VERSION 5.8 ;
BUSBITCHARS "[]" ;
DIVIDERCHAR "/" ;
UNITS
    DATABASE MICRONS 1000 ;
END UNITS

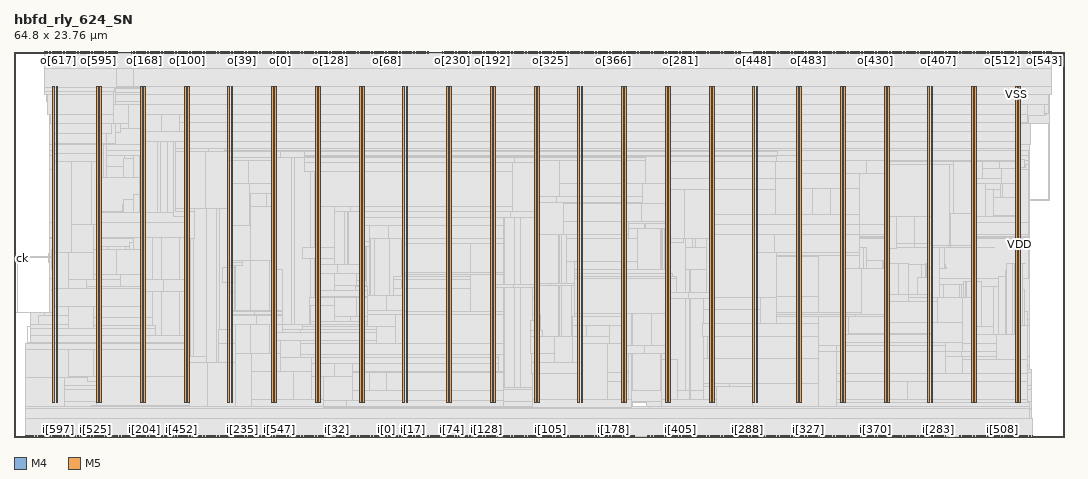
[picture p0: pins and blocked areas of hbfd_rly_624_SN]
MACRO hbfd_rly_624_SN
  FOREIGN hbfd_rly_624_SN 0 0 ;
  CLASS BLOCK ;
  SIZE 64.8 BY 23.76 ;
  PIN ck
    DIRECTION INPUT ;
    USE SIGNAL ;
    PORT
      LAYER M4 ;
        RECT  0 10.992 0.084 11.016 ;
    END
  END ck
  PIN i[0]
    DIRECTION INPUT ;
    USE SIGNAL ;
    PORT
      LAYER M5 ;
        RECT  22.992 0 23.016 0.084 ;
    END
  END i[0]
  PIN i[100]
    DIRECTION INPUT ;
    USE SIGNAL ;
    PORT
      LAYER M5 ;
        RECT  32.592 0 32.616 0.084 ;
    END
  END i[100]
  PIN i[101]
    DIRECTION INPUT ;
    USE SIGNAL ;
    PORT
      LAYER M5 ;
        RECT  32.688 0 32.712 0.084 ;
    END
  END i[101]
  PIN i[102]
    DIRECTION INPUT ;
    USE SIGNAL ;
    PORT
      LAYER M5 ;
        RECT  32.784 0 32.808 0.084 ;
    END
  END i[102]
  PIN i[103]
    DIRECTION INPUT ;
    USE SIGNAL ;
    PORT
      LAYER M5 ;
        RECT  32.88 0 32.904 0.084 ;
    END
  END i[103]
  PIN i[104]
    DIRECTION INPUT ;
    USE SIGNAL ;
    PORT
      LAYER M5 ;
        RECT  32.976 0 33 0.084 ;
    END
  END i[104]
  PIN i[105]
    DIRECTION INPUT ;
    USE SIGNAL ;
    PORT
      LAYER M5 ;
        RECT  33.072 0 33.096 0.084 ;
    END
  END i[105]
  PIN i[106]
    DIRECTION INPUT ;
    USE SIGNAL ;
    PORT
      LAYER M5 ;
        RECT  33.168 0 33.192 0.084 ;
    END
  END i[106]
  PIN i[107]
    DIRECTION INPUT ;
    USE SIGNAL ;
    PORT
      LAYER M5 ;
        RECT  33.264 0 33.288 0.084 ;
    END
  END i[107]
  PIN i[108]
    DIRECTION INPUT ;
    USE SIGNAL ;
    PORT
      LAYER M5 ;
        RECT  33.36 0 33.384 0.084 ;
    END
  END i[108]
  PIN i[109]
    DIRECTION INPUT ;
    USE SIGNAL ;
    PORT
      LAYER M5 ;
        RECT  33.456 0 33.48 0.084 ;
    END
  END i[109]
  PIN i[10]
    DIRECTION INPUT ;
    USE SIGNAL ;
    PORT
      LAYER M5 ;
        RECT  23.952 0 23.976 0.084 ;
    END
  END i[10]
  PIN i[110]
    DIRECTION INPUT ;
    USE SIGNAL ;
    PORT
      LAYER M5 ;
        RECT  33.552 0 33.576 0.084 ;
    END
  END i[110]
  PIN i[111]
    DIRECTION INPUT ;
    USE SIGNAL ;
    PORT
      LAYER M5 ;
        RECT  33.648 0 33.672 0.084 ;
    END
  END i[111]
  PIN i[112]
    DIRECTION INPUT ;
    USE SIGNAL ;
    PORT
      LAYER M5 ;
        RECT  33.744 0 33.768 0.084 ;
    END
  END i[112]
  PIN i[113]
    DIRECTION INPUT ;
    USE SIGNAL ;
    PORT
      LAYER M5 ;
        RECT  33.84 0 33.864 0.084 ;
    END
  END i[113]
  PIN i[114]
    DIRECTION INPUT ;
    USE SIGNAL ;
    PORT
      LAYER M5 ;
        RECT  33.936 0 33.96 0.084 ;
    END
  END i[114]
  PIN i[115]
    DIRECTION INPUT ;
    USE SIGNAL ;
    PORT
      LAYER M5 ;
        RECT  34.032 0 34.056 0.084 ;
    END
  END i[115]
  PIN i[116]
    DIRECTION INPUT ;
    USE SIGNAL ;
    PORT
      LAYER M5 ;
        RECT  34.128 0 34.152 0.084 ;
    END
  END i[116]
  PIN i[117]
    DIRECTION INPUT ;
    USE SIGNAL ;
    PORT
      LAYER M5 ;
        RECT  34.224 0 34.248 0.084 ;
    END
  END i[117]
  PIN i[118]
    DIRECTION INPUT ;
    USE SIGNAL ;
    PORT
      LAYER M5 ;
        RECT  34.32 0 34.344 0.084 ;
    END
  END i[118]
  PIN i[119]
    DIRECTION INPUT ;
    USE SIGNAL ;
    PORT
      LAYER M5 ;
        RECT  34.416 0 34.44 0.084 ;
    END
  END i[119]
  PIN i[11]
    DIRECTION INPUT ;
    USE SIGNAL ;
    PORT
      LAYER M5 ;
        RECT  24.048 0 24.072 0.084 ;
    END
  END i[11]
  PIN i[120]
    DIRECTION INPUT ;
    USE SIGNAL ;
    PORT
      LAYER M5 ;
        RECT  34.512 0 34.536 0.084 ;
    END
  END i[120]
  PIN i[121]
    DIRECTION INPUT ;
    USE SIGNAL ;
    PORT
      LAYER M5 ;
        RECT  34.608 0 34.632 0.084 ;
    END
  END i[121]
  PIN i[122]
    DIRECTION INPUT ;
    USE SIGNAL ;
    PORT
      LAYER M5 ;
        RECT  34.704 0 34.728 0.084 ;
    END
  END i[122]
  PIN i[123]
    DIRECTION INPUT ;
    USE SIGNAL ;
    PORT
      LAYER M5 ;
        RECT  34.8 0 34.824 0.084 ;
    END
  END i[123]
  PIN i[124]
    DIRECTION INPUT ;
    USE SIGNAL ;
    PORT
      LAYER M5 ;
        RECT  34.896 0 34.92 0.084 ;
    END
  END i[124]
  PIN i[125]
    DIRECTION INPUT ;
    USE SIGNAL ;
    PORT
      LAYER M5 ;
        RECT  34.992 0 35.016 0.084 ;
    END
  END i[125]
  PIN i[126]
    DIRECTION INPUT ;
    USE SIGNAL ;
    PORT
      LAYER M5 ;
        RECT  35.088 0 35.112 0.084 ;
    END
  END i[126]
  PIN i[127]
    DIRECTION INPUT ;
    USE SIGNAL ;
    PORT
      LAYER M5 ;
        RECT  35.184 0 35.208 0.084 ;
    END
  END i[127]
  PIN i[128]
    DIRECTION INPUT ;
    USE SIGNAL ;
    PORT
      LAYER M5 ;
        RECT  29.136 0 29.16 0.084 ;
    END
  END i[128]
  PIN i[129]
    DIRECTION INPUT ;
    USE SIGNAL ;
    PORT
      LAYER M5 ;
        RECT  29.232 0 29.256 0.084 ;
    END
  END i[129]
  PIN i[12]
    DIRECTION INPUT ;
    USE SIGNAL ;
    PORT
      LAYER M5 ;
        RECT  24.144 0 24.168 0.084 ;
    END
  END i[12]
  PIN i[130]
    DIRECTION INPUT ;
    USE SIGNAL ;
    PORT
      LAYER M5 ;
        RECT  29.328 0 29.352 0.084 ;
    END
  END i[130]
  PIN i[131]
    DIRECTION INPUT ;
    USE SIGNAL ;
    PORT
      LAYER M5 ;
        RECT  29.424 0 29.448 0.084 ;
    END
  END i[131]
  PIN i[132]
    DIRECTION INPUT ;
    USE SIGNAL ;
    PORT
      LAYER M5 ;
        RECT  29.52 0 29.544 0.084 ;
    END
  END i[132]
  PIN i[133]
    DIRECTION INPUT ;
    USE SIGNAL ;
    PORT
      LAYER M5 ;
        RECT  29.616 0 29.64 0.084 ;
    END
  END i[133]
  PIN i[134]
    DIRECTION INPUT ;
    USE SIGNAL ;
    PORT
      LAYER M5 ;
        RECT  29.712 0 29.736 0.084 ;
    END
  END i[134]
  PIN i[135]
    DIRECTION INPUT ;
    USE SIGNAL ;
    PORT
      LAYER M5 ;
        RECT  29.808 0 29.832 0.084 ;
    END
  END i[135]
  PIN i[136]
    DIRECTION INPUT ;
    USE SIGNAL ;
    PORT
      LAYER M5 ;
        RECT  29.904 0 29.928 0.084 ;
    END
  END i[136]
  PIN i[137]
    DIRECTION INPUT ;
    USE SIGNAL ;
    PORT
      LAYER M5 ;
        RECT  30 0 30.024 0.084 ;
    END
  END i[137]
  PIN i[138]
    DIRECTION INPUT ;
    USE SIGNAL ;
    PORT
      LAYER M5 ;
        RECT  30.096 0 30.12 0.084 ;
    END
  END i[138]
  PIN i[139]
    DIRECTION INPUT ;
    USE SIGNAL ;
    PORT
      LAYER M5 ;
        RECT  30.192 0 30.216 0.084 ;
    END
  END i[139]
  PIN i[13]
    DIRECTION INPUT ;
    USE SIGNAL ;
    PORT
      LAYER M5 ;
        RECT  24.24 0 24.264 0.084 ;
    END
  END i[13]
  PIN i[140]
    DIRECTION INPUT ;
    USE SIGNAL ;
    PORT
      LAYER M5 ;
        RECT  30.288 0 30.312 0.084 ;
    END
  END i[140]
  PIN i[141]
    DIRECTION INPUT ;
    USE SIGNAL ;
    PORT
      LAYER M5 ;
        RECT  30.384 0 30.408 0.084 ;
    END
  END i[141]
  PIN i[142]
    DIRECTION INPUT ;
    USE SIGNAL ;
    PORT
      LAYER M5 ;
        RECT  30.48 0 30.504 0.084 ;
    END
  END i[142]
  PIN i[143]
    DIRECTION INPUT ;
    USE SIGNAL ;
    PORT
      LAYER M5 ;
        RECT  30.576 0 30.6 0.084 ;
    END
  END i[143]
  PIN i[144]
    DIRECTION INPUT ;
    USE SIGNAL ;
    PORT
      LAYER M5 ;
        RECT  30.672 0 30.696 0.084 ;
    END
  END i[144]
  PIN i[145]
    DIRECTION INPUT ;
    USE SIGNAL ;
    PORT
      LAYER M5 ;
        RECT  30.768 0 30.792 0.084 ;
    END
  END i[145]
  PIN i[146]
    DIRECTION INPUT ;
    USE SIGNAL ;
    PORT
      LAYER M5 ;
        RECT  30.864 0 30.888 0.084 ;
    END
  END i[146]
  PIN i[147]
    DIRECTION INPUT ;
    USE SIGNAL ;
    PORT
      LAYER M5 ;
        RECT  30.96 0 30.984 0.084 ;
    END
  END i[147]
  PIN i[148]
    DIRECTION INPUT ;
    USE SIGNAL ;
    PORT
      LAYER M5 ;
        RECT  31.056 0 31.08 0.084 ;
    END
  END i[148]
  PIN i[149]
    DIRECTION INPUT ;
    USE SIGNAL ;
    PORT
      LAYER M5 ;
        RECT  31.152 0 31.176 0.084 ;
    END
  END i[149]
  PIN i[14]
    DIRECTION INPUT ;
    USE SIGNAL ;
    PORT
      LAYER M5 ;
        RECT  24.336 0 24.36 0.084 ;
    END
  END i[14]
  PIN i[150]
    DIRECTION INPUT ;
    USE SIGNAL ;
    PORT
      LAYER M5 ;
        RECT  31.248 0 31.272 0.084 ;
    END
  END i[150]
  PIN i[151]
    DIRECTION INPUT ;
    USE SIGNAL ;
    PORT
      LAYER M5 ;
        RECT  31.344 0 31.368 0.084 ;
    END
  END i[151]
  PIN i[152]
    DIRECTION INPUT ;
    USE SIGNAL ;
    PORT
      LAYER M5 ;
        RECT  31.44 0 31.464 0.084 ;
    END
  END i[152]
  PIN i[153]
    DIRECTION INPUT ;
    USE SIGNAL ;
    PORT
      LAYER M5 ;
        RECT  31.536 0 31.56 0.084 ;
    END
  END i[153]
  PIN i[154]
    DIRECTION INPUT ;
    USE SIGNAL ;
    PORT
      LAYER M5 ;
        RECT  31.632 0 31.656 0.084 ;
    END
  END i[154]
  PIN i[155]
    DIRECTION INPUT ;
    USE SIGNAL ;
    PORT
      LAYER M5 ;
        RECT  31.728 0 31.752 0.084 ;
    END
  END i[155]
  PIN i[156]
    DIRECTION INPUT ;
    USE SIGNAL ;
    PORT
      LAYER M5 ;
        RECT  31.824 0 31.848 0.084 ;
    END
  END i[156]
  PIN i[157]
    DIRECTION INPUT ;
    USE SIGNAL ;
    PORT
      LAYER M5 ;
        RECT  31.92 0 31.944 0.084 ;
    END
  END i[157]
  PIN i[158]
    DIRECTION INPUT ;
    USE SIGNAL ;
    PORT
      LAYER M5 ;
        RECT  32.016 0 32.04 0.084 ;
    END
  END i[158]
  PIN i[159]
    DIRECTION INPUT ;
    USE SIGNAL ;
    PORT
      LAYER M5 ;
        RECT  32.112 0 32.136 0.084 ;
    END
  END i[159]
  PIN i[15]
    DIRECTION INPUT ;
    USE SIGNAL ;
    PORT
      LAYER M5 ;
        RECT  24.432 0 24.456 0.084 ;
    END
  END i[15]
  PIN i[160]
    DIRECTION INPUT ;
    USE SIGNAL ;
    PORT
      LAYER M5 ;
        RECT  35.28 0 35.304 0.084 ;
    END
  END i[160]
  PIN i[161]
    DIRECTION INPUT ;
    USE SIGNAL ;
    PORT
      LAYER M5 ;
        RECT  35.376 0 35.4 0.084 ;
    END
  END i[161]
  PIN i[162]
    DIRECTION INPUT ;
    USE SIGNAL ;
    PORT
      LAYER M5 ;
        RECT  35.472 0 35.496 0.084 ;
    END
  END i[162]
  PIN i[163]
    DIRECTION INPUT ;
    USE SIGNAL ;
    PORT
      LAYER M5 ;
        RECT  35.568 0 35.592 0.084 ;
    END
  END i[163]
  PIN i[164]
    DIRECTION INPUT ;
    USE SIGNAL ;
    PORT
      LAYER M5 ;
        RECT  35.664 0 35.688 0.084 ;
    END
  END i[164]
  PIN i[165]
    DIRECTION INPUT ;
    USE SIGNAL ;
    PORT
      LAYER M5 ;
        RECT  35.76 0 35.784 0.084 ;
    END
  END i[165]
  PIN i[166]
    DIRECTION INPUT ;
    USE SIGNAL ;
    PORT
      LAYER M5 ;
        RECT  35.856 0 35.88 0.084 ;
    END
  END i[166]
  PIN i[167]
    DIRECTION INPUT ;
    USE SIGNAL ;
    PORT
      LAYER M5 ;
        RECT  35.952 0 35.976 0.084 ;
    END
  END i[167]
  PIN i[168]
    DIRECTION INPUT ;
    USE SIGNAL ;
    PORT
      LAYER M5 ;
        RECT  36.048 0 36.072 0.084 ;
    END
  END i[168]
  PIN i[169]
    DIRECTION INPUT ;
    USE SIGNAL ;
    PORT
      LAYER M5 ;
        RECT  36.144 0 36.168 0.084 ;
    END
  END i[169]
  PIN i[16]
    DIRECTION INPUT ;
    USE SIGNAL ;
    PORT
      LAYER M5 ;
        RECT  24.528 0 24.552 0.084 ;
    END
  END i[16]
  PIN i[170]
    DIRECTION INPUT ;
    USE SIGNAL ;
    PORT
      LAYER M5 ;
        RECT  36.24 0 36.264 0.084 ;
    END
  END i[170]
  PIN i[171]
    DIRECTION INPUT ;
    USE SIGNAL ;
    PORT
      LAYER M5 ;
        RECT  36.336 0 36.36 0.084 ;
    END
  END i[171]
  PIN i[172]
    DIRECTION INPUT ;
    USE SIGNAL ;
    PORT
      LAYER M5 ;
        RECT  36.432 0 36.456 0.084 ;
    END
  END i[172]
  PIN i[173]
    DIRECTION INPUT ;
    USE SIGNAL ;
    PORT
      LAYER M5 ;
        RECT  36.528 0 36.552 0.084 ;
    END
  END i[173]
  PIN i[174]
    DIRECTION INPUT ;
    USE SIGNAL ;
    PORT
      LAYER M5 ;
        RECT  36.624 0 36.648 0.084 ;
    END
  END i[174]
  PIN i[175]
    DIRECTION INPUT ;
    USE SIGNAL ;
    PORT
      LAYER M5 ;
        RECT  36.72 0 36.744 0.084 ;
    END
  END i[175]
  PIN i[176]
    DIRECTION INPUT ;
    USE SIGNAL ;
    PORT
      LAYER M5 ;
        RECT  36.816 0 36.84 0.084 ;
    END
  END i[176]
  PIN i[177]
    DIRECTION INPUT ;
    USE SIGNAL ;
    PORT
      LAYER M5 ;
        RECT  36.912 0 36.936 0.084 ;
    END
  END i[177]
  PIN i[178]
    DIRECTION INPUT ;
    USE SIGNAL ;
    PORT
      LAYER M5 ;
        RECT  37.008 0 37.032 0.084 ;
    END
  END i[178]
  PIN i[179]
    DIRECTION INPUT ;
    USE SIGNAL ;
    PORT
      LAYER M5 ;
        RECT  37.104 0 37.128 0.084 ;
    END
  END i[179]
  PIN i[17]
    DIRECTION INPUT ;
    USE SIGNAL ;
    PORT
      LAYER M5 ;
        RECT  24.624 0 24.648 0.084 ;
    END
  END i[17]
  PIN i[180]
    DIRECTION INPUT ;
    USE SIGNAL ;
    PORT
      LAYER M5 ;
        RECT  37.2 0 37.224 0.084 ;
    END
  END i[180]
  PIN i[181]
    DIRECTION INPUT ;
    USE SIGNAL ;
    PORT
      LAYER M5 ;
        RECT  37.296 0 37.32 0.084 ;
    END
  END i[181]
  PIN i[182]
    DIRECTION INPUT ;
    USE SIGNAL ;
    PORT
      LAYER M5 ;
        RECT  37.392 0 37.416 0.084 ;
    END
  END i[182]
  PIN i[183]
    DIRECTION INPUT ;
    USE SIGNAL ;
    PORT
      LAYER M5 ;
        RECT  37.488 0 37.512 0.084 ;
    END
  END i[183]
  PIN i[184]
    DIRECTION INPUT ;
    USE SIGNAL ;
    PORT
      LAYER M5 ;
        RECT  37.584 0 37.608 0.084 ;
    END
  END i[184]
  PIN i[185]
    DIRECTION INPUT ;
    USE SIGNAL ;
    PORT
      LAYER M5 ;
        RECT  37.68 0 37.704 0.084 ;
    END
  END i[185]
  PIN i[186]
    DIRECTION INPUT ;
    USE SIGNAL ;
    PORT
      LAYER M5 ;
        RECT  37.776 0 37.8 0.084 ;
    END
  END i[186]
  PIN i[187]
    DIRECTION INPUT ;
    USE SIGNAL ;
    PORT
      LAYER M5 ;
        RECT  37.872 0 37.896 0.084 ;
    END
  END i[187]
  PIN i[188]
    DIRECTION INPUT ;
    USE SIGNAL ;
    PORT
      LAYER M5 ;
        RECT  37.968 0 37.992 0.084 ;
    END
  END i[188]
  PIN i[189]
    DIRECTION INPUT ;
    USE SIGNAL ;
    PORT
      LAYER M5 ;
        RECT  38.064 0 38.088 0.084 ;
    END
  END i[189]
  PIN i[18]
    DIRECTION INPUT ;
    USE SIGNAL ;
    PORT
      LAYER M5 ;
        RECT  24.72 0 24.744 0.084 ;
    END
  END i[18]
  PIN i[190]
    DIRECTION INPUT ;
    USE SIGNAL ;
    PORT
      LAYER M5 ;
        RECT  38.16 0 38.184 0.084 ;
    END
  END i[190]
  PIN i[191]
    DIRECTION INPUT ;
    USE SIGNAL ;
    PORT
      LAYER M5 ;
        RECT  38.256 0 38.28 0.084 ;
    END
  END i[191]
  PIN i[192]
    DIRECTION INPUT ;
    USE SIGNAL ;
    PORT
      LAYER M5 ;
        RECT  6.864 0 6.888 0.084 ;
    END
  END i[192]
  PIN i[193]
    DIRECTION INPUT ;
    USE SIGNAL ;
    PORT
      LAYER M5 ;
        RECT  6.96 0 6.984 0.084 ;
    END
  END i[193]
  PIN i[194]
    DIRECTION INPUT ;
    USE SIGNAL ;
    PORT
      LAYER M5 ;
        RECT  7.056 0 7.08 0.084 ;
    END
  END i[194]
  PIN i[195]
    DIRECTION INPUT ;
    USE SIGNAL ;
    PORT
      LAYER M5 ;
        RECT  7.152 0 7.176 0.084 ;
    END
  END i[195]
  PIN i[196]
    DIRECTION INPUT ;
    USE SIGNAL ;
    PORT
      LAYER M5 ;
        RECT  7.248 0 7.272 0.084 ;
    END
  END i[196]
  PIN i[197]
    DIRECTION INPUT ;
    USE SIGNAL ;
    PORT
      LAYER M5 ;
        RECT  7.344 0 7.368 0.084 ;
    END
  END i[197]
  PIN i[198]
    DIRECTION INPUT ;
    USE SIGNAL ;
    PORT
      LAYER M5 ;
        RECT  7.44 0 7.464 0.084 ;
    END
  END i[198]
  PIN i[199]
    DIRECTION INPUT ;
    USE SIGNAL ;
    PORT
      LAYER M5 ;
        RECT  7.536 0 7.56 0.084 ;
    END
  END i[199]
  PIN i[19]
    DIRECTION INPUT ;
    USE SIGNAL ;
    PORT
      LAYER M5 ;
        RECT  24.816 0 24.84 0.084 ;
    END
  END i[19]
  PIN i[1]
    DIRECTION INPUT ;
    USE SIGNAL ;
    PORT
      LAYER M5 ;
        RECT  23.088 0 23.112 0.084 ;
    END
  END i[1]
  PIN i[200]
    DIRECTION INPUT ;
    USE SIGNAL ;
    PORT
      LAYER M5 ;
        RECT  7.632 0 7.656 0.084 ;
    END
  END i[200]
  PIN i[201]
    DIRECTION INPUT ;
    USE SIGNAL ;
    PORT
      LAYER M5 ;
        RECT  7.728 0 7.752 0.084 ;
    END
  END i[201]
  PIN i[202]
    DIRECTION INPUT ;
    USE SIGNAL ;
    PORT
      LAYER M5 ;
        RECT  7.824 0 7.848 0.084 ;
    END
  END i[202]
  PIN i[203]
    DIRECTION INPUT ;
    USE SIGNAL ;
    PORT
      LAYER M5 ;
        RECT  7.92 0 7.944 0.084 ;
    END
  END i[203]
  PIN i[204]
    DIRECTION INPUT ;
    USE SIGNAL ;
    PORT
      LAYER M5 ;
        RECT  8.016 0 8.04 0.084 ;
    END
  END i[204]
  PIN i[205]
    DIRECTION INPUT ;
    USE SIGNAL ;
    PORT
      LAYER M5 ;
        RECT  8.112 0 8.136 0.084 ;
    END
  END i[205]
  PIN i[206]
    DIRECTION INPUT ;
    USE SIGNAL ;
    PORT
      LAYER M5 ;
        RECT  8.208 0 8.232 0.084 ;
    END
  END i[206]
  PIN i[207]
    DIRECTION INPUT ;
    USE SIGNAL ;
    PORT
      LAYER M5 ;
        RECT  8.304 0 8.328 0.084 ;
    END
  END i[207]
  PIN i[208]
    DIRECTION INPUT ;
    USE SIGNAL ;
    PORT
      LAYER M5 ;
        RECT  8.4 0 8.424 0.084 ;
    END
  END i[208]
  PIN i[209]
    DIRECTION INPUT ;
    USE SIGNAL ;
    PORT
      LAYER M5 ;
        RECT  8.496 0 8.52 0.084 ;
    END
  END i[209]
  PIN i[20]
    DIRECTION INPUT ;
    USE SIGNAL ;
    PORT
      LAYER M5 ;
        RECT  24.912 0 24.936 0.084 ;
    END
  END i[20]
  PIN i[210]
    DIRECTION INPUT ;
    USE SIGNAL ;
    PORT
      LAYER M5 ;
        RECT  8.592 0 8.616 0.084 ;
    END
  END i[210]
  PIN i[211]
    DIRECTION INPUT ;
    USE SIGNAL ;
    PORT
      LAYER M5 ;
        RECT  8.688 0 8.712 0.084 ;
    END
  END i[211]
  PIN i[212]
    DIRECTION INPUT ;
    USE SIGNAL ;
    PORT
      LAYER M5 ;
        RECT  8.784 0 8.808 0.084 ;
    END
  END i[212]
  PIN i[213]
    DIRECTION INPUT ;
    USE SIGNAL ;
    PORT
      LAYER M5 ;
        RECT  8.88 0 8.904 0.084 ;
    END
  END i[213]
  PIN i[214]
    DIRECTION INPUT ;
    USE SIGNAL ;
    PORT
      LAYER M5 ;
        RECT  8.976 0 9 0.084 ;
    END
  END i[214]
  PIN i[215]
    DIRECTION INPUT ;
    USE SIGNAL ;
    PORT
      LAYER M5 ;
        RECT  9.072 0 9.096 0.084 ;
    END
  END i[215]
  PIN i[216]
    DIRECTION INPUT ;
    USE SIGNAL ;
    PORT
      LAYER M5 ;
        RECT  9.168 0 9.192 0.084 ;
    END
  END i[216]
  PIN i[217]
    DIRECTION INPUT ;
    USE SIGNAL ;
    PORT
      LAYER M5 ;
        RECT  9.264 0 9.288 0.084 ;
    END
  END i[217]
  PIN i[218]
    DIRECTION INPUT ;
    USE SIGNAL ;
    PORT
      LAYER M5 ;
        RECT  9.36 0 9.384 0.084 ;
    END
  END i[218]
  PIN i[219]
    DIRECTION INPUT ;
    USE SIGNAL ;
    PORT
      LAYER M5 ;
        RECT  9.456 0 9.48 0.084 ;
    END
  END i[219]
  PIN i[21]
    DIRECTION INPUT ;
    USE SIGNAL ;
    PORT
      LAYER M5 ;
        RECT  25.008 0 25.032 0.084 ;
    END
  END i[21]
  PIN i[220]
    DIRECTION INPUT ;
    USE SIGNAL ;
    PORT
      LAYER M5 ;
        RECT  9.552 0 9.576 0.084 ;
    END
  END i[220]
  PIN i[221]
    DIRECTION INPUT ;
    USE SIGNAL ;
    PORT
      LAYER M5 ;
        RECT  9.648 0 9.672 0.084 ;
    END
  END i[221]
  PIN i[222]
    DIRECTION INPUT ;
    USE SIGNAL ;
    PORT
      LAYER M5 ;
        RECT  9.744 0 9.768 0.084 ;
    END
  END i[222]
  PIN i[223]
    DIRECTION INPUT ;
    USE SIGNAL ;
    PORT
      LAYER M5 ;
        RECT  9.84 0 9.864 0.084 ;
    END
  END i[223]
  PIN i[224]
    DIRECTION INPUT ;
    USE SIGNAL ;
    PORT
      LAYER M5 ;
        RECT  13.008 0 13.032 0.084 ;
    END
  END i[224]
  PIN i[225]
    DIRECTION INPUT ;
    USE SIGNAL ;
    PORT
      LAYER M5 ;
        RECT  13.104 0 13.128 0.084 ;
    END
  END i[225]
  PIN i[226]
    DIRECTION INPUT ;
    USE SIGNAL ;
    PORT
      LAYER M5 ;
        RECT  13.2 0 13.224 0.084 ;
    END
  END i[226]
  PIN i[227]
    DIRECTION INPUT ;
    USE SIGNAL ;
    PORT
      LAYER M5 ;
        RECT  13.296 0 13.32 0.084 ;
    END
  END i[227]
  PIN i[228]
    DIRECTION INPUT ;
    USE SIGNAL ;
    PORT
      LAYER M5 ;
        RECT  13.392 0 13.416 0.084 ;
    END
  END i[228]
  PIN i[229]
    DIRECTION INPUT ;
    USE SIGNAL ;
    PORT
      LAYER M5 ;
        RECT  13.488 0 13.512 0.084 ;
    END
  END i[229]
  PIN i[22]
    DIRECTION INPUT ;
    USE SIGNAL ;
    PORT
      LAYER M5 ;
        RECT  25.104 0 25.128 0.084 ;
    END
  END i[22]
  PIN i[230]
    DIRECTION INPUT ;
    USE SIGNAL ;
    PORT
      LAYER M5 ;
        RECT  13.584 0 13.608 0.084 ;
    END
  END i[230]
  PIN i[231]
    DIRECTION INPUT ;
    USE SIGNAL ;
    PORT
      LAYER M5 ;
        RECT  13.68 0 13.704 0.084 ;
    END
  END i[231]
  PIN i[232]
    DIRECTION INPUT ;
    USE SIGNAL ;
    PORT
      LAYER M5 ;
        RECT  13.776 0 13.8 0.084 ;
    END
  END i[232]
  PIN i[233]
    DIRECTION INPUT ;
    USE SIGNAL ;
    PORT
      LAYER M5 ;
        RECT  13.872 0 13.896 0.084 ;
    END
  END i[233]
  PIN i[234]
    DIRECTION INPUT ;
    USE SIGNAL ;
    PORT
      LAYER M5 ;
        RECT  13.968 0 13.992 0.084 ;
    END
  END i[234]
  PIN i[235]
    DIRECTION INPUT ;
    USE SIGNAL ;
    PORT
      LAYER M5 ;
        RECT  14.064 0 14.088 0.084 ;
    END
  END i[235]
  PIN i[236]
    DIRECTION INPUT ;
    USE SIGNAL ;
    PORT
      LAYER M5 ;
        RECT  14.16 0 14.184 0.084 ;
    END
  END i[236]
  PIN i[237]
    DIRECTION INPUT ;
    USE SIGNAL ;
    PORT
      LAYER M5 ;
        RECT  14.256 0 14.28 0.084 ;
    END
  END i[237]
  PIN i[238]
    DIRECTION INPUT ;
    USE SIGNAL ;
    PORT
      LAYER M5 ;
        RECT  14.352 0 14.376 0.084 ;
    END
  END i[238]
  PIN i[239]
    DIRECTION INPUT ;
    USE SIGNAL ;
    PORT
      LAYER M5 ;
        RECT  14.448 0 14.472 0.084 ;
    END
  END i[239]
  PIN i[23]
    DIRECTION INPUT ;
    USE SIGNAL ;
    PORT
      LAYER M5 ;
        RECT  25.2 0 25.224 0.084 ;
    END
  END i[23]
  PIN i[240]
    DIRECTION INPUT ;
    USE SIGNAL ;
    PORT
      LAYER M5 ;
        RECT  14.544 0 14.568 0.084 ;
    END
  END i[240]
  PIN i[241]
    DIRECTION INPUT ;
    USE SIGNAL ;
    PORT
      LAYER M5 ;
        RECT  14.64 0 14.664 0.084 ;
    END
  END i[241]
  PIN i[242]
    DIRECTION INPUT ;
    USE SIGNAL ;
    PORT
      LAYER M5 ;
        RECT  14.736 0 14.76 0.084 ;
    END
  END i[242]
  PIN i[243]
    DIRECTION INPUT ;
    USE SIGNAL ;
    PORT
      LAYER M5 ;
        RECT  14.832 0 14.856 0.084 ;
    END
  END i[243]
  PIN i[244]
    DIRECTION INPUT ;
    USE SIGNAL ;
    PORT
      LAYER M5 ;
        RECT  14.928 0 14.952 0.084 ;
    END
  END i[244]
  PIN i[245]
    DIRECTION INPUT ;
    USE SIGNAL ;
    PORT
      LAYER M5 ;
        RECT  15.024 0 15.048 0.084 ;
    END
  END i[245]
  PIN i[246]
    DIRECTION INPUT ;
    USE SIGNAL ;
    PORT
      LAYER M5 ;
        RECT  15.12 0 15.144 0.084 ;
    END
  END i[246]
  PIN i[247]
    DIRECTION INPUT ;
    USE SIGNAL ;
    PORT
      LAYER M5 ;
        RECT  15.216 0 15.24 0.084 ;
    END
  END i[247]
  PIN i[248]
    DIRECTION INPUT ;
    USE SIGNAL ;
    PORT
      LAYER M5 ;
        RECT  15.312 0 15.336 0.084 ;
    END
  END i[248]
  PIN i[249]
    DIRECTION INPUT ;
    USE SIGNAL ;
    PORT
      LAYER M5 ;
        RECT  15.408 0 15.432 0.084 ;
    END
  END i[249]
  PIN i[24]
    DIRECTION INPUT ;
    USE SIGNAL ;
    PORT
      LAYER M5 ;
        RECT  25.296 0 25.32 0.084 ;
    END
  END i[24]
  PIN i[250]
    DIRECTION INPUT ;
    USE SIGNAL ;
    PORT
      LAYER M5 ;
        RECT  15.504 0 15.528 0.084 ;
    END
  END i[250]
  PIN i[251]
    DIRECTION INPUT ;
    USE SIGNAL ;
    PORT
      LAYER M5 ;
        RECT  15.6 0 15.624 0.084 ;
    END
  END i[251]
  PIN i[252]
    DIRECTION INPUT ;
    USE SIGNAL ;
    PORT
      LAYER M5 ;
        RECT  15.696 0 15.72 0.084 ;
    END
  END i[252]
  PIN i[253]
    DIRECTION INPUT ;
    USE SIGNAL ;
    PORT
      LAYER M5 ;
        RECT  15.792 0 15.816 0.084 ;
    END
  END i[253]
  PIN i[254]
    DIRECTION INPUT ;
    USE SIGNAL ;
    PORT
      LAYER M5 ;
        RECT  15.888 0 15.912 0.084 ;
    END
  END i[254]
  PIN i[255]
    DIRECTION INPUT ;
    USE SIGNAL ;
    PORT
      LAYER M5 ;
        RECT  15.984 0 16.008 0.084 ;
    END
  END i[255]
  PIN i[256]
    DIRECTION INPUT ;
    USE SIGNAL ;
    PORT
      LAYER M5 ;
        RECT  54.48 0 54.504 0.084 ;
    END
  END i[256]
  PIN i[257]
    DIRECTION INPUT ;
    USE SIGNAL ;
    PORT
      LAYER M5 ;
        RECT  54.576 0 54.6 0.084 ;
    END
  END i[257]
  PIN i[258]
    DIRECTION INPUT ;
    USE SIGNAL ;
    PORT
      LAYER M5 ;
        RECT  54.672 0 54.696 0.084 ;
    END
  END i[258]
  PIN i[259]
    DIRECTION INPUT ;
    USE SIGNAL ;
    PORT
      LAYER M5 ;
        RECT  54.768 0 54.792 0.084 ;
    END
  END i[259]
  PIN i[25]
    DIRECTION INPUT ;
    USE SIGNAL ;
    PORT
      LAYER M5 ;
        RECT  25.392 0 25.416 0.084 ;
    END
  END i[25]
  PIN i[260]
    DIRECTION INPUT ;
    USE SIGNAL ;
    PORT
      LAYER M5 ;
        RECT  54.864 0 54.888 0.084 ;
    END
  END i[260]
  PIN i[261]
    DIRECTION INPUT ;
    USE SIGNAL ;
    PORT
      LAYER M5 ;
        RECT  54.96 0 54.984 0.084 ;
    END
  END i[261]
  PIN i[262]
    DIRECTION INPUT ;
    USE SIGNAL ;
    PORT
      LAYER M5 ;
        RECT  55.056 0 55.08 0.084 ;
    END
  END i[262]
  PIN i[263]
    DIRECTION INPUT ;
    USE SIGNAL ;
    PORT
      LAYER M5 ;
        RECT  55.152 0 55.176 0.084 ;
    END
  END i[263]
  PIN i[264]
    DIRECTION INPUT ;
    USE SIGNAL ;
    PORT
      LAYER M5 ;
        RECT  55.248 0 55.272 0.084 ;
    END
  END i[264]
  PIN i[265]
    DIRECTION INPUT ;
    USE SIGNAL ;
    PORT
      LAYER M5 ;
        RECT  55.344 0 55.368 0.084 ;
    END
  END i[265]
  PIN i[266]
    DIRECTION INPUT ;
    USE SIGNAL ;
    PORT
      LAYER M5 ;
        RECT  55.44 0 55.464 0.084 ;
    END
  END i[266]
  PIN i[267]
    DIRECTION INPUT ;
    USE SIGNAL ;
    PORT
      LAYER M5 ;
        RECT  55.536 0 55.56 0.084 ;
    END
  END i[267]
  PIN i[268]
    DIRECTION INPUT ;
    USE SIGNAL ;
    PORT
      LAYER M5 ;
        RECT  55.632 0 55.656 0.084 ;
    END
  END i[268]
  PIN i[269]
    DIRECTION INPUT ;
    USE SIGNAL ;
    PORT
      LAYER M5 ;
        RECT  55.728 0 55.752 0.084 ;
    END
  END i[269]
  PIN i[26]
    DIRECTION INPUT ;
    USE SIGNAL ;
    PORT
      LAYER M5 ;
        RECT  25.488 0 25.512 0.084 ;
    END
  END i[26]
  PIN i[270]
    DIRECTION INPUT ;
    USE SIGNAL ;
    PORT
      LAYER M5 ;
        RECT  55.824 0 55.848 0.084 ;
    END
  END i[270]
  PIN i[271]
    DIRECTION INPUT ;
    USE SIGNAL ;
    PORT
      LAYER M5 ;
        RECT  55.92 0 55.944 0.084 ;
    END
  END i[271]
  PIN i[272]
    DIRECTION INPUT ;
    USE SIGNAL ;
    PORT
      LAYER M5 ;
        RECT  56.016 0 56.04 0.084 ;
    END
  END i[272]
  PIN i[273]
    DIRECTION INPUT ;
    USE SIGNAL ;
    PORT
      LAYER M5 ;
        RECT  56.112 0 56.136 0.084 ;
    END
  END i[273]
  PIN i[274]
    DIRECTION INPUT ;
    USE SIGNAL ;
    PORT
      LAYER M5 ;
        RECT  56.208 0 56.232 0.084 ;
    END
  END i[274]
  PIN i[275]
    DIRECTION INPUT ;
    USE SIGNAL ;
    PORT
      LAYER M5 ;
        RECT  56.304 0 56.328 0.084 ;
    END
  END i[275]
  PIN i[276]
    DIRECTION INPUT ;
    USE SIGNAL ;
    PORT
      LAYER M5 ;
        RECT  56.4 0 56.424 0.084 ;
    END
  END i[276]
  PIN i[277]
    DIRECTION INPUT ;
    USE SIGNAL ;
    PORT
      LAYER M5 ;
        RECT  56.496 0 56.52 0.084 ;
    END
  END i[277]
  PIN i[278]
    DIRECTION INPUT ;
    USE SIGNAL ;
    PORT
      LAYER M5 ;
        RECT  56.592 0 56.616 0.084 ;
    END
  END i[278]
  PIN i[279]
    DIRECTION INPUT ;
    USE SIGNAL ;
    PORT
      LAYER M5 ;
        RECT  56.688 0 56.712 0.084 ;
    END
  END i[279]
  PIN i[27]
    DIRECTION INPUT ;
    USE SIGNAL ;
    PORT
      LAYER M5 ;
        RECT  25.584 0 25.608 0.084 ;
    END
  END i[27]
  PIN i[280]
    DIRECTION INPUT ;
    USE SIGNAL ;
    PORT
      LAYER M5 ;
        RECT  56.784 0 56.808 0.084 ;
    END
  END i[280]
  PIN i[281]
    DIRECTION INPUT ;
    USE SIGNAL ;
    PORT
      LAYER M5 ;
        RECT  56.88 0 56.904 0.084 ;
    END
  END i[281]
  PIN i[282]
    DIRECTION INPUT ;
    USE SIGNAL ;
    PORT
      LAYER M5 ;
        RECT  56.976 0 57 0.084 ;
    END
  END i[282]
  PIN i[283]
    DIRECTION INPUT ;
    USE SIGNAL ;
    PORT
      LAYER M5 ;
        RECT  57.072 0 57.096 0.084 ;
    END
  END i[283]
  PIN i[284]
    DIRECTION INPUT ;
    USE SIGNAL ;
    PORT
      LAYER M5 ;
        RECT  57.168 0 57.192 0.084 ;
    END
  END i[284]
  PIN i[285]
    DIRECTION INPUT ;
    USE SIGNAL ;
    PORT
      LAYER M5 ;
        RECT  57.264 0 57.288 0.084 ;
    END
  END i[285]
  PIN i[286]
    DIRECTION INPUT ;
    USE SIGNAL ;
    PORT
      LAYER M5 ;
        RECT  57.36 0 57.384 0.084 ;
    END
  END i[286]
  PIN i[287]
    DIRECTION INPUT ;
    USE SIGNAL ;
    PORT
      LAYER M5 ;
        RECT  57.456 0 57.48 0.084 ;
    END
  END i[287]
  PIN i[288]
    DIRECTION INPUT ;
    USE SIGNAL ;
    PORT
      LAYER M5 ;
        RECT  45.264 0 45.288 0.084 ;
    END
  END i[288]
  PIN i[289]
    DIRECTION INPUT ;
    USE SIGNAL ;
    PORT
      LAYER M5 ;
        RECT  45.36 0 45.384 0.084 ;
    END
  END i[289]
  PIN i[28]
    DIRECTION INPUT ;
    USE SIGNAL ;
    PORT
      LAYER M5 ;
        RECT  25.68 0 25.704 0.084 ;
    END
  END i[28]
  PIN i[290]
    DIRECTION INPUT ;
    USE SIGNAL ;
    PORT
      LAYER M5 ;
        RECT  45.456 0 45.48 0.084 ;
    END
  END i[290]
  PIN i[291]
    DIRECTION INPUT ;
    USE SIGNAL ;
    PORT
      LAYER M5 ;
        RECT  45.552 0 45.576 0.084 ;
    END
  END i[291]
  PIN i[292]
    DIRECTION INPUT ;
    USE SIGNAL ;
    PORT
      LAYER M5 ;
        RECT  45.648 0 45.672 0.084 ;
    END
  END i[292]
  PIN i[293]
    DIRECTION INPUT ;
    USE SIGNAL ;
    PORT
      LAYER M5 ;
        RECT  45.744 0 45.768 0.084 ;
    END
  END i[293]
  PIN i[294]
    DIRECTION INPUT ;
    USE SIGNAL ;
    PORT
      LAYER M5 ;
        RECT  45.84 0 45.864 0.084 ;
    END
  END i[294]
  PIN i[295]
    DIRECTION INPUT ;
    USE SIGNAL ;
    PORT
      LAYER M5 ;
        RECT  45.936 0 45.96 0.084 ;
    END
  END i[295]
  PIN i[296]
    DIRECTION INPUT ;
    USE SIGNAL ;
    PORT
      LAYER M5 ;
        RECT  46.032 0 46.056 0.084 ;
    END
  END i[296]
  PIN i[297]
    DIRECTION INPUT ;
    USE SIGNAL ;
    PORT
      LAYER M5 ;
        RECT  46.128 0 46.152 0.084 ;
    END
  END i[297]
  PIN i[298]
    DIRECTION INPUT ;
    USE SIGNAL ;
    PORT
      LAYER M5 ;
        RECT  46.224 0 46.248 0.084 ;
    END
  END i[298]
  PIN i[299]
    DIRECTION INPUT ;
    USE SIGNAL ;
    PORT
      LAYER M5 ;
        RECT  46.32 0 46.344 0.084 ;
    END
  END i[299]
  PIN i[29]
    DIRECTION INPUT ;
    USE SIGNAL ;
    PORT
      LAYER M5 ;
        RECT  25.776 0 25.8 0.084 ;
    END
  END i[29]
  PIN i[2]
    DIRECTION INPUT ;
    USE SIGNAL ;
    PORT
      LAYER M5 ;
        RECT  23.184 0 23.208 0.084 ;
    END
  END i[2]
  PIN i[300]
    DIRECTION INPUT ;
    USE SIGNAL ;
    PORT
      LAYER M5 ;
        RECT  46.416 0 46.44 0.084 ;
    END
  END i[300]
  PIN i[301]
    DIRECTION INPUT ;
    USE SIGNAL ;
    PORT
      LAYER M5 ;
        RECT  46.512 0 46.536 0.084 ;
    END
  END i[301]
  PIN i[302]
    DIRECTION INPUT ;
    USE SIGNAL ;
    PORT
      LAYER M5 ;
        RECT  46.608 0 46.632 0.084 ;
    END
  END i[302]
  PIN i[303]
    DIRECTION INPUT ;
    USE SIGNAL ;
    PORT
      LAYER M5 ;
        RECT  46.704 0 46.728 0.084 ;
    END
  END i[303]
  PIN i[304]
    DIRECTION INPUT ;
    USE SIGNAL ;
    PORT
      LAYER M5 ;
        RECT  46.8 0 46.824 0.084 ;
    END
  END i[304]
  PIN i[305]
    DIRECTION INPUT ;
    USE SIGNAL ;
    PORT
      LAYER M5 ;
        RECT  46.896 0 46.92 0.084 ;
    END
  END i[305]
  PIN i[306]
    DIRECTION INPUT ;
    USE SIGNAL ;
    PORT
      LAYER M5 ;
        RECT  46.992 0 47.016 0.084 ;
    END
  END i[306]
  PIN i[307]
    DIRECTION INPUT ;
    USE SIGNAL ;
    PORT
      LAYER M5 ;
        RECT  47.088 0 47.112 0.084 ;
    END
  END i[307]
  PIN i[308]
    DIRECTION INPUT ;
    USE SIGNAL ;
    PORT
      LAYER M5 ;
        RECT  47.184 0 47.208 0.084 ;
    END
  END i[308]
  PIN i[309]
    DIRECTION INPUT ;
    USE SIGNAL ;
    PORT
      LAYER M5 ;
        RECT  47.28 0 47.304 0.084 ;
    END
  END i[309]
  PIN i[30]
    DIRECTION INPUT ;
    USE SIGNAL ;
    PORT
      LAYER M5 ;
        RECT  25.872 0 25.896 0.084 ;
    END
  END i[30]
  PIN i[310]
    DIRECTION INPUT ;
    USE SIGNAL ;
    PORT
      LAYER M5 ;
        RECT  47.376 0 47.4 0.084 ;
    END
  END i[310]
  PIN i[311]
    DIRECTION INPUT ;
    USE SIGNAL ;
    PORT
      LAYER M5 ;
        RECT  47.472 0 47.496 0.084 ;
    END
  END i[311]
  PIN i[312]
    DIRECTION INPUT ;
    USE SIGNAL ;
    PORT
      LAYER M5 ;
        RECT  47.568 0 47.592 0.084 ;
    END
  END i[312]
  PIN i[313]
    DIRECTION INPUT ;
    USE SIGNAL ;
    PORT
      LAYER M5 ;
        RECT  47.664 0 47.688 0.084 ;
    END
  END i[313]
  PIN i[314]
    DIRECTION INPUT ;
    USE SIGNAL ;
    PORT
      LAYER M5 ;
        RECT  47.76 0 47.784 0.084 ;
    END
  END i[314]
  PIN i[315]
    DIRECTION INPUT ;
    USE SIGNAL ;
    PORT
      LAYER M5 ;
        RECT  47.856 0 47.88 0.084 ;
    END
  END i[315]
  PIN i[316]
    DIRECTION INPUT ;
    USE SIGNAL ;
    PORT
      LAYER M5 ;
        RECT  47.952 0 47.976 0.084 ;
    END
  END i[316]
  PIN i[317]
    DIRECTION INPUT ;
    USE SIGNAL ;
    PORT
      LAYER M5 ;
        RECT  48.048 0 48.072 0.084 ;
    END
  END i[317]
  PIN i[318]
    DIRECTION INPUT ;
    USE SIGNAL ;
    PORT
      LAYER M5 ;
        RECT  48.144 0 48.168 0.084 ;
    END
  END i[318]
  PIN i[319]
    DIRECTION INPUT ;
    USE SIGNAL ;
    PORT
      LAYER M5 ;
        RECT  48.24 0 48.264 0.084 ;
    END
  END i[319]
  PIN i[31]
    DIRECTION INPUT ;
    USE SIGNAL ;
    PORT
      LAYER M5 ;
        RECT  25.968 0 25.992 0.084 ;
    END
  END i[31]
  PIN i[320]
    DIRECTION INPUT ;
    USE SIGNAL ;
    PORT
      LAYER M5 ;
        RECT  48.336 0 48.36 0.084 ;
    END
  END i[320]
  PIN i[321]
    DIRECTION INPUT ;
    USE SIGNAL ;
    PORT
      LAYER M5 ;
        RECT  48.432 0 48.456 0.084 ;
    END
  END i[321]
  PIN i[322]
    DIRECTION INPUT ;
    USE SIGNAL ;
    PORT
      LAYER M5 ;
        RECT  48.528 0 48.552 0.084 ;
    END
  END i[322]
  PIN i[323]
    DIRECTION INPUT ;
    USE SIGNAL ;
    PORT
      LAYER M5 ;
        RECT  48.624 0 48.648 0.084 ;
    END
  END i[323]
  PIN i[324]
    DIRECTION INPUT ;
    USE SIGNAL ;
    PORT
      LAYER M5 ;
        RECT  48.72 0 48.744 0.084 ;
    END
  END i[324]
  PIN i[325]
    DIRECTION INPUT ;
    USE SIGNAL ;
    PORT
      LAYER M5 ;
        RECT  48.816 0 48.84 0.084 ;
    END
  END i[325]
  PIN i[326]
    DIRECTION INPUT ;
    USE SIGNAL ;
    PORT
      LAYER M5 ;
        RECT  48.912 0 48.936 0.084 ;
    END
  END i[326]
  PIN i[327]
    DIRECTION INPUT ;
    USE SIGNAL ;
    PORT
      LAYER M5 ;
        RECT  49.008 0 49.032 0.084 ;
    END
  END i[327]
  PIN i[328]
    DIRECTION INPUT ;
    USE SIGNAL ;
    PORT
      LAYER M5 ;
        RECT  49.104 0 49.128 0.084 ;
    END
  END i[328]
  PIN i[329]
    DIRECTION INPUT ;
    USE SIGNAL ;
    PORT
      LAYER M5 ;
        RECT  49.2 0 49.224 0.084 ;
    END
  END i[329]
  PIN i[32]
    DIRECTION INPUT ;
    USE SIGNAL ;
    PORT
      LAYER M5 ;
        RECT  19.92 0 19.944 0.084 ;
    END
  END i[32]
  PIN i[330]
    DIRECTION INPUT ;
    USE SIGNAL ;
    PORT
      LAYER M5 ;
        RECT  49.296 0 49.32 0.084 ;
    END
  END i[330]
  PIN i[331]
    DIRECTION INPUT ;
    USE SIGNAL ;
    PORT
      LAYER M5 ;
        RECT  49.392 0 49.416 0.084 ;
    END
  END i[331]
  PIN i[332]
    DIRECTION INPUT ;
    USE SIGNAL ;
    PORT
      LAYER M5 ;
        RECT  49.488 0 49.512 0.084 ;
    END
  END i[332]
  PIN i[333]
    DIRECTION INPUT ;
    USE SIGNAL ;
    PORT
      LAYER M5 ;
        RECT  49.584 0 49.608 0.084 ;
    END
  END i[333]
  PIN i[334]
    DIRECTION INPUT ;
    USE SIGNAL ;
    PORT
      LAYER M5 ;
        RECT  49.68 0 49.704 0.084 ;
    END
  END i[334]
  PIN i[335]
    DIRECTION INPUT ;
    USE SIGNAL ;
    PORT
      LAYER M5 ;
        RECT  49.776 0 49.8 0.084 ;
    END
  END i[335]
  PIN i[336]
    DIRECTION INPUT ;
    USE SIGNAL ;
    PORT
      LAYER M5 ;
        RECT  49.872 0 49.896 0.084 ;
    END
  END i[336]
  PIN i[337]
    DIRECTION INPUT ;
    USE SIGNAL ;
    PORT
      LAYER M5 ;
        RECT  49.968 0 49.992 0.084 ;
    END
  END i[337]
  PIN i[338]
    DIRECTION INPUT ;
    USE SIGNAL ;
    PORT
      LAYER M5 ;
        RECT  50.064 0 50.088 0.084 ;
    END
  END i[338]
  PIN i[339]
    DIRECTION INPUT ;
    USE SIGNAL ;
    PORT
      LAYER M5 ;
        RECT  50.16 0 50.184 0.084 ;
    END
  END i[339]
  PIN i[33]
    DIRECTION INPUT ;
    USE SIGNAL ;
    PORT
      LAYER M5 ;
        RECT  20.016 0 20.04 0.084 ;
    END
  END i[33]
  PIN i[340]
    DIRECTION INPUT ;
    USE SIGNAL ;
    PORT
      LAYER M5 ;
        RECT  50.256 0 50.28 0.084 ;
    END
  END i[340]
  PIN i[341]
    DIRECTION INPUT ;
    USE SIGNAL ;
    PORT
      LAYER M5 ;
        RECT  50.352 0 50.376 0.084 ;
    END
  END i[341]
  PIN i[342]
    DIRECTION INPUT ;
    USE SIGNAL ;
    PORT
      LAYER M5 ;
        RECT  50.448 0 50.472 0.084 ;
    END
  END i[342]
  PIN i[343]
    DIRECTION INPUT ;
    USE SIGNAL ;
    PORT
      LAYER M5 ;
        RECT  50.544 0 50.568 0.084 ;
    END
  END i[343]
  PIN i[344]
    DIRECTION INPUT ;
    USE SIGNAL ;
    PORT
      LAYER M5 ;
        RECT  50.64 0 50.664 0.084 ;
    END
  END i[344]
  PIN i[345]
    DIRECTION INPUT ;
    USE SIGNAL ;
    PORT
      LAYER M5 ;
        RECT  50.736 0 50.76 0.084 ;
    END
  END i[345]
  PIN i[346]
    DIRECTION INPUT ;
    USE SIGNAL ;
    PORT
      LAYER M5 ;
        RECT  50.832 0 50.856 0.084 ;
    END
  END i[346]
  PIN i[347]
    DIRECTION INPUT ;
    USE SIGNAL ;
    PORT
      LAYER M5 ;
        RECT  50.928 0 50.952 0.084 ;
    END
  END i[347]
  PIN i[348]
    DIRECTION INPUT ;
    USE SIGNAL ;
    PORT
      LAYER M5 ;
        RECT  51.024 0 51.048 0.084 ;
    END
  END i[348]
  PIN i[349]
    DIRECTION INPUT ;
    USE SIGNAL ;
    PORT
      LAYER M5 ;
        RECT  51.12 0 51.144 0.084 ;
    END
  END i[349]
  PIN i[34]
    DIRECTION INPUT ;
    USE SIGNAL ;
    PORT
      LAYER M5 ;
        RECT  20.112 0 20.136 0.084 ;
    END
  END i[34]
  PIN i[350]
    DIRECTION INPUT ;
    USE SIGNAL ;
    PORT
      LAYER M5 ;
        RECT  51.216 0 51.24 0.084 ;
    END
  END i[350]
  PIN i[351]
    DIRECTION INPUT ;
    USE SIGNAL ;
    PORT
      LAYER M5 ;
        RECT  51.312 0 51.336 0.084 ;
    END
  END i[351]
  PIN i[352]
    DIRECTION INPUT ;
    USE SIGNAL ;
    PORT
      LAYER M5 ;
        RECT  51.408 0 51.432 0.084 ;
    END
  END i[352]
  PIN i[353]
    DIRECTION INPUT ;
    USE SIGNAL ;
    PORT
      LAYER M5 ;
        RECT  51.504 0 51.528 0.084 ;
    END
  END i[353]
  PIN i[354]
    DIRECTION INPUT ;
    USE SIGNAL ;
    PORT
      LAYER M5 ;
        RECT  51.6 0 51.624 0.084 ;
    END
  END i[354]
  PIN i[355]
    DIRECTION INPUT ;
    USE SIGNAL ;
    PORT
      LAYER M5 ;
        RECT  51.696 0 51.72 0.084 ;
    END
  END i[355]
  PIN i[356]
    DIRECTION INPUT ;
    USE SIGNAL ;
    PORT
      LAYER M5 ;
        RECT  51.792 0 51.816 0.084 ;
    END
  END i[356]
  PIN i[357]
    DIRECTION INPUT ;
    USE SIGNAL ;
    PORT
      LAYER M5 ;
        RECT  51.888 0 51.912 0.084 ;
    END
  END i[357]
  PIN i[358]
    DIRECTION INPUT ;
    USE SIGNAL ;
    PORT
      LAYER M5 ;
        RECT  51.984 0 52.008 0.084 ;
    END
  END i[358]
  PIN i[359]
    DIRECTION INPUT ;
    USE SIGNAL ;
    PORT
      LAYER M5 ;
        RECT  52.08 0 52.104 0.084 ;
    END
  END i[359]
  PIN i[35]
    DIRECTION INPUT ;
    USE SIGNAL ;
    PORT
      LAYER M5 ;
        RECT  20.208 0 20.232 0.084 ;
    END
  END i[35]
  PIN i[360]
    DIRECTION INPUT ;
    USE SIGNAL ;
    PORT
      LAYER M5 ;
        RECT  52.176 0 52.2 0.084 ;
    END
  END i[360]
  PIN i[361]
    DIRECTION INPUT ;
    USE SIGNAL ;
    PORT
      LAYER M5 ;
        RECT  52.272 0 52.296 0.084 ;
    END
  END i[361]
  PIN i[362]
    DIRECTION INPUT ;
    USE SIGNAL ;
    PORT
      LAYER M5 ;
        RECT  52.368 0 52.392 0.084 ;
    END
  END i[362]
  PIN i[363]
    DIRECTION INPUT ;
    USE SIGNAL ;
    PORT
      LAYER M5 ;
        RECT  52.464 0 52.488 0.084 ;
    END
  END i[363]
  PIN i[364]
    DIRECTION INPUT ;
    USE SIGNAL ;
    PORT
      LAYER M5 ;
        RECT  52.56 0 52.584 0.084 ;
    END
  END i[364]
  PIN i[365]
    DIRECTION INPUT ;
    USE SIGNAL ;
    PORT
      LAYER M5 ;
        RECT  52.656 0 52.68 0.084 ;
    END
  END i[365]
  PIN i[366]
    DIRECTION INPUT ;
    USE SIGNAL ;
    PORT
      LAYER M5 ;
        RECT  52.752 0 52.776 0.084 ;
    END
  END i[366]
  PIN i[367]
    DIRECTION INPUT ;
    USE SIGNAL ;
    PORT
      LAYER M5 ;
        RECT  52.848 0 52.872 0.084 ;
    END
  END i[367]
  PIN i[368]
    DIRECTION INPUT ;
    USE SIGNAL ;
    PORT
      LAYER M5 ;
        RECT  52.944 0 52.968 0.084 ;
    END
  END i[368]
  PIN i[369]
    DIRECTION INPUT ;
    USE SIGNAL ;
    PORT
      LAYER M5 ;
        RECT  53.04 0 53.064 0.084 ;
    END
  END i[369]
  PIN i[36]
    DIRECTION INPUT ;
    USE SIGNAL ;
    PORT
      LAYER M5 ;
        RECT  20.304 0 20.328 0.084 ;
    END
  END i[36]
  PIN i[370]
    DIRECTION INPUT ;
    USE SIGNAL ;
    PORT
      LAYER M5 ;
        RECT  53.136 0 53.16 0.084 ;
    END
  END i[370]
  PIN i[371]
    DIRECTION INPUT ;
    USE SIGNAL ;
    PORT
      LAYER M5 ;
        RECT  53.232 0 53.256 0.084 ;
    END
  END i[371]
  PIN i[372]
    DIRECTION INPUT ;
    USE SIGNAL ;
    PORT
      LAYER M5 ;
        RECT  53.328 0 53.352 0.084 ;
    END
  END i[372]
  PIN i[373]
    DIRECTION INPUT ;
    USE SIGNAL ;
    PORT
      LAYER M5 ;
        RECT  53.424 0 53.448 0.084 ;
    END
  END i[373]
  PIN i[374]
    DIRECTION INPUT ;
    USE SIGNAL ;
    PORT
      LAYER M5 ;
        RECT  53.52 0 53.544 0.084 ;
    END
  END i[374]
  PIN i[375]
    DIRECTION INPUT ;
    USE SIGNAL ;
    PORT
      LAYER M5 ;
        RECT  53.616 0 53.64 0.084 ;
    END
  END i[375]
  PIN i[376]
    DIRECTION INPUT ;
    USE SIGNAL ;
    PORT
      LAYER M5 ;
        RECT  53.712 0 53.736 0.084 ;
    END
  END i[376]
  PIN i[377]
    DIRECTION INPUT ;
    USE SIGNAL ;
    PORT
      LAYER M5 ;
        RECT  53.808 0 53.832 0.084 ;
    END
  END i[377]
  PIN i[378]
    DIRECTION INPUT ;
    USE SIGNAL ;
    PORT
      LAYER M5 ;
        RECT  53.904 0 53.928 0.084 ;
    END
  END i[378]
  PIN i[379]
    DIRECTION INPUT ;
    USE SIGNAL ;
    PORT
      LAYER M5 ;
        RECT  54 0 54.024 0.084 ;
    END
  END i[379]
  PIN i[37]
    DIRECTION INPUT ;
    USE SIGNAL ;
    PORT
      LAYER M5 ;
        RECT  20.4 0 20.424 0.084 ;
    END
  END i[37]
  PIN i[380]
    DIRECTION INPUT ;
    USE SIGNAL ;
    PORT
      LAYER M5 ;
        RECT  54.096 0 54.12 0.084 ;
    END
  END i[380]
  PIN i[381]
    DIRECTION INPUT ;
    USE SIGNAL ;
    PORT
      LAYER M5 ;
        RECT  54.192 0 54.216 0.084 ;
    END
  END i[381]
  PIN i[382]
    DIRECTION INPUT ;
    USE SIGNAL ;
    PORT
      LAYER M5 ;
        RECT  54.288 0 54.312 0.084 ;
    END
  END i[382]
  PIN i[383]
    DIRECTION INPUT ;
    USE SIGNAL ;
    PORT
      LAYER M5 ;
        RECT  54.384 0 54.408 0.084 ;
    END
  END i[383]
  PIN i[384]
    DIRECTION INPUT ;
    USE SIGNAL ;
    PORT
      LAYER M5 ;
        RECT  39.12 0 39.144 0.084 ;
    END
  END i[384]
  PIN i[385]
    DIRECTION INPUT ;
    USE SIGNAL ;
    PORT
      LAYER M5 ;
        RECT  39.216 0 39.24 0.084 ;
    END
  END i[385]
  PIN i[386]
    DIRECTION INPUT ;
    USE SIGNAL ;
    PORT
      LAYER M5 ;
        RECT  39.312 0 39.336 0.084 ;
    END
  END i[386]
  PIN i[387]
    DIRECTION INPUT ;
    USE SIGNAL ;
    PORT
      LAYER M5 ;
        RECT  39.408 0 39.432 0.084 ;
    END
  END i[387]
  PIN i[388]
    DIRECTION INPUT ;
    USE SIGNAL ;
    PORT
      LAYER M5 ;
        RECT  39.504 0 39.528 0.084 ;
    END
  END i[388]
  PIN i[389]
    DIRECTION INPUT ;
    USE SIGNAL ;
    PORT
      LAYER M5 ;
        RECT  39.6 0 39.624 0.084 ;
    END
  END i[389]
  PIN i[38]
    DIRECTION INPUT ;
    USE SIGNAL ;
    PORT
      LAYER M5 ;
        RECT  20.496 0 20.52 0.084 ;
    END
  END i[38]
  PIN i[390]
    DIRECTION INPUT ;
    USE SIGNAL ;
    PORT
      LAYER M5 ;
        RECT  39.696 0 39.72 0.084 ;
    END
  END i[390]
  PIN i[391]
    DIRECTION INPUT ;
    USE SIGNAL ;
    PORT
      LAYER M5 ;
        RECT  39.792 0 39.816 0.084 ;
    END
  END i[391]
  PIN i[392]
    DIRECTION INPUT ;
    USE SIGNAL ;
    PORT
      LAYER M5 ;
        RECT  39.888 0 39.912 0.084 ;
    END
  END i[392]
  PIN i[393]
    DIRECTION INPUT ;
    USE SIGNAL ;
    PORT
      LAYER M5 ;
        RECT  39.984 0 40.008 0.084 ;
    END
  END i[393]
  PIN i[394]
    DIRECTION INPUT ;
    USE SIGNAL ;
    PORT
      LAYER M5 ;
        RECT  40.08 0 40.104 0.084 ;
    END
  END i[394]
  PIN i[395]
    DIRECTION INPUT ;
    USE SIGNAL ;
    PORT
      LAYER M5 ;
        RECT  40.176 0 40.2 0.084 ;
    END
  END i[395]
  PIN i[396]
    DIRECTION INPUT ;
    USE SIGNAL ;
    PORT
      LAYER M5 ;
        RECT  40.272 0 40.296 0.084 ;
    END
  END i[396]
  PIN i[397]
    DIRECTION INPUT ;
    USE SIGNAL ;
    PORT
      LAYER M5 ;
        RECT  40.368 0 40.392 0.084 ;
    END
  END i[397]
  PIN i[398]
    DIRECTION INPUT ;
    USE SIGNAL ;
    PORT
      LAYER M5 ;
        RECT  40.464 0 40.488 0.084 ;
    END
  END i[398]
  PIN i[399]
    DIRECTION INPUT ;
    USE SIGNAL ;
    PORT
      LAYER M5 ;
        RECT  40.56 0 40.584 0.084 ;
    END
  END i[399]
  PIN i[39]
    DIRECTION INPUT ;
    USE SIGNAL ;
    PORT
      LAYER M5 ;
        RECT  20.592 0 20.616 0.084 ;
    END
  END i[39]
  PIN i[3]
    DIRECTION INPUT ;
    USE SIGNAL ;
    PORT
      LAYER M5 ;
        RECT  23.28 0 23.304 0.084 ;
    END
  END i[3]
  PIN i[400]
    DIRECTION INPUT ;
    USE SIGNAL ;
    PORT
      LAYER M5 ;
        RECT  40.656 0 40.68 0.084 ;
    END
  END i[400]
  PIN i[401]
    DIRECTION INPUT ;
    USE SIGNAL ;
    PORT
      LAYER M5 ;
        RECT  40.752 0 40.776 0.084 ;
    END
  END i[401]
  PIN i[402]
    DIRECTION INPUT ;
    USE SIGNAL ;
    PORT
      LAYER M5 ;
        RECT  40.848 0 40.872 0.084 ;
    END
  END i[402]
  PIN i[403]
    DIRECTION INPUT ;
    USE SIGNAL ;
    PORT
      LAYER M5 ;
        RECT  40.944 0 40.968 0.084 ;
    END
  END i[403]
  PIN i[404]
    DIRECTION INPUT ;
    USE SIGNAL ;
    PORT
      LAYER M5 ;
        RECT  41.04 0 41.064 0.084 ;
    END
  END i[404]
  PIN i[405]
    DIRECTION INPUT ;
    USE SIGNAL ;
    PORT
      LAYER M5 ;
        RECT  41.136 0 41.16 0.084 ;
    END
  END i[405]
  PIN i[406]
    DIRECTION INPUT ;
    USE SIGNAL ;
    PORT
      LAYER M5 ;
        RECT  41.232 0 41.256 0.084 ;
    END
  END i[406]
  PIN i[407]
    DIRECTION INPUT ;
    USE SIGNAL ;
    PORT
      LAYER M5 ;
        RECT  41.328 0 41.352 0.084 ;
    END
  END i[407]
  PIN i[408]
    DIRECTION INPUT ;
    USE SIGNAL ;
    PORT
      LAYER M5 ;
        RECT  41.424 0 41.448 0.084 ;
    END
  END i[408]
  PIN i[409]
    DIRECTION INPUT ;
    USE SIGNAL ;
    PORT
      LAYER M5 ;
        RECT  41.52 0 41.544 0.084 ;
    END
  END i[409]
  PIN i[40]
    DIRECTION INPUT ;
    USE SIGNAL ;
    PORT
      LAYER M5 ;
        RECT  20.688 0 20.712 0.084 ;
    END
  END i[40]
  PIN i[410]
    DIRECTION INPUT ;
    USE SIGNAL ;
    PORT
      LAYER M5 ;
        RECT  41.616 0 41.64 0.084 ;
    END
  END i[410]
  PIN i[411]
    DIRECTION INPUT ;
    USE SIGNAL ;
    PORT
      LAYER M5 ;
        RECT  41.712 0 41.736 0.084 ;
    END
  END i[411]
  PIN i[412]
    DIRECTION INPUT ;
    USE SIGNAL ;
    PORT
      LAYER M5 ;
        RECT  41.808 0 41.832 0.084 ;
    END
  END i[412]
  PIN i[413]
    DIRECTION INPUT ;
    USE SIGNAL ;
    PORT
      LAYER M5 ;
        RECT  41.904 0 41.928 0.084 ;
    END
  END i[413]
  PIN i[414]
    DIRECTION INPUT ;
    USE SIGNAL ;
    PORT
      LAYER M5 ;
        RECT  42 0 42.024 0.084 ;
    END
  END i[414]
  PIN i[415]
    DIRECTION INPUT ;
    USE SIGNAL ;
    PORT
      LAYER M5 ;
        RECT  42.096 0 42.12 0.084 ;
    END
  END i[415]
  PIN i[416]
    DIRECTION INPUT ;
    USE SIGNAL ;
    PORT
      LAYER M5 ;
        RECT  42.192 0 42.216 0.084 ;
    END
  END i[416]
  PIN i[417]
    DIRECTION INPUT ;
    USE SIGNAL ;
    PORT
      LAYER M5 ;
        RECT  42.288 0 42.312 0.084 ;
    END
  END i[417]
  PIN i[418]
    DIRECTION INPUT ;
    USE SIGNAL ;
    PORT
      LAYER M5 ;
        RECT  42.384 0 42.408 0.084 ;
    END
  END i[418]
  PIN i[419]
    DIRECTION INPUT ;
    USE SIGNAL ;
    PORT
      LAYER M5 ;
        RECT  42.48 0 42.504 0.084 ;
    END
  END i[419]
  PIN i[41]
    DIRECTION INPUT ;
    USE SIGNAL ;
    PORT
      LAYER M5 ;
        RECT  20.784 0 20.808 0.084 ;
    END
  END i[41]
  PIN i[420]
    DIRECTION INPUT ;
    USE SIGNAL ;
    PORT
      LAYER M5 ;
        RECT  42.576 0 42.6 0.084 ;
    END
  END i[420]
  PIN i[421]
    DIRECTION INPUT ;
    USE SIGNAL ;
    PORT
      LAYER M5 ;
        RECT  42.672 0 42.696 0.084 ;
    END
  END i[421]
  PIN i[422]
    DIRECTION INPUT ;
    USE SIGNAL ;
    PORT
      LAYER M5 ;
        RECT  42.768 0 42.792 0.084 ;
    END
  END i[422]
  PIN i[423]
    DIRECTION INPUT ;
    USE SIGNAL ;
    PORT
      LAYER M5 ;
        RECT  42.864 0 42.888 0.084 ;
    END
  END i[423]
  PIN i[424]
    DIRECTION INPUT ;
    USE SIGNAL ;
    PORT
      LAYER M5 ;
        RECT  42.96 0 42.984 0.084 ;
    END
  END i[424]
  PIN i[425]
    DIRECTION INPUT ;
    USE SIGNAL ;
    PORT
      LAYER M5 ;
        RECT  43.056 0 43.08 0.084 ;
    END
  END i[425]
  PIN i[426]
    DIRECTION INPUT ;
    USE SIGNAL ;
    PORT
      LAYER M5 ;
        RECT  43.152 0 43.176 0.084 ;
    END
  END i[426]
  PIN i[427]
    DIRECTION INPUT ;
    USE SIGNAL ;
    PORT
      LAYER M5 ;
        RECT  43.248 0 43.272 0.084 ;
    END
  END i[427]
  PIN i[428]
    DIRECTION INPUT ;
    USE SIGNAL ;
    PORT
      LAYER M5 ;
        RECT  43.344 0 43.368 0.084 ;
    END
  END i[428]
  PIN i[429]
    DIRECTION INPUT ;
    USE SIGNAL ;
    PORT
      LAYER M5 ;
        RECT  43.44 0 43.464 0.084 ;
    END
  END i[429]
  PIN i[42]
    DIRECTION INPUT ;
    USE SIGNAL ;
    PORT
      LAYER M5 ;
        RECT  20.88 0 20.904 0.084 ;
    END
  END i[42]
  PIN i[430]
    DIRECTION INPUT ;
    USE SIGNAL ;
    PORT
      LAYER M5 ;
        RECT  43.536 0 43.56 0.084 ;
    END
  END i[430]
  PIN i[431]
    DIRECTION INPUT ;
    USE SIGNAL ;
    PORT
      LAYER M5 ;
        RECT  43.632 0 43.656 0.084 ;
    END
  END i[431]
  PIN i[432]
    DIRECTION INPUT ;
    USE SIGNAL ;
    PORT
      LAYER M5 ;
        RECT  43.728 0 43.752 0.084 ;
    END
  END i[432]
  PIN i[433]
    DIRECTION INPUT ;
    USE SIGNAL ;
    PORT
      LAYER M5 ;
        RECT  43.824 0 43.848 0.084 ;
    END
  END i[433]
  PIN i[434]
    DIRECTION INPUT ;
    USE SIGNAL ;
    PORT
      LAYER M5 ;
        RECT  43.92 0 43.944 0.084 ;
    END
  END i[434]
  PIN i[435]
    DIRECTION INPUT ;
    USE SIGNAL ;
    PORT
      LAYER M5 ;
        RECT  44.016 0 44.04 0.084 ;
    END
  END i[435]
  PIN i[436]
    DIRECTION INPUT ;
    USE SIGNAL ;
    PORT
      LAYER M5 ;
        RECT  44.112 0 44.136 0.084 ;
    END
  END i[436]
  PIN i[437]
    DIRECTION INPUT ;
    USE SIGNAL ;
    PORT
      LAYER M5 ;
        RECT  44.208 0 44.232 0.084 ;
    END
  END i[437]
  PIN i[438]
    DIRECTION INPUT ;
    USE SIGNAL ;
    PORT
      LAYER M5 ;
        RECT  44.304 0 44.328 0.084 ;
    END
  END i[438]
  PIN i[439]
    DIRECTION INPUT ;
    USE SIGNAL ;
    PORT
      LAYER M5 ;
        RECT  44.4 0 44.424 0.084 ;
    END
  END i[439]
  PIN i[43]
    DIRECTION INPUT ;
    USE SIGNAL ;
    PORT
      LAYER M5 ;
        RECT  20.976 0 21 0.084 ;
    END
  END i[43]
  PIN i[440]
    DIRECTION INPUT ;
    USE SIGNAL ;
    PORT
      LAYER M5 ;
        RECT  44.496 0 44.52 0.084 ;
    END
  END i[440]
  PIN i[441]
    DIRECTION INPUT ;
    USE SIGNAL ;
    PORT
      LAYER M5 ;
        RECT  44.592 0 44.616 0.084 ;
    END
  END i[441]
  PIN i[442]
    DIRECTION INPUT ;
    USE SIGNAL ;
    PORT
      LAYER M5 ;
        RECT  44.688 0 44.712 0.084 ;
    END
  END i[442]
  PIN i[443]
    DIRECTION INPUT ;
    USE SIGNAL ;
    PORT
      LAYER M5 ;
        RECT  44.784 0 44.808 0.084 ;
    END
  END i[443]
  PIN i[444]
    DIRECTION INPUT ;
    USE SIGNAL ;
    PORT
      LAYER M5 ;
        RECT  44.88 0 44.904 0.084 ;
    END
  END i[444]
  PIN i[445]
    DIRECTION INPUT ;
    USE SIGNAL ;
    PORT
      LAYER M5 ;
        RECT  44.976 0 45 0.084 ;
    END
  END i[445]
  PIN i[446]
    DIRECTION INPUT ;
    USE SIGNAL ;
    PORT
      LAYER M5 ;
        RECT  45.072 0 45.096 0.084 ;
    END
  END i[446]
  PIN i[447]
    DIRECTION INPUT ;
    USE SIGNAL ;
    PORT
      LAYER M5 ;
        RECT  45.168 0 45.192 0.084 ;
    END
  END i[447]
  PIN i[448]
    DIRECTION INPUT ;
    USE SIGNAL ;
    PORT
      LAYER M5 ;
        RECT  9.936 0 9.96 0.084 ;
    END
  END i[448]
  PIN i[449]
    DIRECTION INPUT ;
    USE SIGNAL ;
    PORT
      LAYER M5 ;
        RECT  10.032 0 10.056 0.084 ;
    END
  END i[449]
  PIN i[44]
    DIRECTION INPUT ;
    USE SIGNAL ;
    PORT
      LAYER M5 ;
        RECT  21.072 0 21.096 0.084 ;
    END
  END i[44]
  PIN i[450]
    DIRECTION INPUT ;
    USE SIGNAL ;
    PORT
      LAYER M5 ;
        RECT  10.128 0 10.152 0.084 ;
    END
  END i[450]
  PIN i[451]
    DIRECTION INPUT ;
    USE SIGNAL ;
    PORT
      LAYER M5 ;
        RECT  10.224 0 10.248 0.084 ;
    END
  END i[451]
  PIN i[452]
    DIRECTION INPUT ;
    USE SIGNAL ;
    PORT
      LAYER M5 ;
        RECT  10.32 0 10.344 0.084 ;
    END
  END i[452]
  PIN i[453]
    DIRECTION INPUT ;
    USE SIGNAL ;
    PORT
      LAYER M5 ;
        RECT  10.416 0 10.44 0.084 ;
    END
  END i[453]
  PIN i[454]
    DIRECTION INPUT ;
    USE SIGNAL ;
    PORT
      LAYER M5 ;
        RECT  10.512 0 10.536 0.084 ;
    END
  END i[454]
  PIN i[455]
    DIRECTION INPUT ;
    USE SIGNAL ;
    PORT
      LAYER M5 ;
        RECT  10.608 0 10.632 0.084 ;
    END
  END i[455]
  PIN i[456]
    DIRECTION INPUT ;
    USE SIGNAL ;
    PORT
      LAYER M5 ;
        RECT  10.704 0 10.728 0.084 ;
    END
  END i[456]
  PIN i[457]
    DIRECTION INPUT ;
    USE SIGNAL ;
    PORT
      LAYER M5 ;
        RECT  10.8 0 10.824 0.084 ;
    END
  END i[457]
  PIN i[458]
    DIRECTION INPUT ;
    USE SIGNAL ;
    PORT
      LAYER M5 ;
        RECT  10.896 0 10.92 0.084 ;
    END
  END i[458]
  PIN i[459]
    DIRECTION INPUT ;
    USE SIGNAL ;
    PORT
      LAYER M5 ;
        RECT  10.992 0 11.016 0.084 ;
    END
  END i[459]
  PIN i[45]
    DIRECTION INPUT ;
    USE SIGNAL ;
    PORT
      LAYER M5 ;
        RECT  21.168 0 21.192 0.084 ;
    END
  END i[45]
  PIN i[460]
    DIRECTION INPUT ;
    USE SIGNAL ;
    PORT
      LAYER M5 ;
        RECT  11.088 0 11.112 0.084 ;
    END
  END i[460]
  PIN i[461]
    DIRECTION INPUT ;
    USE SIGNAL ;
    PORT
      LAYER M5 ;
        RECT  11.184 0 11.208 0.084 ;
    END
  END i[461]
  PIN i[462]
    DIRECTION INPUT ;
    USE SIGNAL ;
    PORT
      LAYER M5 ;
        RECT  11.28 0 11.304 0.084 ;
    END
  END i[462]
  PIN i[463]
    DIRECTION INPUT ;
    USE SIGNAL ;
    PORT
      LAYER M5 ;
        RECT  11.376 0 11.4 0.084 ;
    END
  END i[463]
  PIN i[464]
    DIRECTION INPUT ;
    USE SIGNAL ;
    PORT
      LAYER M5 ;
        RECT  11.472 0 11.496 0.084 ;
    END
  END i[464]
  PIN i[465]
    DIRECTION INPUT ;
    USE SIGNAL ;
    PORT
      LAYER M5 ;
        RECT  11.568 0 11.592 0.084 ;
    END
  END i[465]
  PIN i[466]
    DIRECTION INPUT ;
    USE SIGNAL ;
    PORT
      LAYER M5 ;
        RECT  11.664 0 11.688 0.084 ;
    END
  END i[466]
  PIN i[467]
    DIRECTION INPUT ;
    USE SIGNAL ;
    PORT
      LAYER M5 ;
        RECT  11.76 0 11.784 0.084 ;
    END
  END i[467]
  PIN i[468]
    DIRECTION INPUT ;
    USE SIGNAL ;
    PORT
      LAYER M5 ;
        RECT  11.856 0 11.88 0.084 ;
    END
  END i[468]
  PIN i[469]
    DIRECTION INPUT ;
    USE SIGNAL ;
    PORT
      LAYER M5 ;
        RECT  11.952 0 11.976 0.084 ;
    END
  END i[469]
  PIN i[46]
    DIRECTION INPUT ;
    USE SIGNAL ;
    PORT
      LAYER M5 ;
        RECT  21.264 0 21.288 0.084 ;
    END
  END i[46]
  PIN i[470]
    DIRECTION INPUT ;
    USE SIGNAL ;
    PORT
      LAYER M5 ;
        RECT  12.048 0 12.072 0.084 ;
    END
  END i[470]
  PIN i[471]
    DIRECTION INPUT ;
    USE SIGNAL ;
    PORT
      LAYER M5 ;
        RECT  12.144 0 12.168 0.084 ;
    END
  END i[471]
  PIN i[472]
    DIRECTION INPUT ;
    USE SIGNAL ;
    PORT
      LAYER M5 ;
        RECT  12.24 0 12.264 0.084 ;
    END
  END i[472]
  PIN i[473]
    DIRECTION INPUT ;
    USE SIGNAL ;
    PORT
      LAYER M5 ;
        RECT  12.336 0 12.36 0.084 ;
    END
  END i[473]
  PIN i[474]
    DIRECTION INPUT ;
    USE SIGNAL ;
    PORT
      LAYER M5 ;
        RECT  12.432 0 12.456 0.084 ;
    END
  END i[474]
  PIN i[475]
    DIRECTION INPUT ;
    USE SIGNAL ;
    PORT
      LAYER M5 ;
        RECT  12.528 0 12.552 0.084 ;
    END
  END i[475]
  PIN i[476]
    DIRECTION INPUT ;
    USE SIGNAL ;
    PORT
      LAYER M5 ;
        RECT  12.624 0 12.648 0.084 ;
    END
  END i[476]
  PIN i[477]
    DIRECTION INPUT ;
    USE SIGNAL ;
    PORT
      LAYER M5 ;
        RECT  12.72 0 12.744 0.084 ;
    END
  END i[477]
  PIN i[478]
    DIRECTION INPUT ;
    USE SIGNAL ;
    PORT
      LAYER M5 ;
        RECT  12.816 0 12.84 0.084 ;
    END
  END i[478]
  PIN i[479]
    DIRECTION INPUT ;
    USE SIGNAL ;
    PORT
      LAYER M5 ;
        RECT  12.912 0 12.936 0.084 ;
    END
  END i[479]
  PIN i[47]
    DIRECTION INPUT ;
    USE SIGNAL ;
    PORT
      LAYER M5 ;
        RECT  21.36 0 21.384 0.084 ;
    END
  END i[47]
  PIN i[480]
    DIRECTION INPUT ;
    USE SIGNAL ;
    PORT
      LAYER M5 ;
        RECT  58.32 0 58.344 0.084 ;
    END
  END i[480]
  PIN i[481]
    DIRECTION INPUT ;
    USE SIGNAL ;
    PORT
      LAYER M5 ;
        RECT  58.416 0 58.44 0.084 ;
    END
  END i[481]
  PIN i[482]
    DIRECTION INPUT ;
    USE SIGNAL ;
    PORT
      LAYER M5 ;
        RECT  58.512 0 58.536 0.084 ;
    END
  END i[482]
  PIN i[483]
    DIRECTION INPUT ;
    USE SIGNAL ;
    PORT
      LAYER M5 ;
        RECT  58.608 0 58.632 0.084 ;
    END
  END i[483]
  PIN i[484]
    DIRECTION INPUT ;
    USE SIGNAL ;
    PORT
      LAYER M5 ;
        RECT  58.704 0 58.728 0.084 ;
    END
  END i[484]
  PIN i[485]
    DIRECTION INPUT ;
    USE SIGNAL ;
    PORT
      LAYER M5 ;
        RECT  58.8 0 58.824 0.084 ;
    END
  END i[485]
  PIN i[486]
    DIRECTION INPUT ;
    USE SIGNAL ;
    PORT
      LAYER M5 ;
        RECT  58.896 0 58.92 0.084 ;
    END
  END i[486]
  PIN i[487]
    DIRECTION INPUT ;
    USE SIGNAL ;
    PORT
      LAYER M5 ;
        RECT  58.992 0 59.016 0.084 ;
    END
  END i[487]
  PIN i[488]
    DIRECTION INPUT ;
    USE SIGNAL ;
    PORT
      LAYER M5 ;
        RECT  59.088 0 59.112 0.084 ;
    END
  END i[488]
  PIN i[489]
    DIRECTION INPUT ;
    USE SIGNAL ;
    PORT
      LAYER M5 ;
        RECT  59.184 0 59.208 0.084 ;
    END
  END i[489]
  PIN i[48]
    DIRECTION INPUT ;
    USE SIGNAL ;
    PORT
      LAYER M5 ;
        RECT  21.456 0 21.48 0.084 ;
    END
  END i[48]
  PIN i[490]
    DIRECTION INPUT ;
    USE SIGNAL ;
    PORT
      LAYER M5 ;
        RECT  59.28 0 59.304 0.084 ;
    END
  END i[490]
  PIN i[491]
    DIRECTION INPUT ;
    USE SIGNAL ;
    PORT
      LAYER M5 ;
        RECT  59.376 0 59.4 0.084 ;
    END
  END i[491]
  PIN i[492]
    DIRECTION INPUT ;
    USE SIGNAL ;
    PORT
      LAYER M5 ;
        RECT  59.472 0 59.496 0.084 ;
    END
  END i[492]
  PIN i[493]
    DIRECTION INPUT ;
    USE SIGNAL ;
    PORT
      LAYER M5 ;
        RECT  59.568 0 59.592 0.084 ;
    END
  END i[493]
  PIN i[494]
    DIRECTION INPUT ;
    USE SIGNAL ;
    PORT
      LAYER M5 ;
        RECT  59.664 0 59.688 0.084 ;
    END
  END i[494]
  PIN i[495]
    DIRECTION INPUT ;
    USE SIGNAL ;
    PORT
      LAYER M5 ;
        RECT  59.76 0 59.784 0.084 ;
    END
  END i[495]
  PIN i[496]
    DIRECTION INPUT ;
    USE SIGNAL ;
    PORT
      LAYER M5 ;
        RECT  59.856 0 59.88 0.084 ;
    END
  END i[496]
  PIN i[497]
    DIRECTION INPUT ;
    USE SIGNAL ;
    PORT
      LAYER M5 ;
        RECT  59.952 0 59.976 0.084 ;
    END
  END i[497]
  PIN i[498]
    DIRECTION INPUT ;
    USE SIGNAL ;
    PORT
      LAYER M5 ;
        RECT  60.048 0 60.072 0.084 ;
    END
  END i[498]
  PIN i[499]
    DIRECTION INPUT ;
    USE SIGNAL ;
    PORT
      LAYER M5 ;
        RECT  60.144 0 60.168 0.084 ;
    END
  END i[499]
  PIN i[49]
    DIRECTION INPUT ;
    USE SIGNAL ;
    PORT
      LAYER M5 ;
        RECT  21.552 0 21.576 0.084 ;
    END
  END i[49]
  PIN i[4]
    DIRECTION INPUT ;
    USE SIGNAL ;
    PORT
      LAYER M5 ;
        RECT  23.376 0 23.4 0.084 ;
    END
  END i[4]
  PIN i[500]
    DIRECTION INPUT ;
    USE SIGNAL ;
    PORT
      LAYER M5 ;
        RECT  60.24 0 60.264 0.084 ;
    END
  END i[500]
  PIN i[501]
    DIRECTION INPUT ;
    USE SIGNAL ;
    PORT
      LAYER M5 ;
        RECT  60.336 0 60.36 0.084 ;
    END
  END i[501]
  PIN i[502]
    DIRECTION INPUT ;
    USE SIGNAL ;
    PORT
      LAYER M5 ;
        RECT  60.432 0 60.456 0.084 ;
    END
  END i[502]
  PIN i[503]
    DIRECTION INPUT ;
    USE SIGNAL ;
    PORT
      LAYER M5 ;
        RECT  60.528 0 60.552 0.084 ;
    END
  END i[503]
  PIN i[504]
    DIRECTION INPUT ;
    USE SIGNAL ;
    PORT
      LAYER M5 ;
        RECT  60.624 0 60.648 0.084 ;
    END
  END i[504]
  PIN i[505]
    DIRECTION INPUT ;
    USE SIGNAL ;
    PORT
      LAYER M5 ;
        RECT  60.72 0 60.744 0.084 ;
    END
  END i[505]
  PIN i[506]
    DIRECTION INPUT ;
    USE SIGNAL ;
    PORT
      LAYER M5 ;
        RECT  60.816 0 60.84 0.084 ;
    END
  END i[506]
  PIN i[507]
    DIRECTION INPUT ;
    USE SIGNAL ;
    PORT
      LAYER M5 ;
        RECT  60.912 0 60.936 0.084 ;
    END
  END i[507]
  PIN i[508]
    DIRECTION INPUT ;
    USE SIGNAL ;
    PORT
      LAYER M5 ;
        RECT  61.008 0 61.032 0.084 ;
    END
  END i[508]
  PIN i[509]
    DIRECTION INPUT ;
    USE SIGNAL ;
    PORT
      LAYER M5 ;
        RECT  61.104 0 61.128 0.084 ;
    END
  END i[509]
  PIN i[50]
    DIRECTION INPUT ;
    USE SIGNAL ;
    PORT
      LAYER M5 ;
        RECT  21.648 0 21.672 0.084 ;
    END
  END i[50]
  PIN i[510]
    DIRECTION INPUT ;
    USE SIGNAL ;
    PORT
      LAYER M5 ;
        RECT  61.2 0 61.224 0.084 ;
    END
  END i[510]
  PIN i[511]
    DIRECTION INPUT ;
    USE SIGNAL ;
    PORT
      LAYER M5 ;
        RECT  61.296 0 61.32 0.084 ;
    END
  END i[511]
  PIN i[512]
    DIRECTION INPUT ;
    USE SIGNAL ;
    PORT
      LAYER M5 ;
        RECT  3.792 0 3.816 0.084 ;
    END
  END i[512]
  PIN i[513]
    DIRECTION INPUT ;
    USE SIGNAL ;
    PORT
      LAYER M5 ;
        RECT  3.888 0 3.912 0.084 ;
    END
  END i[513]
  PIN i[514]
    DIRECTION INPUT ;
    USE SIGNAL ;
    PORT
      LAYER M5 ;
        RECT  3.984 0 4.008 0.084 ;
    END
  END i[514]
  PIN i[515]
    DIRECTION INPUT ;
    USE SIGNAL ;
    PORT
      LAYER M5 ;
        RECT  4.08 0 4.104 0.084 ;
    END
  END i[515]
  PIN i[516]
    DIRECTION INPUT ;
    USE SIGNAL ;
    PORT
      LAYER M5 ;
        RECT  4.176 0 4.2 0.084 ;
    END
  END i[516]
  PIN i[517]
    DIRECTION INPUT ;
    USE SIGNAL ;
    PORT
      LAYER M5 ;
        RECT  4.272 0 4.296 0.084 ;
    END
  END i[517]
  PIN i[518]
    DIRECTION INPUT ;
    USE SIGNAL ;
    PORT
      LAYER M5 ;
        RECT  4.368 0 4.392 0.084 ;
    END
  END i[518]
  PIN i[519]
    DIRECTION INPUT ;
    USE SIGNAL ;
    PORT
      LAYER M5 ;
        RECT  4.464 0 4.488 0.084 ;
    END
  END i[519]
  PIN i[51]
    DIRECTION INPUT ;
    USE SIGNAL ;
    PORT
      LAYER M5 ;
        RECT  21.744 0 21.768 0.084 ;
    END
  END i[51]
  PIN i[520]
    DIRECTION INPUT ;
    USE SIGNAL ;
    PORT
      LAYER M5 ;
        RECT  4.56 0 4.584 0.084 ;
    END
  END i[520]
  PIN i[521]
    DIRECTION INPUT ;
    USE SIGNAL ;
    PORT
      LAYER M5 ;
        RECT  4.656 0 4.68 0.084 ;
    END
  END i[521]
  PIN i[522]
    DIRECTION INPUT ;
    USE SIGNAL ;
    PORT
      LAYER M5 ;
        RECT  4.752 0 4.776 0.084 ;
    END
  END i[522]
  PIN i[523]
    DIRECTION INPUT ;
    USE SIGNAL ;
    PORT
      LAYER M5 ;
        RECT  4.848 0 4.872 0.084 ;
    END
  END i[523]
  PIN i[524]
    DIRECTION INPUT ;
    USE SIGNAL ;
    PORT
      LAYER M5 ;
        RECT  4.944 0 4.968 0.084 ;
    END
  END i[524]
  PIN i[525]
    DIRECTION INPUT ;
    USE SIGNAL ;
    PORT
      LAYER M5 ;
        RECT  5.04 0 5.064 0.084 ;
    END
  END i[525]
  PIN i[526]
    DIRECTION INPUT ;
    USE SIGNAL ;
    PORT
      LAYER M5 ;
        RECT  5.136 0 5.16 0.084 ;
    END
  END i[526]
  PIN i[527]
    DIRECTION INPUT ;
    USE SIGNAL ;
    PORT
      LAYER M5 ;
        RECT  5.232 0 5.256 0.084 ;
    END
  END i[527]
  PIN i[528]
    DIRECTION INPUT ;
    USE SIGNAL ;
    PORT
      LAYER M5 ;
        RECT  5.328 0 5.352 0.084 ;
    END
  END i[528]
  PIN i[529]
    DIRECTION INPUT ;
    USE SIGNAL ;
    PORT
      LAYER M5 ;
        RECT  5.424 0 5.448 0.084 ;
    END
  END i[529]
  PIN i[52]
    DIRECTION INPUT ;
    USE SIGNAL ;
    PORT
      LAYER M5 ;
        RECT  21.84 0 21.864 0.084 ;
    END
  END i[52]
  PIN i[530]
    DIRECTION INPUT ;
    USE SIGNAL ;
    PORT
      LAYER M5 ;
        RECT  5.52 0 5.544 0.084 ;
    END
  END i[530]
  PIN i[531]
    DIRECTION INPUT ;
    USE SIGNAL ;
    PORT
      LAYER M5 ;
        RECT  5.616 0 5.64 0.084 ;
    END
  END i[531]
  PIN i[532]
    DIRECTION INPUT ;
    USE SIGNAL ;
    PORT
      LAYER M5 ;
        RECT  5.712 0 5.736 0.084 ;
    END
  END i[532]
  PIN i[533]
    DIRECTION INPUT ;
    USE SIGNAL ;
    PORT
      LAYER M5 ;
        RECT  5.808 0 5.832 0.084 ;
    END
  END i[533]
  PIN i[534]
    DIRECTION INPUT ;
    USE SIGNAL ;
    PORT
      LAYER M5 ;
        RECT  5.904 0 5.928 0.084 ;
    END
  END i[534]
  PIN i[535]
    DIRECTION INPUT ;
    USE SIGNAL ;
    PORT
      LAYER M5 ;
        RECT  6 0 6.024 0.084 ;
    END
  END i[535]
  PIN i[536]
    DIRECTION INPUT ;
    USE SIGNAL ;
    PORT
      LAYER M5 ;
        RECT  6.096 0 6.12 0.084 ;
    END
  END i[536]
  PIN i[537]
    DIRECTION INPUT ;
    USE SIGNAL ;
    PORT
      LAYER M5 ;
        RECT  6.192 0 6.216 0.084 ;
    END
  END i[537]
  PIN i[538]
    DIRECTION INPUT ;
    USE SIGNAL ;
    PORT
      LAYER M5 ;
        RECT  6.288 0 6.312 0.084 ;
    END
  END i[538]
  PIN i[539]
    DIRECTION INPUT ;
    USE SIGNAL ;
    PORT
      LAYER M5 ;
        RECT  6.384 0 6.408 0.084 ;
    END
  END i[539]
  PIN i[53]
    DIRECTION INPUT ;
    USE SIGNAL ;
    PORT
      LAYER M5 ;
        RECT  21.936 0 21.96 0.084 ;
    END
  END i[53]
  PIN i[540]
    DIRECTION INPUT ;
    USE SIGNAL ;
    PORT
      LAYER M5 ;
        RECT  6.48 0 6.504 0.084 ;
    END
  END i[540]
  PIN i[541]
    DIRECTION INPUT ;
    USE SIGNAL ;
    PORT
      LAYER M5 ;
        RECT  6.576 0 6.6 0.084 ;
    END
  END i[541]
  PIN i[542]
    DIRECTION INPUT ;
    USE SIGNAL ;
    PORT
      LAYER M5 ;
        RECT  6.672 0 6.696 0.084 ;
    END
  END i[542]
  PIN i[543]
    DIRECTION INPUT ;
    USE SIGNAL ;
    PORT
      LAYER M5 ;
        RECT  6.768 0 6.792 0.084 ;
    END
  END i[543]
  PIN i[544]
    DIRECTION INPUT ;
    USE SIGNAL ;
    PORT
      LAYER M5 ;
        RECT  16.08 0 16.104 0.084 ;
    END
  END i[544]
  PIN i[545]
    DIRECTION INPUT ;
    USE SIGNAL ;
    PORT
      LAYER M5 ;
        RECT  16.176 0 16.2 0.084 ;
    END
  END i[545]
  PIN i[546]
    DIRECTION INPUT ;
    USE SIGNAL ;
    PORT
      LAYER M5 ;
        RECT  16.272 0 16.296 0.084 ;
    END
  END i[546]
  PIN i[547]
    DIRECTION INPUT ;
    USE SIGNAL ;
    PORT
      LAYER M5 ;
        RECT  16.368 0 16.392 0.084 ;
    END
  END i[547]
  PIN i[548]
    DIRECTION INPUT ;
    USE SIGNAL ;
    PORT
      LAYER M5 ;
        RECT  16.464 0 16.488 0.084 ;
    END
  END i[548]
  PIN i[549]
    DIRECTION INPUT ;
    USE SIGNAL ;
    PORT
      LAYER M5 ;
        RECT  16.56 0 16.584 0.084 ;
    END
  END i[549]
  PIN i[54]
    DIRECTION INPUT ;
    USE SIGNAL ;
    PORT
      LAYER M5 ;
        RECT  22.032 0 22.056 0.084 ;
    END
  END i[54]
  PIN i[550]
    DIRECTION INPUT ;
    USE SIGNAL ;
    PORT
      LAYER M5 ;
        RECT  16.656 0 16.68 0.084 ;
    END
  END i[550]
  PIN i[551]
    DIRECTION INPUT ;
    USE SIGNAL ;
    PORT
      LAYER M5 ;
        RECT  16.752 0 16.776 0.084 ;
    END
  END i[551]
  PIN i[552]
    DIRECTION INPUT ;
    USE SIGNAL ;
    PORT
      LAYER M5 ;
        RECT  16.848 0 16.872 0.084 ;
    END
  END i[552]
  PIN i[553]
    DIRECTION INPUT ;
    USE SIGNAL ;
    PORT
      LAYER M5 ;
        RECT  16.944 0 16.968 0.084 ;
    END
  END i[553]
  PIN i[554]
    DIRECTION INPUT ;
    USE SIGNAL ;
    PORT
      LAYER M5 ;
        RECT  17.04 0 17.064 0.084 ;
    END
  END i[554]
  PIN i[555]
    DIRECTION INPUT ;
    USE SIGNAL ;
    PORT
      LAYER M5 ;
        RECT  17.136 0 17.16 0.084 ;
    END
  END i[555]
  PIN i[556]
    DIRECTION INPUT ;
    USE SIGNAL ;
    PORT
      LAYER M5 ;
        RECT  17.232 0 17.256 0.084 ;
    END
  END i[556]
  PIN i[557]
    DIRECTION INPUT ;
    USE SIGNAL ;
    PORT
      LAYER M5 ;
        RECT  17.328 0 17.352 0.084 ;
    END
  END i[557]
  PIN i[558]
    DIRECTION INPUT ;
    USE SIGNAL ;
    PORT
      LAYER M5 ;
        RECT  17.424 0 17.448 0.084 ;
    END
  END i[558]
  PIN i[559]
    DIRECTION INPUT ;
    USE SIGNAL ;
    PORT
      LAYER M5 ;
        RECT  17.52 0 17.544 0.084 ;
    END
  END i[559]
  PIN i[55]
    DIRECTION INPUT ;
    USE SIGNAL ;
    PORT
      LAYER M5 ;
        RECT  22.128 0 22.152 0.084 ;
    END
  END i[55]
  PIN i[560]
    DIRECTION INPUT ;
    USE SIGNAL ;
    PORT
      LAYER M5 ;
        RECT  17.616 0 17.64 0.084 ;
    END
  END i[560]
  PIN i[561]
    DIRECTION INPUT ;
    USE SIGNAL ;
    PORT
      LAYER M5 ;
        RECT  17.712 0 17.736 0.084 ;
    END
  END i[561]
  PIN i[562]
    DIRECTION INPUT ;
    USE SIGNAL ;
    PORT
      LAYER M5 ;
        RECT  17.808 0 17.832 0.084 ;
    END
  END i[562]
  PIN i[563]
    DIRECTION INPUT ;
    USE SIGNAL ;
    PORT
      LAYER M5 ;
        RECT  17.904 0 17.928 0.084 ;
    END
  END i[563]
  PIN i[564]
    DIRECTION INPUT ;
    USE SIGNAL ;
    PORT
      LAYER M5 ;
        RECT  18 0 18.024 0.084 ;
    END
  END i[564]
  PIN i[565]
    DIRECTION INPUT ;
    USE SIGNAL ;
    PORT
      LAYER M5 ;
        RECT  18.096 0 18.12 0.084 ;
    END
  END i[565]
  PIN i[566]
    DIRECTION INPUT ;
    USE SIGNAL ;
    PORT
      LAYER M5 ;
        RECT  18.192 0 18.216 0.084 ;
    END
  END i[566]
  PIN i[567]
    DIRECTION INPUT ;
    USE SIGNAL ;
    PORT
      LAYER M5 ;
        RECT  18.288 0 18.312 0.084 ;
    END
  END i[567]
  PIN i[568]
    DIRECTION INPUT ;
    USE SIGNAL ;
    PORT
      LAYER M5 ;
        RECT  18.384 0 18.408 0.084 ;
    END
  END i[568]
  PIN i[569]
    DIRECTION INPUT ;
    USE SIGNAL ;
    PORT
      LAYER M5 ;
        RECT  18.48 0 18.504 0.084 ;
    END
  END i[569]
  PIN i[56]
    DIRECTION INPUT ;
    USE SIGNAL ;
    PORT
      LAYER M5 ;
        RECT  22.224 0 22.248 0.084 ;
    END
  END i[56]
  PIN i[570]
    DIRECTION INPUT ;
    USE SIGNAL ;
    PORT
      LAYER M5 ;
        RECT  18.576 0 18.6 0.084 ;
    END
  END i[570]
  PIN i[571]
    DIRECTION INPUT ;
    USE SIGNAL ;
    PORT
      LAYER M5 ;
        RECT  18.672 0 18.696 0.084 ;
    END
  END i[571]
  PIN i[572]
    DIRECTION INPUT ;
    USE SIGNAL ;
    PORT
      LAYER M5 ;
        RECT  18.768 0 18.792 0.084 ;
    END
  END i[572]
  PIN i[573]
    DIRECTION INPUT ;
    USE SIGNAL ;
    PORT
      LAYER M5 ;
        RECT  18.864 0 18.888 0.084 ;
    END
  END i[573]
  PIN i[574]
    DIRECTION INPUT ;
    USE SIGNAL ;
    PORT
      LAYER M5 ;
        RECT  18.96 0 18.984 0.084 ;
    END
  END i[574]
  PIN i[575]
    DIRECTION INPUT ;
    USE SIGNAL ;
    PORT
      LAYER M5 ;
        RECT  19.056 0 19.08 0.084 ;
    END
  END i[575]
  PIN i[576]
    DIRECTION INPUT ;
    USE SIGNAL ;
    PORT
      LAYER M5 ;
        RECT  0.72 0 0.744 0.084 ;
    END
  END i[576]
  PIN i[577]
    DIRECTION INPUT ;
    USE SIGNAL ;
    PORT
      LAYER M5 ;
        RECT  0.816 0 0.84 0.084 ;
    END
  END i[577]
  PIN i[578]
    DIRECTION INPUT ;
    USE SIGNAL ;
    PORT
      LAYER M5 ;
        RECT  0.912 0 0.936 0.084 ;
    END
  END i[578]
  PIN i[579]
    DIRECTION INPUT ;
    USE SIGNAL ;
    PORT
      LAYER M5 ;
        RECT  1.008 0 1.032 0.084 ;
    END
  END i[579]
  PIN i[57]
    DIRECTION INPUT ;
    USE SIGNAL ;
    PORT
      LAYER M5 ;
        RECT  22.32 0 22.344 0.084 ;
    END
  END i[57]
  PIN i[580]
    DIRECTION INPUT ;
    USE SIGNAL ;
    PORT
      LAYER M5 ;
        RECT  1.104 0 1.128 0.084 ;
    END
  END i[580]
  PIN i[581]
    DIRECTION INPUT ;
    USE SIGNAL ;
    PORT
      LAYER M5 ;
        RECT  1.2 0 1.224 0.084 ;
    END
  END i[581]
  PIN i[582]
    DIRECTION INPUT ;
    USE SIGNAL ;
    PORT
      LAYER M5 ;
        RECT  1.296 0 1.32 0.084 ;
    END
  END i[582]
  PIN i[583]
    DIRECTION INPUT ;
    USE SIGNAL ;
    PORT
      LAYER M5 ;
        RECT  1.392 0 1.416 0.084 ;
    END
  END i[583]
  PIN i[584]
    DIRECTION INPUT ;
    USE SIGNAL ;
    PORT
      LAYER M5 ;
        RECT  1.488 0 1.512 0.084 ;
    END
  END i[584]
  PIN i[585]
    DIRECTION INPUT ;
    USE SIGNAL ;
    PORT
      LAYER M5 ;
        RECT  1.584 0 1.608 0.084 ;
    END
  END i[585]
  PIN i[586]
    DIRECTION INPUT ;
    USE SIGNAL ;
    PORT
      LAYER M5 ;
        RECT  1.68 0 1.704 0.084 ;
    END
  END i[586]
  PIN i[587]
    DIRECTION INPUT ;
    USE SIGNAL ;
    PORT
      LAYER M5 ;
        RECT  1.776 0 1.8 0.084 ;
    END
  END i[587]
  PIN i[588]
    DIRECTION INPUT ;
    USE SIGNAL ;
    PORT
      LAYER M5 ;
        RECT  1.872 0 1.896 0.084 ;
    END
  END i[588]
  PIN i[589]
    DIRECTION INPUT ;
    USE SIGNAL ;
    PORT
      LAYER M5 ;
        RECT  1.968 0 1.992 0.084 ;
    END
  END i[589]
  PIN i[58]
    DIRECTION INPUT ;
    USE SIGNAL ;
    PORT
      LAYER M5 ;
        RECT  22.416 0 22.44 0.084 ;
    END
  END i[58]
  PIN i[590]
    DIRECTION INPUT ;
    USE SIGNAL ;
    PORT
      LAYER M5 ;
        RECT  2.064 0 2.088 0.084 ;
    END
  END i[590]
  PIN i[591]
    DIRECTION INPUT ;
    USE SIGNAL ;
    PORT
      LAYER M5 ;
        RECT  2.16 0 2.184 0.084 ;
    END
  END i[591]
  PIN i[592]
    DIRECTION INPUT ;
    USE SIGNAL ;
    PORT
      LAYER M5 ;
        RECT  2.256 0 2.28 0.084 ;
    END
  END i[592]
  PIN i[593]
    DIRECTION INPUT ;
    USE SIGNAL ;
    PORT
      LAYER M5 ;
        RECT  2.352 0 2.376 0.084 ;
    END
  END i[593]
  PIN i[594]
    DIRECTION INPUT ;
    USE SIGNAL ;
    PORT
      LAYER M5 ;
        RECT  2.448 0 2.472 0.084 ;
    END
  END i[594]
  PIN i[595]
    DIRECTION INPUT ;
    USE SIGNAL ;
    PORT
      LAYER M5 ;
        RECT  2.544 0 2.568 0.084 ;
    END
  END i[595]
  PIN i[596]
    DIRECTION INPUT ;
    USE SIGNAL ;
    PORT
      LAYER M5 ;
        RECT  2.64 0 2.664 0.084 ;
    END
  END i[596]
  PIN i[597]
    DIRECTION INPUT ;
    USE SIGNAL ;
    PORT
      LAYER M5 ;
        RECT  2.736 0 2.76 0.084 ;
    END
  END i[597]
  PIN i[598]
    DIRECTION INPUT ;
    USE SIGNAL ;
    PORT
      LAYER M5 ;
        RECT  2.832 0 2.856 0.084 ;
    END
  END i[598]
  PIN i[599]
    DIRECTION INPUT ;
    USE SIGNAL ;
    PORT
      LAYER M5 ;
        RECT  2.928 0 2.952 0.084 ;
    END
  END i[599]
  PIN i[59]
    DIRECTION INPUT ;
    USE SIGNAL ;
    PORT
      LAYER M5 ;
        RECT  22.512 0 22.536 0.084 ;
    END
  END i[59]
  PIN i[5]
    DIRECTION INPUT ;
    USE SIGNAL ;
    PORT
      LAYER M5 ;
        RECT  23.472 0 23.496 0.084 ;
    END
  END i[5]
  PIN i[600]
    DIRECTION INPUT ;
    USE SIGNAL ;
    PORT
      LAYER M5 ;
        RECT  3.024 0 3.048 0.084 ;
    END
  END i[600]
  PIN i[601]
    DIRECTION INPUT ;
    USE SIGNAL ;
    PORT
      LAYER M5 ;
        RECT  3.12 0 3.144 0.084 ;
    END
  END i[601]
  PIN i[602]
    DIRECTION INPUT ;
    USE SIGNAL ;
    PORT
      LAYER M5 ;
        RECT  3.216 0 3.24 0.084 ;
    END
  END i[602]
  PIN i[603]
    DIRECTION INPUT ;
    USE SIGNAL ;
    PORT
      LAYER M5 ;
        RECT  3.312 0 3.336 0.084 ;
    END
  END i[603]
  PIN i[604]
    DIRECTION INPUT ;
    USE SIGNAL ;
    PORT
      LAYER M5 ;
        RECT  3.408 0 3.432 0.084 ;
    END
  END i[604]
  PIN i[605]
    DIRECTION INPUT ;
    USE SIGNAL ;
    PORT
      LAYER M5 ;
        RECT  3.504 0 3.528 0.084 ;
    END
  END i[605]
  PIN i[606]
    DIRECTION INPUT ;
    USE SIGNAL ;
    PORT
      LAYER M5 ;
        RECT  3.6 0 3.624 0.084 ;
    END
  END i[606]
  PIN i[607]
    DIRECTION INPUT ;
    USE SIGNAL ;
    PORT
      LAYER M5 ;
        RECT  3.696 0 3.72 0.084 ;
    END
  END i[607]
  PIN i[608]
    DIRECTION INPUT ;
    USE SIGNAL ;
    PORT
      LAYER M5 ;
        RECT  61.392 0 61.416 0.084 ;
    END
  END i[608]
  PIN i[609]
    DIRECTION INPUT ;
    USE SIGNAL ;
    PORT
      LAYER M5 ;
        RECT  61.488 0 61.512 0.084 ;
    END
  END i[609]
  PIN i[60]
    DIRECTION INPUT ;
    USE SIGNAL ;
    PORT
      LAYER M5 ;
        RECT  22.608 0 22.632 0.084 ;
    END
  END i[60]
  PIN i[610]
    DIRECTION INPUT ;
    USE SIGNAL ;
    PORT
      LAYER M5 ;
        RECT  61.584 0 61.608 0.084 ;
    END
  END i[610]
  PIN i[611]
    DIRECTION INPUT ;
    USE SIGNAL ;
    PORT
      LAYER M5 ;
        RECT  61.68 0 61.704 0.084 ;
    END
  END i[611]
  PIN i[612]
    DIRECTION INPUT ;
    USE SIGNAL ;
    PORT
      LAYER M5 ;
        RECT  61.776 0 61.8 0.084 ;
    END
  END i[612]
  PIN i[613]
    DIRECTION INPUT ;
    USE SIGNAL ;
    PORT
      LAYER M5 ;
        RECT  61.872 0 61.896 0.084 ;
    END
  END i[613]
  PIN i[614]
    DIRECTION INPUT ;
    USE SIGNAL ;
    PORT
      LAYER M5 ;
        RECT  61.968 0 61.992 0.084 ;
    END
  END i[614]
  PIN i[615]
    DIRECTION INPUT ;
    USE SIGNAL ;
    PORT
      LAYER M5 ;
        RECT  62.064 0 62.088 0.084 ;
    END
  END i[615]
  PIN i[616]
    DIRECTION INPUT ;
    USE SIGNAL ;
    PORT
      LAYER M5 ;
        RECT  62.16 0 62.184 0.084 ;
    END
  END i[616]
  PIN i[617]
    DIRECTION INPUT ;
    USE SIGNAL ;
    PORT
      LAYER M5 ;
        RECT  62.256 0 62.28 0.084 ;
    END
  END i[617]
  PIN i[618]
    DIRECTION INPUT ;
    USE SIGNAL ;
    PORT
      LAYER M5 ;
        RECT  62.352 0 62.376 0.084 ;
    END
  END i[618]
  PIN i[619]
    DIRECTION INPUT ;
    USE SIGNAL ;
    PORT
      LAYER M5 ;
        RECT  62.448 0 62.472 0.084 ;
    END
  END i[619]
  PIN i[61]
    DIRECTION INPUT ;
    USE SIGNAL ;
    PORT
      LAYER M5 ;
        RECT  22.704 0 22.728 0.084 ;
    END
  END i[61]
  PIN i[620]
    DIRECTION INPUT ;
    USE SIGNAL ;
    PORT
      LAYER M5 ;
        RECT  62.544 0 62.568 0.084 ;
    END
  END i[620]
  PIN i[621]
    DIRECTION INPUT ;
    USE SIGNAL ;
    PORT
      LAYER M5 ;
        RECT  62.64 0 62.664 0.084 ;
    END
  END i[621]
  PIN i[622]
    DIRECTION INPUT ;
    USE SIGNAL ;
    PORT
      LAYER M5 ;
        RECT  62.736 0 62.76 0.084 ;
    END
  END i[622]
  PIN i[623]
    DIRECTION INPUT ;
    USE SIGNAL ;
    PORT
      LAYER M5 ;
        RECT  62.832 0 62.856 0.084 ;
    END
  END i[623]
  PIN i[62]
    DIRECTION INPUT ;
    USE SIGNAL ;
    PORT
      LAYER M5 ;
        RECT  22.8 0 22.824 0.084 ;
    END
  END i[62]
  PIN i[63]
    DIRECTION INPUT ;
    USE SIGNAL ;
    PORT
      LAYER M5 ;
        RECT  22.896 0 22.92 0.084 ;
    END
  END i[63]
  PIN i[64]
    DIRECTION INPUT ;
    USE SIGNAL ;
    PORT
      LAYER M5 ;
        RECT  26.064 0 26.088 0.084 ;
    END
  END i[64]
  PIN i[65]
    DIRECTION INPUT ;
    USE SIGNAL ;
    PORT
      LAYER M5 ;
        RECT  26.16 0 26.184 0.084 ;
    END
  END i[65]
  PIN i[66]
    DIRECTION INPUT ;
    USE SIGNAL ;
    PORT
      LAYER M5 ;
        RECT  26.256 0 26.28 0.084 ;
    END
  END i[66]
  PIN i[67]
    DIRECTION INPUT ;
    USE SIGNAL ;
    PORT
      LAYER M5 ;
        RECT  26.352 0 26.376 0.084 ;
    END
  END i[67]
  PIN i[68]
    DIRECTION INPUT ;
    USE SIGNAL ;
    PORT
      LAYER M5 ;
        RECT  26.448 0 26.472 0.084 ;
    END
  END i[68]
  PIN i[69]
    DIRECTION INPUT ;
    USE SIGNAL ;
    PORT
      LAYER M5 ;
        RECT  26.544 0 26.568 0.084 ;
    END
  END i[69]
  PIN i[6]
    DIRECTION INPUT ;
    USE SIGNAL ;
    PORT
      LAYER M5 ;
        RECT  23.568 0 23.592 0.084 ;
    END
  END i[6]
  PIN i[70]
    DIRECTION INPUT ;
    USE SIGNAL ;
    PORT
      LAYER M5 ;
        RECT  26.64 0 26.664 0.084 ;
    END
  END i[70]
  PIN i[71]
    DIRECTION INPUT ;
    USE SIGNAL ;
    PORT
      LAYER M5 ;
        RECT  26.736 0 26.76 0.084 ;
    END
  END i[71]
  PIN i[72]
    DIRECTION INPUT ;
    USE SIGNAL ;
    PORT
      LAYER M5 ;
        RECT  26.832 0 26.856 0.084 ;
    END
  END i[72]
  PIN i[73]
    DIRECTION INPUT ;
    USE SIGNAL ;
    PORT
      LAYER M5 ;
        RECT  26.928 0 26.952 0.084 ;
    END
  END i[73]
  PIN i[74]
    DIRECTION INPUT ;
    USE SIGNAL ;
    PORT
      LAYER M5 ;
        RECT  27.024 0 27.048 0.084 ;
    END
  END i[74]
  PIN i[75]
    DIRECTION INPUT ;
    USE SIGNAL ;
    PORT
      LAYER M5 ;
        RECT  27.12 0 27.144 0.084 ;
    END
  END i[75]
  PIN i[76]
    DIRECTION INPUT ;
    USE SIGNAL ;
    PORT
      LAYER M5 ;
        RECT  27.216 0 27.24 0.084 ;
    END
  END i[76]
  PIN i[77]
    DIRECTION INPUT ;
    USE SIGNAL ;
    PORT
      LAYER M5 ;
        RECT  27.312 0 27.336 0.084 ;
    END
  END i[77]
  PIN i[78]
    DIRECTION INPUT ;
    USE SIGNAL ;
    PORT
      LAYER M5 ;
        RECT  27.408 0 27.432 0.084 ;
    END
  END i[78]
  PIN i[79]
    DIRECTION INPUT ;
    USE SIGNAL ;
    PORT
      LAYER M5 ;
        RECT  27.504 0 27.528 0.084 ;
    END
  END i[79]
  PIN i[7]
    DIRECTION INPUT ;
    USE SIGNAL ;
    PORT
      LAYER M5 ;
        RECT  23.664 0 23.688 0.084 ;
    END
  END i[7]
  PIN i[80]
    DIRECTION INPUT ;
    USE SIGNAL ;
    PORT
      LAYER M5 ;
        RECT  27.6 0 27.624 0.084 ;
    END
  END i[80]
  PIN i[81]
    DIRECTION INPUT ;
    USE SIGNAL ;
    PORT
      LAYER M5 ;
        RECT  27.696 0 27.72 0.084 ;
    END
  END i[81]
  PIN i[82]
    DIRECTION INPUT ;
    USE SIGNAL ;
    PORT
      LAYER M5 ;
        RECT  27.792 0 27.816 0.084 ;
    END
  END i[82]
  PIN i[83]
    DIRECTION INPUT ;
    USE SIGNAL ;
    PORT
      LAYER M5 ;
        RECT  27.888 0 27.912 0.084 ;
    END
  END i[83]
  PIN i[84]
    DIRECTION INPUT ;
    USE SIGNAL ;
    PORT
      LAYER M5 ;
        RECT  27.984 0 28.008 0.084 ;
    END
  END i[84]
  PIN i[85]
    DIRECTION INPUT ;
    USE SIGNAL ;
    PORT
      LAYER M5 ;
        RECT  28.08 0 28.104 0.084 ;
    END
  END i[85]
  PIN i[86]
    DIRECTION INPUT ;
    USE SIGNAL ;
    PORT
      LAYER M5 ;
        RECT  28.176 0 28.2 0.084 ;
    END
  END i[86]
  PIN i[87]
    DIRECTION INPUT ;
    USE SIGNAL ;
    PORT
      LAYER M5 ;
        RECT  28.272 0 28.296 0.084 ;
    END
  END i[87]
  PIN i[88]
    DIRECTION INPUT ;
    USE SIGNAL ;
    PORT
      LAYER M5 ;
        RECT  28.368 0 28.392 0.084 ;
    END
  END i[88]
  PIN i[89]
    DIRECTION INPUT ;
    USE SIGNAL ;
    PORT
      LAYER M5 ;
        RECT  28.464 0 28.488 0.084 ;
    END
  END i[89]
  PIN i[8]
    DIRECTION INPUT ;
    USE SIGNAL ;
    PORT
      LAYER M5 ;
        RECT  23.76 0 23.784 0.084 ;
    END
  END i[8]
  PIN i[90]
    DIRECTION INPUT ;
    USE SIGNAL ;
    PORT
      LAYER M5 ;
        RECT  28.56 0 28.584 0.084 ;
    END
  END i[90]
  PIN i[91]
    DIRECTION INPUT ;
    USE SIGNAL ;
    PORT
      LAYER M5 ;
        RECT  28.656 0 28.68 0.084 ;
    END
  END i[91]
  PIN i[92]
    DIRECTION INPUT ;
    USE SIGNAL ;
    PORT
      LAYER M5 ;
        RECT  28.752 0 28.776 0.084 ;
    END
  END i[92]
  PIN i[93]
    DIRECTION INPUT ;
    USE SIGNAL ;
    PORT
      LAYER M5 ;
        RECT  28.848 0 28.872 0.084 ;
    END
  END i[93]
  PIN i[94]
    DIRECTION INPUT ;
    USE SIGNAL ;
    PORT
      LAYER M5 ;
        RECT  28.944 0 28.968 0.084 ;
    END
  END i[94]
  PIN i[95]
    DIRECTION INPUT ;
    USE SIGNAL ;
    PORT
      LAYER M5 ;
        RECT  29.04 0 29.064 0.084 ;
    END
  END i[95]
  PIN i[96]
    DIRECTION INPUT ;
    USE SIGNAL ;
    PORT
      LAYER M5 ;
        RECT  32.208 0 32.232 0.084 ;
    END
  END i[96]
  PIN i[97]
    DIRECTION INPUT ;
    USE SIGNAL ;
    PORT
      LAYER M5 ;
        RECT  32.304 0 32.328 0.084 ;
    END
  END i[97]
  PIN i[98]
    DIRECTION INPUT ;
    USE SIGNAL ;
    PORT
      LAYER M5 ;
        RECT  32.4 0 32.424 0.084 ;
    END
  END i[98]
  PIN i[99]
    DIRECTION INPUT ;
    USE SIGNAL ;
    PORT
      LAYER M5 ;
        RECT  32.496 0 32.52 0.084 ;
    END
  END i[99]
  PIN i[9]
    DIRECTION INPUT ;
    USE SIGNAL ;
    PORT
      LAYER M5 ;
        RECT  23.856 0 23.88 0.084 ;
    END
  END i[9]
  PIN o[0]
    DIRECTION OUTPUT ;
    USE SIGNAL ;
    PORT
      LAYER M5 ;
        RECT  16.464 23.676 16.488 23.76 ;
    END
  END o[0]
  PIN o[100]
    DIRECTION OUTPUT ;
    USE SIGNAL ;
    PORT
      LAYER M5 ;
        RECT  10.704 23.676 10.728 23.76 ;
    END
  END o[100]
  PIN o[101]
    DIRECTION OUTPUT ;
    USE SIGNAL ;
    PORT
      LAYER M5 ;
        RECT  10.8 23.676 10.824 23.76 ;
    END
  END o[101]
  PIN o[102]
    DIRECTION OUTPUT ;
    USE SIGNAL ;
    PORT
      LAYER M5 ;
        RECT  10.896 23.676 10.92 23.76 ;
    END
  END o[102]
  PIN o[103]
    DIRECTION OUTPUT ;
    USE SIGNAL ;
    PORT
      LAYER M5 ;
        RECT  10.992 23.676 11.016 23.76 ;
    END
  END o[103]
  PIN o[104]
    DIRECTION OUTPUT ;
    USE SIGNAL ;
    PORT
      LAYER M5 ;
        RECT  11.088 23.676 11.112 23.76 ;
    END
  END o[104]
  PIN o[105]
    DIRECTION OUTPUT ;
    USE SIGNAL ;
    PORT
      LAYER M5 ;
        RECT  11.184 23.676 11.208 23.76 ;
    END
  END o[105]
  PIN o[106]
    DIRECTION OUTPUT ;
    USE SIGNAL ;
    PORT
      LAYER M5 ;
        RECT  11.28 23.676 11.304 23.76 ;
    END
  END o[106]
  PIN o[107]
    DIRECTION OUTPUT ;
    USE SIGNAL ;
    PORT
      LAYER M5 ;
        RECT  11.376 23.676 11.4 23.76 ;
    END
  END o[107]
  PIN o[108]
    DIRECTION OUTPUT ;
    USE SIGNAL ;
    PORT
      LAYER M5 ;
        RECT  11.472 23.676 11.496 23.76 ;
    END
  END o[108]
  PIN o[109]
    DIRECTION OUTPUT ;
    USE SIGNAL ;
    PORT
      LAYER M5 ;
        RECT  11.568 23.676 11.592 23.76 ;
    END
  END o[109]
  PIN o[10]
    DIRECTION OUTPUT ;
    USE SIGNAL ;
    PORT
      LAYER M5 ;
        RECT  17.424 23.676 17.448 23.76 ;
    END
  END o[10]
  PIN o[110]
    DIRECTION OUTPUT ;
    USE SIGNAL ;
    PORT
      LAYER M5 ;
        RECT  11.664 23.676 11.688 23.76 ;
    END
  END o[110]
  PIN o[111]
    DIRECTION OUTPUT ;
    USE SIGNAL ;
    PORT
      LAYER M5 ;
        RECT  11.76 23.676 11.784 23.76 ;
    END
  END o[111]
  PIN o[112]
    DIRECTION OUTPUT ;
    USE SIGNAL ;
    PORT
      LAYER M5 ;
        RECT  11.856 23.676 11.88 23.76 ;
    END
  END o[112]
  PIN o[113]
    DIRECTION OUTPUT ;
    USE SIGNAL ;
    PORT
      LAYER M5 ;
        RECT  11.952 23.676 11.976 23.76 ;
    END
  END o[113]
  PIN o[114]
    DIRECTION OUTPUT ;
    USE SIGNAL ;
    PORT
      LAYER M5 ;
        RECT  12.048 23.676 12.072 23.76 ;
    END
  END o[114]
  PIN o[115]
    DIRECTION OUTPUT ;
    USE SIGNAL ;
    PORT
      LAYER M5 ;
        RECT  12.144 23.676 12.168 23.76 ;
    END
  END o[115]
  PIN o[116]
    DIRECTION OUTPUT ;
    USE SIGNAL ;
    PORT
      LAYER M5 ;
        RECT  12.24 23.676 12.264 23.76 ;
    END
  END o[116]
  PIN o[117]
    DIRECTION OUTPUT ;
    USE SIGNAL ;
    PORT
      LAYER M5 ;
        RECT  12.336 23.676 12.36 23.76 ;
    END
  END o[117]
  PIN o[118]
    DIRECTION OUTPUT ;
    USE SIGNAL ;
    PORT
      LAYER M5 ;
        RECT  12.432 23.676 12.456 23.76 ;
    END
  END o[118]
  PIN o[119]
    DIRECTION OUTPUT ;
    USE SIGNAL ;
    PORT
      LAYER M5 ;
        RECT  12.528 23.676 12.552 23.76 ;
    END
  END o[119]
  PIN o[11]
    DIRECTION OUTPUT ;
    USE SIGNAL ;
    PORT
      LAYER M5 ;
        RECT  17.52 23.676 17.544 23.76 ;
    END
  END o[11]
  PIN o[120]
    DIRECTION OUTPUT ;
    USE SIGNAL ;
    PORT
      LAYER M5 ;
        RECT  12.624 23.676 12.648 23.76 ;
    END
  END o[120]
  PIN o[121]
    DIRECTION OUTPUT ;
    USE SIGNAL ;
    PORT
      LAYER M5 ;
        RECT  12.72 23.676 12.744 23.76 ;
    END
  END o[121]
  PIN o[122]
    DIRECTION OUTPUT ;
    USE SIGNAL ;
    PORT
      LAYER M5 ;
        RECT  12.816 23.676 12.84 23.76 ;
    END
  END o[122]
  PIN o[123]
    DIRECTION OUTPUT ;
    USE SIGNAL ;
    PORT
      LAYER M5 ;
        RECT  12.912 23.676 12.936 23.76 ;
    END
  END o[123]
  PIN o[124]
    DIRECTION OUTPUT ;
    USE SIGNAL ;
    PORT
      LAYER M5 ;
        RECT  13.008 23.676 13.032 23.76 ;
    END
  END o[124]
  PIN o[125]
    DIRECTION OUTPUT ;
    USE SIGNAL ;
    PORT
      LAYER M5 ;
        RECT  13.104 23.676 13.128 23.76 ;
    END
  END o[125]
  PIN o[126]
    DIRECTION OUTPUT ;
    USE SIGNAL ;
    PORT
      LAYER M5 ;
        RECT  13.2 23.676 13.224 23.76 ;
    END
  END o[126]
  PIN o[127]
    DIRECTION OUTPUT ;
    USE SIGNAL ;
    PORT
      LAYER M5 ;
        RECT  13.296 23.676 13.32 23.76 ;
    END
  END o[127]
  PIN o[128]
    DIRECTION OUTPUT ;
    USE SIGNAL ;
    PORT
      LAYER M5 ;
        RECT  19.536 23.676 19.56 23.76 ;
    END
  END o[128]
  PIN o[129]
    DIRECTION OUTPUT ;
    USE SIGNAL ;
    PORT
      LAYER M5 ;
        RECT  19.632 23.676 19.656 23.76 ;
    END
  END o[129]
  PIN o[12]
    DIRECTION OUTPUT ;
    USE SIGNAL ;
    PORT
      LAYER M5 ;
        RECT  17.616 23.676 17.64 23.76 ;
    END
  END o[12]
  PIN o[130]
    DIRECTION OUTPUT ;
    USE SIGNAL ;
    PORT
      LAYER M5 ;
        RECT  19.728 23.676 19.752 23.76 ;
    END
  END o[130]
  PIN o[131]
    DIRECTION OUTPUT ;
    USE SIGNAL ;
    PORT
      LAYER M5 ;
        RECT  19.824 23.676 19.848 23.76 ;
    END
  END o[131]
  PIN o[132]
    DIRECTION OUTPUT ;
    USE SIGNAL ;
    PORT
      LAYER M5 ;
        RECT  19.92 23.676 19.944 23.76 ;
    END
  END o[132]
  PIN o[133]
    DIRECTION OUTPUT ;
    USE SIGNAL ;
    PORT
      LAYER M5 ;
        RECT  20.016 23.676 20.04 23.76 ;
    END
  END o[133]
  PIN o[134]
    DIRECTION OUTPUT ;
    USE SIGNAL ;
    PORT
      LAYER M5 ;
        RECT  20.112 23.676 20.136 23.76 ;
    END
  END o[134]
  PIN o[135]
    DIRECTION OUTPUT ;
    USE SIGNAL ;
    PORT
      LAYER M5 ;
        RECT  20.208 23.676 20.232 23.76 ;
    END
  END o[135]
  PIN o[136]
    DIRECTION OUTPUT ;
    USE SIGNAL ;
    PORT
      LAYER M5 ;
        RECT  20.304 23.676 20.328 23.76 ;
    END
  END o[136]
  PIN o[137]
    DIRECTION OUTPUT ;
    USE SIGNAL ;
    PORT
      LAYER M5 ;
        RECT  20.4 23.676 20.424 23.76 ;
    END
  END o[137]
  PIN o[138]
    DIRECTION OUTPUT ;
    USE SIGNAL ;
    PORT
      LAYER M5 ;
        RECT  20.496 23.676 20.52 23.76 ;
    END
  END o[138]
  PIN o[139]
    DIRECTION OUTPUT ;
    USE SIGNAL ;
    PORT
      LAYER M5 ;
        RECT  20.592 23.676 20.616 23.76 ;
    END
  END o[139]
  PIN o[13]
    DIRECTION OUTPUT ;
    USE SIGNAL ;
    PORT
      LAYER M5 ;
        RECT  17.712 23.676 17.736 23.76 ;
    END
  END o[13]
  PIN o[140]
    DIRECTION OUTPUT ;
    USE SIGNAL ;
    PORT
      LAYER M5 ;
        RECT  20.688 23.676 20.712 23.76 ;
    END
  END o[140]
  PIN o[141]
    DIRECTION OUTPUT ;
    USE SIGNAL ;
    PORT
      LAYER M5 ;
        RECT  20.784 23.676 20.808 23.76 ;
    END
  END o[141]
  PIN o[142]
    DIRECTION OUTPUT ;
    USE SIGNAL ;
    PORT
      LAYER M5 ;
        RECT  20.88 23.676 20.904 23.76 ;
    END
  END o[142]
  PIN o[143]
    DIRECTION OUTPUT ;
    USE SIGNAL ;
    PORT
      LAYER M5 ;
        RECT  20.976 23.676 21 23.76 ;
    END
  END o[143]
  PIN o[144]
    DIRECTION OUTPUT ;
    USE SIGNAL ;
    PORT
      LAYER M5 ;
        RECT  21.072 23.676 21.096 23.76 ;
    END
  END o[144]
  PIN o[145]
    DIRECTION OUTPUT ;
    USE SIGNAL ;
    PORT
      LAYER M5 ;
        RECT  21.168 23.676 21.192 23.76 ;
    END
  END o[145]
  PIN o[146]
    DIRECTION OUTPUT ;
    USE SIGNAL ;
    PORT
      LAYER M5 ;
        RECT  21.264 23.676 21.288 23.76 ;
    END
  END o[146]
  PIN o[147]
    DIRECTION OUTPUT ;
    USE SIGNAL ;
    PORT
      LAYER M5 ;
        RECT  21.36 23.676 21.384 23.76 ;
    END
  END o[147]
  PIN o[148]
    DIRECTION OUTPUT ;
    USE SIGNAL ;
    PORT
      LAYER M5 ;
        RECT  21.456 23.676 21.48 23.76 ;
    END
  END o[148]
  PIN o[149]
    DIRECTION OUTPUT ;
    USE SIGNAL ;
    PORT
      LAYER M5 ;
        RECT  21.552 23.676 21.576 23.76 ;
    END
  END o[149]
  PIN o[14]
    DIRECTION OUTPUT ;
    USE SIGNAL ;
    PORT
      LAYER M5 ;
        RECT  17.808 23.676 17.832 23.76 ;
    END
  END o[14]
  PIN o[150]
    DIRECTION OUTPUT ;
    USE SIGNAL ;
    PORT
      LAYER M5 ;
        RECT  21.648 23.676 21.672 23.76 ;
    END
  END o[150]
  PIN o[151]
    DIRECTION OUTPUT ;
    USE SIGNAL ;
    PORT
      LAYER M5 ;
        RECT  21.744 23.676 21.768 23.76 ;
    END
  END o[151]
  PIN o[152]
    DIRECTION OUTPUT ;
    USE SIGNAL ;
    PORT
      LAYER M5 ;
        RECT  21.84 23.676 21.864 23.76 ;
    END
  END o[152]
  PIN o[153]
    DIRECTION OUTPUT ;
    USE SIGNAL ;
    PORT
      LAYER M5 ;
        RECT  21.936 23.676 21.96 23.76 ;
    END
  END o[153]
  PIN o[154]
    DIRECTION OUTPUT ;
    USE SIGNAL ;
    PORT
      LAYER M5 ;
        RECT  22.032 23.676 22.056 23.76 ;
    END
  END o[154]
  PIN o[155]
    DIRECTION OUTPUT ;
    USE SIGNAL ;
    PORT
      LAYER M5 ;
        RECT  22.128 23.676 22.152 23.76 ;
    END
  END o[155]
  PIN o[156]
    DIRECTION OUTPUT ;
    USE SIGNAL ;
    PORT
      LAYER M5 ;
        RECT  22.224 23.676 22.248 23.76 ;
    END
  END o[156]
  PIN o[157]
    DIRECTION OUTPUT ;
    USE SIGNAL ;
    PORT
      LAYER M5 ;
        RECT  22.32 23.676 22.344 23.76 ;
    END
  END o[157]
  PIN o[158]
    DIRECTION OUTPUT ;
    USE SIGNAL ;
    PORT
      LAYER M5 ;
        RECT  22.416 23.676 22.44 23.76 ;
    END
  END o[158]
  PIN o[159]
    DIRECTION OUTPUT ;
    USE SIGNAL ;
    PORT
      LAYER M5 ;
        RECT  22.512 23.676 22.536 23.76 ;
    END
  END o[159]
  PIN o[15]
    DIRECTION OUTPUT ;
    USE SIGNAL ;
    PORT
      LAYER M5 ;
        RECT  17.904 23.676 17.928 23.76 ;
    END
  END o[15]
  PIN o[160]
    DIRECTION OUTPUT ;
    USE SIGNAL ;
    PORT
      LAYER M5 ;
        RECT  7.248 23.676 7.272 23.76 ;
    END
  END o[160]
  PIN o[161]
    DIRECTION OUTPUT ;
    USE SIGNAL ;
    PORT
      LAYER M5 ;
        RECT  7.344 23.676 7.368 23.76 ;
    END
  END o[161]
  PIN o[162]
    DIRECTION OUTPUT ;
    USE SIGNAL ;
    PORT
      LAYER M5 ;
        RECT  7.44 23.676 7.464 23.76 ;
    END
  END o[162]
  PIN o[163]
    DIRECTION OUTPUT ;
    USE SIGNAL ;
    PORT
      LAYER M5 ;
        RECT  7.536 23.676 7.56 23.76 ;
    END
  END o[163]
  PIN o[164]
    DIRECTION OUTPUT ;
    USE SIGNAL ;
    PORT
      LAYER M5 ;
        RECT  7.632 23.676 7.656 23.76 ;
    END
  END o[164]
  PIN o[165]
    DIRECTION OUTPUT ;
    USE SIGNAL ;
    PORT
      LAYER M5 ;
        RECT  7.728 23.676 7.752 23.76 ;
    END
  END o[165]
  PIN o[166]
    DIRECTION OUTPUT ;
    USE SIGNAL ;
    PORT
      LAYER M5 ;
        RECT  7.824 23.676 7.848 23.76 ;
    END
  END o[166]
  PIN o[167]
    DIRECTION OUTPUT ;
    USE SIGNAL ;
    PORT
      LAYER M5 ;
        RECT  7.92 23.676 7.944 23.76 ;
    END
  END o[167]
  PIN o[168]
    DIRECTION OUTPUT ;
    USE SIGNAL ;
    PORT
      LAYER M5 ;
        RECT  8.016 23.676 8.04 23.76 ;
    END
  END o[168]
  PIN o[169]
    DIRECTION OUTPUT ;
    USE SIGNAL ;
    PORT
      LAYER M5 ;
        RECT  8.112 23.676 8.136 23.76 ;
    END
  END o[169]
  PIN o[16]
    DIRECTION OUTPUT ;
    USE SIGNAL ;
    PORT
      LAYER M5 ;
        RECT  18 23.676 18.024 23.76 ;
    END
  END o[16]
  PIN o[170]
    DIRECTION OUTPUT ;
    USE SIGNAL ;
    PORT
      LAYER M5 ;
        RECT  8.208 23.676 8.232 23.76 ;
    END
  END o[170]
  PIN o[171]
    DIRECTION OUTPUT ;
    USE SIGNAL ;
    PORT
      LAYER M5 ;
        RECT  8.304 23.676 8.328 23.76 ;
    END
  END o[171]
  PIN o[172]
    DIRECTION OUTPUT ;
    USE SIGNAL ;
    PORT
      LAYER M5 ;
        RECT  8.4 23.676 8.424 23.76 ;
    END
  END o[172]
  PIN o[173]
    DIRECTION OUTPUT ;
    USE SIGNAL ;
    PORT
      LAYER M5 ;
        RECT  8.496 23.676 8.52 23.76 ;
    END
  END o[173]
  PIN o[174]
    DIRECTION OUTPUT ;
    USE SIGNAL ;
    PORT
      LAYER M5 ;
        RECT  8.592 23.676 8.616 23.76 ;
    END
  END o[174]
  PIN o[175]
    DIRECTION OUTPUT ;
    USE SIGNAL ;
    PORT
      LAYER M5 ;
        RECT  8.688 23.676 8.712 23.76 ;
    END
  END o[175]
  PIN o[176]
    DIRECTION OUTPUT ;
    USE SIGNAL ;
    PORT
      LAYER M5 ;
        RECT  8.784 23.676 8.808 23.76 ;
    END
  END o[176]
  PIN o[177]
    DIRECTION OUTPUT ;
    USE SIGNAL ;
    PORT
      LAYER M5 ;
        RECT  8.88 23.676 8.904 23.76 ;
    END
  END o[177]
  PIN o[178]
    DIRECTION OUTPUT ;
    USE SIGNAL ;
    PORT
      LAYER M5 ;
        RECT  8.976 23.676 9 23.76 ;
    END
  END o[178]
  PIN o[179]
    DIRECTION OUTPUT ;
    USE SIGNAL ;
    PORT
      LAYER M5 ;
        RECT  9.072 23.676 9.096 23.76 ;
    END
  END o[179]
  PIN o[17]
    DIRECTION OUTPUT ;
    USE SIGNAL ;
    PORT
      LAYER M5 ;
        RECT  18.096 23.676 18.12 23.76 ;
    END
  END o[17]
  PIN o[180]
    DIRECTION OUTPUT ;
    USE SIGNAL ;
    PORT
      LAYER M5 ;
        RECT  9.168 23.676 9.192 23.76 ;
    END
  END o[180]
  PIN o[181]
    DIRECTION OUTPUT ;
    USE SIGNAL ;
    PORT
      LAYER M5 ;
        RECT  9.264 23.676 9.288 23.76 ;
    END
  END o[181]
  PIN o[182]
    DIRECTION OUTPUT ;
    USE SIGNAL ;
    PORT
      LAYER M5 ;
        RECT  9.36 23.676 9.384 23.76 ;
    END
  END o[182]
  PIN o[183]
    DIRECTION OUTPUT ;
    USE SIGNAL ;
    PORT
      LAYER M5 ;
        RECT  9.456 23.676 9.48 23.76 ;
    END
  END o[183]
  PIN o[184]
    DIRECTION OUTPUT ;
    USE SIGNAL ;
    PORT
      LAYER M5 ;
        RECT  9.552 23.676 9.576 23.76 ;
    END
  END o[184]
  PIN o[185]
    DIRECTION OUTPUT ;
    USE SIGNAL ;
    PORT
      LAYER M5 ;
        RECT  9.648 23.676 9.672 23.76 ;
    END
  END o[185]
  PIN o[186]
    DIRECTION OUTPUT ;
    USE SIGNAL ;
    PORT
      LAYER M5 ;
        RECT  9.744 23.676 9.768 23.76 ;
    END
  END o[186]
  PIN o[187]
    DIRECTION OUTPUT ;
    USE SIGNAL ;
    PORT
      LAYER M5 ;
        RECT  9.84 23.676 9.864 23.76 ;
    END
  END o[187]
  PIN o[188]
    DIRECTION OUTPUT ;
    USE SIGNAL ;
    PORT
      LAYER M5 ;
        RECT  9.936 23.676 9.96 23.76 ;
    END
  END o[188]
  PIN o[189]
    DIRECTION OUTPUT ;
    USE SIGNAL ;
    PORT
      LAYER M5 ;
        RECT  10.032 23.676 10.056 23.76 ;
    END
  END o[189]
  PIN o[18]
    DIRECTION OUTPUT ;
    USE SIGNAL ;
    PORT
      LAYER M5 ;
        RECT  18.192 23.676 18.216 23.76 ;
    END
  END o[18]
  PIN o[190]
    DIRECTION OUTPUT ;
    USE SIGNAL ;
    PORT
      LAYER M5 ;
        RECT  10.128 23.676 10.152 23.76 ;
    END
  END o[190]
  PIN o[191]
    DIRECTION OUTPUT ;
    USE SIGNAL ;
    PORT
      LAYER M5 ;
        RECT  10.224 23.676 10.248 23.76 ;
    END
  END o[191]
  PIN o[192]
    DIRECTION OUTPUT ;
    USE SIGNAL ;
    PORT
      LAYER M5 ;
        RECT  29.52 23.676 29.544 23.76 ;
    END
  END o[192]
  PIN o[193]
    DIRECTION OUTPUT ;
    USE SIGNAL ;
    PORT
      LAYER M5 ;
        RECT  29.616 23.676 29.64 23.76 ;
    END
  END o[193]
  PIN o[194]
    DIRECTION OUTPUT ;
    USE SIGNAL ;
    PORT
      LAYER M5 ;
        RECT  29.712 23.676 29.736 23.76 ;
    END
  END o[194]
  PIN o[195]
    DIRECTION OUTPUT ;
    USE SIGNAL ;
    PORT
      LAYER M5 ;
        RECT  29.808 23.676 29.832 23.76 ;
    END
  END o[195]
  PIN o[196]
    DIRECTION OUTPUT ;
    USE SIGNAL ;
    PORT
      LAYER M5 ;
        RECT  29.904 23.676 29.928 23.76 ;
    END
  END o[196]
  PIN o[197]
    DIRECTION OUTPUT ;
    USE SIGNAL ;
    PORT
      LAYER M5 ;
        RECT  30 23.676 30.024 23.76 ;
    END
  END o[197]
  PIN o[198]
    DIRECTION OUTPUT ;
    USE SIGNAL ;
    PORT
      LAYER M5 ;
        RECT  30.096 23.676 30.12 23.76 ;
    END
  END o[198]
  PIN o[199]
    DIRECTION OUTPUT ;
    USE SIGNAL ;
    PORT
      LAYER M5 ;
        RECT  30.192 23.676 30.216 23.76 ;
    END
  END o[199]
  PIN o[19]
    DIRECTION OUTPUT ;
    USE SIGNAL ;
    PORT
      LAYER M5 ;
        RECT  18.288 23.676 18.312 23.76 ;
    END
  END o[19]
  PIN o[1]
    DIRECTION OUTPUT ;
    USE SIGNAL ;
    PORT
      LAYER M5 ;
        RECT  16.56 23.676 16.584 23.76 ;
    END
  END o[1]
  PIN o[200]
    DIRECTION OUTPUT ;
    USE SIGNAL ;
    PORT
      LAYER M5 ;
        RECT  30.288 23.676 30.312 23.76 ;
    END
  END o[200]
  PIN o[201]
    DIRECTION OUTPUT ;
    USE SIGNAL ;
    PORT
      LAYER M5 ;
        RECT  30.384 23.676 30.408 23.76 ;
    END
  END o[201]
  PIN o[202]
    DIRECTION OUTPUT ;
    USE SIGNAL ;
    PORT
      LAYER M5 ;
        RECT  30.48 23.676 30.504 23.76 ;
    END
  END o[202]
  PIN o[203]
    DIRECTION OUTPUT ;
    USE SIGNAL ;
    PORT
      LAYER M5 ;
        RECT  30.576 23.676 30.6 23.76 ;
    END
  END o[203]
  PIN o[204]
    DIRECTION OUTPUT ;
    USE SIGNAL ;
    PORT
      LAYER M5 ;
        RECT  30.672 23.676 30.696 23.76 ;
    END
  END o[204]
  PIN o[205]
    DIRECTION OUTPUT ;
    USE SIGNAL ;
    PORT
      LAYER M5 ;
        RECT  30.768 23.676 30.792 23.76 ;
    END
  END o[205]
  PIN o[206]
    DIRECTION OUTPUT ;
    USE SIGNAL ;
    PORT
      LAYER M5 ;
        RECT  30.864 23.676 30.888 23.76 ;
    END
  END o[206]
  PIN o[207]
    DIRECTION OUTPUT ;
    USE SIGNAL ;
    PORT
      LAYER M5 ;
        RECT  30.96 23.676 30.984 23.76 ;
    END
  END o[207]
  PIN o[208]
    DIRECTION OUTPUT ;
    USE SIGNAL ;
    PORT
      LAYER M5 ;
        RECT  31.056 23.676 31.08 23.76 ;
    END
  END o[208]
  PIN o[209]
    DIRECTION OUTPUT ;
    USE SIGNAL ;
    PORT
      LAYER M5 ;
        RECT  31.152 23.676 31.176 23.76 ;
    END
  END o[209]
  PIN o[20]
    DIRECTION OUTPUT ;
    USE SIGNAL ;
    PORT
      LAYER M5 ;
        RECT  18.384 23.676 18.408 23.76 ;
    END
  END o[20]
  PIN o[210]
    DIRECTION OUTPUT ;
    USE SIGNAL ;
    PORT
      LAYER M5 ;
        RECT  31.248 23.676 31.272 23.76 ;
    END
  END o[210]
  PIN o[211]
    DIRECTION OUTPUT ;
    USE SIGNAL ;
    PORT
      LAYER M5 ;
        RECT  31.344 23.676 31.368 23.76 ;
    END
  END o[211]
  PIN o[212]
    DIRECTION OUTPUT ;
    USE SIGNAL ;
    PORT
      LAYER M5 ;
        RECT  31.44 23.676 31.464 23.76 ;
    END
  END o[212]
  PIN o[213]
    DIRECTION OUTPUT ;
    USE SIGNAL ;
    PORT
      LAYER M5 ;
        RECT  31.536 23.676 31.56 23.76 ;
    END
  END o[213]
  PIN o[214]
    DIRECTION OUTPUT ;
    USE SIGNAL ;
    PORT
      LAYER M5 ;
        RECT  31.632 23.676 31.656 23.76 ;
    END
  END o[214]
  PIN o[215]
    DIRECTION OUTPUT ;
    USE SIGNAL ;
    PORT
      LAYER M5 ;
        RECT  31.728 23.676 31.752 23.76 ;
    END
  END o[215]
  PIN o[216]
    DIRECTION OUTPUT ;
    USE SIGNAL ;
    PORT
      LAYER M5 ;
        RECT  31.824 23.676 31.848 23.76 ;
    END
  END o[216]
  PIN o[217]
    DIRECTION OUTPUT ;
    USE SIGNAL ;
    PORT
      LAYER M5 ;
        RECT  31.92 23.676 31.944 23.76 ;
    END
  END o[217]
  PIN o[218]
    DIRECTION OUTPUT ;
    USE SIGNAL ;
    PORT
      LAYER M5 ;
        RECT  32.016 23.676 32.04 23.76 ;
    END
  END o[218]
  PIN o[219]
    DIRECTION OUTPUT ;
    USE SIGNAL ;
    PORT
      LAYER M5 ;
        RECT  32.112 23.676 32.136 23.76 ;
    END
  END o[219]
  PIN o[21]
    DIRECTION OUTPUT ;
    USE SIGNAL ;
    PORT
      LAYER M5 ;
        RECT  18.48 23.676 18.504 23.76 ;
    END
  END o[21]
  PIN o[220]
    DIRECTION OUTPUT ;
    USE SIGNAL ;
    PORT
      LAYER M5 ;
        RECT  32.208 23.676 32.232 23.76 ;
    END
  END o[220]
  PIN o[221]
    DIRECTION OUTPUT ;
    USE SIGNAL ;
    PORT
      LAYER M5 ;
        RECT  32.304 23.676 32.328 23.76 ;
    END
  END o[221]
  PIN o[222]
    DIRECTION OUTPUT ;
    USE SIGNAL ;
    PORT
      LAYER M5 ;
        RECT  32.4 23.676 32.424 23.76 ;
    END
  END o[222]
  PIN o[223]
    DIRECTION OUTPUT ;
    USE SIGNAL ;
    PORT
      LAYER M5 ;
        RECT  32.496 23.676 32.52 23.76 ;
    END
  END o[223]
  PIN o[224]
    DIRECTION OUTPUT ;
    USE SIGNAL ;
    PORT
      LAYER M5 ;
        RECT  26.448 23.676 26.472 23.76 ;
    END
  END o[224]
  PIN o[225]
    DIRECTION OUTPUT ;
    USE SIGNAL ;
    PORT
      LAYER M5 ;
        RECT  26.544 23.676 26.568 23.76 ;
    END
  END o[225]
  PIN o[226]
    DIRECTION OUTPUT ;
    USE SIGNAL ;
    PORT
      LAYER M5 ;
        RECT  26.64 23.676 26.664 23.76 ;
    END
  END o[226]
  PIN o[227]
    DIRECTION OUTPUT ;
    USE SIGNAL ;
    PORT
      LAYER M5 ;
        RECT  26.736 23.676 26.76 23.76 ;
    END
  END o[227]
  PIN o[228]
    DIRECTION OUTPUT ;
    USE SIGNAL ;
    PORT
      LAYER M5 ;
        RECT  26.832 23.676 26.856 23.76 ;
    END
  END o[228]
  PIN o[229]
    DIRECTION OUTPUT ;
    USE SIGNAL ;
    PORT
      LAYER M5 ;
        RECT  26.928 23.676 26.952 23.76 ;
    END
  END o[229]
  PIN o[22]
    DIRECTION OUTPUT ;
    USE SIGNAL ;
    PORT
      LAYER M5 ;
        RECT  18.576 23.676 18.6 23.76 ;
    END
  END o[22]
  PIN o[230]
    DIRECTION OUTPUT ;
    USE SIGNAL ;
    PORT
      LAYER M5 ;
        RECT  27.024 23.676 27.048 23.76 ;
    END
  END o[230]
  PIN o[231]
    DIRECTION OUTPUT ;
    USE SIGNAL ;
    PORT
      LAYER M5 ;
        RECT  27.12 23.676 27.144 23.76 ;
    END
  END o[231]
  PIN o[232]
    DIRECTION OUTPUT ;
    USE SIGNAL ;
    PORT
      LAYER M5 ;
        RECT  27.216 23.676 27.24 23.76 ;
    END
  END o[232]
  PIN o[233]
    DIRECTION OUTPUT ;
    USE SIGNAL ;
    PORT
      LAYER M5 ;
        RECT  27.312 23.676 27.336 23.76 ;
    END
  END o[233]
  PIN o[234]
    DIRECTION OUTPUT ;
    USE SIGNAL ;
    PORT
      LAYER M5 ;
        RECT  27.408 23.676 27.432 23.76 ;
    END
  END o[234]
  PIN o[235]
    DIRECTION OUTPUT ;
    USE SIGNAL ;
    PORT
      LAYER M5 ;
        RECT  27.504 23.676 27.528 23.76 ;
    END
  END o[235]
  PIN o[236]
    DIRECTION OUTPUT ;
    USE SIGNAL ;
    PORT
      LAYER M5 ;
        RECT  27.6 23.676 27.624 23.76 ;
    END
  END o[236]
  PIN o[237]
    DIRECTION OUTPUT ;
    USE SIGNAL ;
    PORT
      LAYER M5 ;
        RECT  27.696 23.676 27.72 23.76 ;
    END
  END o[237]
  PIN o[238]
    DIRECTION OUTPUT ;
    USE SIGNAL ;
    PORT
      LAYER M5 ;
        RECT  27.792 23.676 27.816 23.76 ;
    END
  END o[238]
  PIN o[239]
    DIRECTION OUTPUT ;
    USE SIGNAL ;
    PORT
      LAYER M5 ;
        RECT  27.888 23.676 27.912 23.76 ;
    END
  END o[239]
  PIN o[23]
    DIRECTION OUTPUT ;
    USE SIGNAL ;
    PORT
      LAYER M5 ;
        RECT  18.672 23.676 18.696 23.76 ;
    END
  END o[23]
  PIN o[240]
    DIRECTION OUTPUT ;
    USE SIGNAL ;
    PORT
      LAYER M5 ;
        RECT  27.984 23.676 28.008 23.76 ;
    END
  END o[240]
  PIN o[241]
    DIRECTION OUTPUT ;
    USE SIGNAL ;
    PORT
      LAYER M5 ;
        RECT  28.08 23.676 28.104 23.76 ;
    END
  END o[241]
  PIN o[242]
    DIRECTION OUTPUT ;
    USE SIGNAL ;
    PORT
      LAYER M5 ;
        RECT  28.176 23.676 28.2 23.76 ;
    END
  END o[242]
  PIN o[243]
    DIRECTION OUTPUT ;
    USE SIGNAL ;
    PORT
      LAYER M5 ;
        RECT  28.272 23.676 28.296 23.76 ;
    END
  END o[243]
  PIN o[244]
    DIRECTION OUTPUT ;
    USE SIGNAL ;
    PORT
      LAYER M5 ;
        RECT  28.368 23.676 28.392 23.76 ;
    END
  END o[244]
  PIN o[245]
    DIRECTION OUTPUT ;
    USE SIGNAL ;
    PORT
      LAYER M5 ;
        RECT  28.464 23.676 28.488 23.76 ;
    END
  END o[245]
  PIN o[246]
    DIRECTION OUTPUT ;
    USE SIGNAL ;
    PORT
      LAYER M5 ;
        RECT  28.56 23.676 28.584 23.76 ;
    END
  END o[246]
  PIN o[247]
    DIRECTION OUTPUT ;
    USE SIGNAL ;
    PORT
      LAYER M5 ;
        RECT  28.656 23.676 28.68 23.76 ;
    END
  END o[247]
  PIN o[248]
    DIRECTION OUTPUT ;
    USE SIGNAL ;
    PORT
      LAYER M5 ;
        RECT  28.752 23.676 28.776 23.76 ;
    END
  END o[248]
  PIN o[249]
    DIRECTION OUTPUT ;
    USE SIGNAL ;
    PORT
      LAYER M5 ;
        RECT  28.848 23.676 28.872 23.76 ;
    END
  END o[249]
  PIN o[24]
    DIRECTION OUTPUT ;
    USE SIGNAL ;
    PORT
      LAYER M5 ;
        RECT  18.768 23.676 18.792 23.76 ;
    END
  END o[24]
  PIN o[250]
    DIRECTION OUTPUT ;
    USE SIGNAL ;
    PORT
      LAYER M5 ;
        RECT  28.944 23.676 28.968 23.76 ;
    END
  END o[250]
  PIN o[251]
    DIRECTION OUTPUT ;
    USE SIGNAL ;
    PORT
      LAYER M5 ;
        RECT  29.04 23.676 29.064 23.76 ;
    END
  END o[251]
  PIN o[252]
    DIRECTION OUTPUT ;
    USE SIGNAL ;
    PORT
      LAYER M5 ;
        RECT  29.136 23.676 29.16 23.76 ;
    END
  END o[252]
  PIN o[253]
    DIRECTION OUTPUT ;
    USE SIGNAL ;
    PORT
      LAYER M5 ;
        RECT  29.232 23.676 29.256 23.76 ;
    END
  END o[253]
  PIN o[254]
    DIRECTION OUTPUT ;
    USE SIGNAL ;
    PORT
      LAYER M5 ;
        RECT  29.328 23.676 29.352 23.76 ;
    END
  END o[254]
  PIN o[255]
    DIRECTION OUTPUT ;
    USE SIGNAL ;
    PORT
      LAYER M5 ;
        RECT  29.424 23.676 29.448 23.76 ;
    END
  END o[255]
  PIN o[256]
    DIRECTION OUTPUT ;
    USE SIGNAL ;
    PORT
      LAYER M5 ;
        RECT  38.736 23.676 38.76 23.76 ;
    END
  END o[256]
  PIN o[257]
    DIRECTION OUTPUT ;
    USE SIGNAL ;
    PORT
      LAYER M5 ;
        RECT  38.832 23.676 38.856 23.76 ;
    END
  END o[257]
  PIN o[258]
    DIRECTION OUTPUT ;
    USE SIGNAL ;
    PORT
      LAYER M5 ;
        RECT  38.928 23.676 38.952 23.76 ;
    END
  END o[258]
  PIN o[259]
    DIRECTION OUTPUT ;
    USE SIGNAL ;
    PORT
      LAYER M5 ;
        RECT  39.024 23.676 39.048 23.76 ;
    END
  END o[259]
  PIN o[25]
    DIRECTION OUTPUT ;
    USE SIGNAL ;
    PORT
      LAYER M5 ;
        RECT  18.864 23.676 18.888 23.76 ;
    END
  END o[25]
  PIN o[260]
    DIRECTION OUTPUT ;
    USE SIGNAL ;
    PORT
      LAYER M5 ;
        RECT  39.12 23.676 39.144 23.76 ;
    END
  END o[260]
  PIN o[261]
    DIRECTION OUTPUT ;
    USE SIGNAL ;
    PORT
      LAYER M5 ;
        RECT  39.216 23.676 39.24 23.76 ;
    END
  END o[261]
  PIN o[262]
    DIRECTION OUTPUT ;
    USE SIGNAL ;
    PORT
      LAYER M5 ;
        RECT  39.312 23.676 39.336 23.76 ;
    END
  END o[262]
  PIN o[263]
    DIRECTION OUTPUT ;
    USE SIGNAL ;
    PORT
      LAYER M5 ;
        RECT  39.408 23.676 39.432 23.76 ;
    END
  END o[263]
  PIN o[264]
    DIRECTION OUTPUT ;
    USE SIGNAL ;
    PORT
      LAYER M5 ;
        RECT  39.504 23.676 39.528 23.76 ;
    END
  END o[264]
  PIN o[265]
    DIRECTION OUTPUT ;
    USE SIGNAL ;
    PORT
      LAYER M5 ;
        RECT  39.6 23.676 39.624 23.76 ;
    END
  END o[265]
  PIN o[266]
    DIRECTION OUTPUT ;
    USE SIGNAL ;
    PORT
      LAYER M5 ;
        RECT  39.696 23.676 39.72 23.76 ;
    END
  END o[266]
  PIN o[267]
    DIRECTION OUTPUT ;
    USE SIGNAL ;
    PORT
      LAYER M5 ;
        RECT  39.792 23.676 39.816 23.76 ;
    END
  END o[267]
  PIN o[268]
    DIRECTION OUTPUT ;
    USE SIGNAL ;
    PORT
      LAYER M5 ;
        RECT  39.888 23.676 39.912 23.76 ;
    END
  END o[268]
  PIN o[269]
    DIRECTION OUTPUT ;
    USE SIGNAL ;
    PORT
      LAYER M5 ;
        RECT  39.984 23.676 40.008 23.76 ;
    END
  END o[269]
  PIN o[26]
    DIRECTION OUTPUT ;
    USE SIGNAL ;
    PORT
      LAYER M5 ;
        RECT  18.96 23.676 18.984 23.76 ;
    END
  END o[26]
  PIN o[270]
    DIRECTION OUTPUT ;
    USE SIGNAL ;
    PORT
      LAYER M5 ;
        RECT  40.08 23.676 40.104 23.76 ;
    END
  END o[270]
  PIN o[271]
    DIRECTION OUTPUT ;
    USE SIGNAL ;
    PORT
      LAYER M5 ;
        RECT  40.176 23.676 40.2 23.76 ;
    END
  END o[271]
  PIN o[272]
    DIRECTION OUTPUT ;
    USE SIGNAL ;
    PORT
      LAYER M5 ;
        RECT  40.272 23.676 40.296 23.76 ;
    END
  END o[272]
  PIN o[273]
    DIRECTION OUTPUT ;
    USE SIGNAL ;
    PORT
      LAYER M5 ;
        RECT  40.368 23.676 40.392 23.76 ;
    END
  END o[273]
  PIN o[274]
    DIRECTION OUTPUT ;
    USE SIGNAL ;
    PORT
      LAYER M5 ;
        RECT  40.464 23.676 40.488 23.76 ;
    END
  END o[274]
  PIN o[275]
    DIRECTION OUTPUT ;
    USE SIGNAL ;
    PORT
      LAYER M5 ;
        RECT  40.56 23.676 40.584 23.76 ;
    END
  END o[275]
  PIN o[276]
    DIRECTION OUTPUT ;
    USE SIGNAL ;
    PORT
      LAYER M5 ;
        RECT  40.656 23.676 40.68 23.76 ;
    END
  END o[276]
  PIN o[277]
    DIRECTION OUTPUT ;
    USE SIGNAL ;
    PORT
      LAYER M5 ;
        RECT  40.752 23.676 40.776 23.76 ;
    END
  END o[277]
  PIN o[278]
    DIRECTION OUTPUT ;
    USE SIGNAL ;
    PORT
      LAYER M5 ;
        RECT  40.848 23.676 40.872 23.76 ;
    END
  END o[278]
  PIN o[279]
    DIRECTION OUTPUT ;
    USE SIGNAL ;
    PORT
      LAYER M5 ;
        RECT  40.944 23.676 40.968 23.76 ;
    END
  END o[279]
  PIN o[27]
    DIRECTION OUTPUT ;
    USE SIGNAL ;
    PORT
      LAYER M5 ;
        RECT  19.056 23.676 19.08 23.76 ;
    END
  END o[27]
  PIN o[280]
    DIRECTION OUTPUT ;
    USE SIGNAL ;
    PORT
      LAYER M5 ;
        RECT  41.04 23.676 41.064 23.76 ;
    END
  END o[280]
  PIN o[281]
    DIRECTION OUTPUT ;
    USE SIGNAL ;
    PORT
      LAYER M5 ;
        RECT  41.136 23.676 41.16 23.76 ;
    END
  END o[281]
  PIN o[282]
    DIRECTION OUTPUT ;
    USE SIGNAL ;
    PORT
      LAYER M5 ;
        RECT  41.232 23.676 41.256 23.76 ;
    END
  END o[282]
  PIN o[283]
    DIRECTION OUTPUT ;
    USE SIGNAL ;
    PORT
      LAYER M5 ;
        RECT  41.328 23.676 41.352 23.76 ;
    END
  END o[283]
  PIN o[284]
    DIRECTION OUTPUT ;
    USE SIGNAL ;
    PORT
      LAYER M5 ;
        RECT  41.424 23.676 41.448 23.76 ;
    END
  END o[284]
  PIN o[285]
    DIRECTION OUTPUT ;
    USE SIGNAL ;
    PORT
      LAYER M5 ;
        RECT  41.52 23.676 41.544 23.76 ;
    END
  END o[285]
  PIN o[286]
    DIRECTION OUTPUT ;
    USE SIGNAL ;
    PORT
      LAYER M5 ;
        RECT  41.616 23.676 41.64 23.76 ;
    END
  END o[286]
  PIN o[287]
    DIRECTION OUTPUT ;
    USE SIGNAL ;
    PORT
      LAYER M5 ;
        RECT  41.712 23.676 41.736 23.76 ;
    END
  END o[287]
  PIN o[288]
    DIRECTION OUTPUT ;
    USE SIGNAL ;
    PORT
      LAYER M5 ;
        RECT  41.808 23.676 41.832 23.76 ;
    END
  END o[288]
  PIN o[289]
    DIRECTION OUTPUT ;
    USE SIGNAL ;
    PORT
      LAYER M5 ;
        RECT  41.904 23.676 41.928 23.76 ;
    END
  END o[289]
  PIN o[28]
    DIRECTION OUTPUT ;
    USE SIGNAL ;
    PORT
      LAYER M5 ;
        RECT  19.152 23.676 19.176 23.76 ;
    END
  END o[28]
  PIN o[290]
    DIRECTION OUTPUT ;
    USE SIGNAL ;
    PORT
      LAYER M5 ;
        RECT  42 23.676 42.024 23.76 ;
    END
  END o[290]
  PIN o[291]
    DIRECTION OUTPUT ;
    USE SIGNAL ;
    PORT
      LAYER M5 ;
        RECT  42.096 23.676 42.12 23.76 ;
    END
  END o[291]
  PIN o[292]
    DIRECTION OUTPUT ;
    USE SIGNAL ;
    PORT
      LAYER M5 ;
        RECT  42.192 23.676 42.216 23.76 ;
    END
  END o[292]
  PIN o[293]
    DIRECTION OUTPUT ;
    USE SIGNAL ;
    PORT
      LAYER M5 ;
        RECT  42.288 23.676 42.312 23.76 ;
    END
  END o[293]
  PIN o[294]
    DIRECTION OUTPUT ;
    USE SIGNAL ;
    PORT
      LAYER M5 ;
        RECT  42.384 23.676 42.408 23.76 ;
    END
  END o[294]
  PIN o[295]
    DIRECTION OUTPUT ;
    USE SIGNAL ;
    PORT
      LAYER M5 ;
        RECT  42.48 23.676 42.504 23.76 ;
    END
  END o[295]
  PIN o[296]
    DIRECTION OUTPUT ;
    USE SIGNAL ;
    PORT
      LAYER M5 ;
        RECT  42.576 23.676 42.6 23.76 ;
    END
  END o[296]
  PIN o[297]
    DIRECTION OUTPUT ;
    USE SIGNAL ;
    PORT
      LAYER M5 ;
        RECT  42.672 23.676 42.696 23.76 ;
    END
  END o[297]
  PIN o[298]
    DIRECTION OUTPUT ;
    USE SIGNAL ;
    PORT
      LAYER M5 ;
        RECT  42.768 23.676 42.792 23.76 ;
    END
  END o[298]
  PIN o[299]
    DIRECTION OUTPUT ;
    USE SIGNAL ;
    PORT
      LAYER M5 ;
        RECT  42.864 23.676 42.888 23.76 ;
    END
  END o[299]
  PIN o[29]
    DIRECTION OUTPUT ;
    USE SIGNAL ;
    PORT
      LAYER M5 ;
        RECT  19.248 23.676 19.272 23.76 ;
    END
  END o[29]
  PIN o[2]
    DIRECTION OUTPUT ;
    USE SIGNAL ;
    PORT
      LAYER M5 ;
        RECT  16.656 23.676 16.68 23.76 ;
    END
  END o[2]
  PIN o[300]
    DIRECTION OUTPUT ;
    USE SIGNAL ;
    PORT
      LAYER M5 ;
        RECT  42.96 23.676 42.984 23.76 ;
    END
  END o[300]
  PIN o[301]
    DIRECTION OUTPUT ;
    USE SIGNAL ;
    PORT
      LAYER M5 ;
        RECT  43.056 23.676 43.08 23.76 ;
    END
  END o[301]
  PIN o[302]
    DIRECTION OUTPUT ;
    USE SIGNAL ;
    PORT
      LAYER M5 ;
        RECT  43.152 23.676 43.176 23.76 ;
    END
  END o[302]
  PIN o[303]
    DIRECTION OUTPUT ;
    USE SIGNAL ;
    PORT
      LAYER M5 ;
        RECT  43.248 23.676 43.272 23.76 ;
    END
  END o[303]
  PIN o[304]
    DIRECTION OUTPUT ;
    USE SIGNAL ;
    PORT
      LAYER M5 ;
        RECT  43.344 23.676 43.368 23.76 ;
    END
  END o[304]
  PIN o[305]
    DIRECTION OUTPUT ;
    USE SIGNAL ;
    PORT
      LAYER M5 ;
        RECT  43.44 23.676 43.464 23.76 ;
    END
  END o[305]
  PIN o[306]
    DIRECTION OUTPUT ;
    USE SIGNAL ;
    PORT
      LAYER M5 ;
        RECT  43.536 23.676 43.56 23.76 ;
    END
  END o[306]
  PIN o[307]
    DIRECTION OUTPUT ;
    USE SIGNAL ;
    PORT
      LAYER M5 ;
        RECT  43.632 23.676 43.656 23.76 ;
    END
  END o[307]
  PIN o[308]
    DIRECTION OUTPUT ;
    USE SIGNAL ;
    PORT
      LAYER M5 ;
        RECT  43.728 23.676 43.752 23.76 ;
    END
  END o[308]
  PIN o[309]
    DIRECTION OUTPUT ;
    USE SIGNAL ;
    PORT
      LAYER M5 ;
        RECT  43.824 23.676 43.848 23.76 ;
    END
  END o[309]
  PIN o[30]
    DIRECTION OUTPUT ;
    USE SIGNAL ;
    PORT
      LAYER M5 ;
        RECT  19.344 23.676 19.368 23.76 ;
    END
  END o[30]
  PIN o[310]
    DIRECTION OUTPUT ;
    USE SIGNAL ;
    PORT
      LAYER M5 ;
        RECT  43.92 23.676 43.944 23.76 ;
    END
  END o[310]
  PIN o[311]
    DIRECTION OUTPUT ;
    USE SIGNAL ;
    PORT
      LAYER M5 ;
        RECT  44.016 23.676 44.04 23.76 ;
    END
  END o[311]
  PIN o[312]
    DIRECTION OUTPUT ;
    USE SIGNAL ;
    PORT
      LAYER M5 ;
        RECT  44.112 23.676 44.136 23.76 ;
    END
  END o[312]
  PIN o[313]
    DIRECTION OUTPUT ;
    USE SIGNAL ;
    PORT
      LAYER M5 ;
        RECT  44.208 23.676 44.232 23.76 ;
    END
  END o[313]
  PIN o[314]
    DIRECTION OUTPUT ;
    USE SIGNAL ;
    PORT
      LAYER M5 ;
        RECT  44.304 23.676 44.328 23.76 ;
    END
  END o[314]
  PIN o[315]
    DIRECTION OUTPUT ;
    USE SIGNAL ;
    PORT
      LAYER M5 ;
        RECT  44.4 23.676 44.424 23.76 ;
    END
  END o[315]
  PIN o[316]
    DIRECTION OUTPUT ;
    USE SIGNAL ;
    PORT
      LAYER M5 ;
        RECT  44.496 23.676 44.52 23.76 ;
    END
  END o[316]
  PIN o[317]
    DIRECTION OUTPUT ;
    USE SIGNAL ;
    PORT
      LAYER M5 ;
        RECT  44.592 23.676 44.616 23.76 ;
    END
  END o[317]
  PIN o[318]
    DIRECTION OUTPUT ;
    USE SIGNAL ;
    PORT
      LAYER M5 ;
        RECT  44.688 23.676 44.712 23.76 ;
    END
  END o[318]
  PIN o[319]
    DIRECTION OUTPUT ;
    USE SIGNAL ;
    PORT
      LAYER M5 ;
        RECT  44.784 23.676 44.808 23.76 ;
    END
  END o[319]
  PIN o[31]
    DIRECTION OUTPUT ;
    USE SIGNAL ;
    PORT
      LAYER M5 ;
        RECT  19.44 23.676 19.464 23.76 ;
    END
  END o[31]
  PIN o[320]
    DIRECTION OUTPUT ;
    USE SIGNAL ;
    PORT
      LAYER M5 ;
        RECT  32.592 23.676 32.616 23.76 ;
    END
  END o[320]
  PIN o[321]
    DIRECTION OUTPUT ;
    USE SIGNAL ;
    PORT
      LAYER M5 ;
        RECT  32.688 23.676 32.712 23.76 ;
    END
  END o[321]
  PIN o[322]
    DIRECTION OUTPUT ;
    USE SIGNAL ;
    PORT
      LAYER M5 ;
        RECT  32.784 23.676 32.808 23.76 ;
    END
  END o[322]
  PIN o[323]
    DIRECTION OUTPUT ;
    USE SIGNAL ;
    PORT
      LAYER M5 ;
        RECT  32.88 23.676 32.904 23.76 ;
    END
  END o[323]
  PIN o[324]
    DIRECTION OUTPUT ;
    USE SIGNAL ;
    PORT
      LAYER M5 ;
        RECT  32.976 23.676 33 23.76 ;
    END
  END o[324]
  PIN o[325]
    DIRECTION OUTPUT ;
    USE SIGNAL ;
    PORT
      LAYER M5 ;
        RECT  33.072 23.676 33.096 23.76 ;
    END
  END o[325]
  PIN o[326]
    DIRECTION OUTPUT ;
    USE SIGNAL ;
    PORT
      LAYER M5 ;
        RECT  33.168 23.676 33.192 23.76 ;
    END
  END o[326]
  PIN o[327]
    DIRECTION OUTPUT ;
    USE SIGNAL ;
    PORT
      LAYER M5 ;
        RECT  33.264 23.676 33.288 23.76 ;
    END
  END o[327]
  PIN o[328]
    DIRECTION OUTPUT ;
    USE SIGNAL ;
    PORT
      LAYER M5 ;
        RECT  33.36 23.676 33.384 23.76 ;
    END
  END o[328]
  PIN o[329]
    DIRECTION OUTPUT ;
    USE SIGNAL ;
    PORT
      LAYER M5 ;
        RECT  33.456 23.676 33.48 23.76 ;
    END
  END o[329]
  PIN o[32]
    DIRECTION OUTPUT ;
    USE SIGNAL ;
    PORT
      LAYER M5 ;
        RECT  13.392 23.676 13.416 23.76 ;
    END
  END o[32]
  PIN o[330]
    DIRECTION OUTPUT ;
    USE SIGNAL ;
    PORT
      LAYER M5 ;
        RECT  33.552 23.676 33.576 23.76 ;
    END
  END o[330]
  PIN o[331]
    DIRECTION OUTPUT ;
    USE SIGNAL ;
    PORT
      LAYER M5 ;
        RECT  33.648 23.676 33.672 23.76 ;
    END
  END o[331]
  PIN o[332]
    DIRECTION OUTPUT ;
    USE SIGNAL ;
    PORT
      LAYER M5 ;
        RECT  33.744 23.676 33.768 23.76 ;
    END
  END o[332]
  PIN o[333]
    DIRECTION OUTPUT ;
    USE SIGNAL ;
    PORT
      LAYER M5 ;
        RECT  33.84 23.676 33.864 23.76 ;
    END
  END o[333]
  PIN o[334]
    DIRECTION OUTPUT ;
    USE SIGNAL ;
    PORT
      LAYER M5 ;
        RECT  33.936 23.676 33.96 23.76 ;
    END
  END o[334]
  PIN o[335]
    DIRECTION OUTPUT ;
    USE SIGNAL ;
    PORT
      LAYER M5 ;
        RECT  34.032 23.676 34.056 23.76 ;
    END
  END o[335]
  PIN o[336]
    DIRECTION OUTPUT ;
    USE SIGNAL ;
    PORT
      LAYER M5 ;
        RECT  34.128 23.676 34.152 23.76 ;
    END
  END o[336]
  PIN o[337]
    DIRECTION OUTPUT ;
    USE SIGNAL ;
    PORT
      LAYER M5 ;
        RECT  34.224 23.676 34.248 23.76 ;
    END
  END o[337]
  PIN o[338]
    DIRECTION OUTPUT ;
    USE SIGNAL ;
    PORT
      LAYER M5 ;
        RECT  34.32 23.676 34.344 23.76 ;
    END
  END o[338]
  PIN o[339]
    DIRECTION OUTPUT ;
    USE SIGNAL ;
    PORT
      LAYER M5 ;
        RECT  34.416 23.676 34.44 23.76 ;
    END
  END o[339]
  PIN o[33]
    DIRECTION OUTPUT ;
    USE SIGNAL ;
    PORT
      LAYER M5 ;
        RECT  13.488 23.676 13.512 23.76 ;
    END
  END o[33]
  PIN o[340]
    DIRECTION OUTPUT ;
    USE SIGNAL ;
    PORT
      LAYER M5 ;
        RECT  34.512 23.676 34.536 23.76 ;
    END
  END o[340]
  PIN o[341]
    DIRECTION OUTPUT ;
    USE SIGNAL ;
    PORT
      LAYER M5 ;
        RECT  34.608 23.676 34.632 23.76 ;
    END
  END o[341]
  PIN o[342]
    DIRECTION OUTPUT ;
    USE SIGNAL ;
    PORT
      LAYER M5 ;
        RECT  34.704 23.676 34.728 23.76 ;
    END
  END o[342]
  PIN o[343]
    DIRECTION OUTPUT ;
    USE SIGNAL ;
    PORT
      LAYER M5 ;
        RECT  34.8 23.676 34.824 23.76 ;
    END
  END o[343]
  PIN o[344]
    DIRECTION OUTPUT ;
    USE SIGNAL ;
    PORT
      LAYER M5 ;
        RECT  34.896 23.676 34.92 23.76 ;
    END
  END o[344]
  PIN o[345]
    DIRECTION OUTPUT ;
    USE SIGNAL ;
    PORT
      LAYER M5 ;
        RECT  34.992 23.676 35.016 23.76 ;
    END
  END o[345]
  PIN o[346]
    DIRECTION OUTPUT ;
    USE SIGNAL ;
    PORT
      LAYER M5 ;
        RECT  35.088 23.676 35.112 23.76 ;
    END
  END o[346]
  PIN o[347]
    DIRECTION OUTPUT ;
    USE SIGNAL ;
    PORT
      LAYER M5 ;
        RECT  35.184 23.676 35.208 23.76 ;
    END
  END o[347]
  PIN o[348]
    DIRECTION OUTPUT ;
    USE SIGNAL ;
    PORT
      LAYER M5 ;
        RECT  35.28 23.676 35.304 23.76 ;
    END
  END o[348]
  PIN o[349]
    DIRECTION OUTPUT ;
    USE SIGNAL ;
    PORT
      LAYER M5 ;
        RECT  35.376 23.676 35.4 23.76 ;
    END
  END o[349]
  PIN o[34]
    DIRECTION OUTPUT ;
    USE SIGNAL ;
    PORT
      LAYER M5 ;
        RECT  13.584 23.676 13.608 23.76 ;
    END
  END o[34]
  PIN o[350]
    DIRECTION OUTPUT ;
    USE SIGNAL ;
    PORT
      LAYER M5 ;
        RECT  35.472 23.676 35.496 23.76 ;
    END
  END o[350]
  PIN o[351]
    DIRECTION OUTPUT ;
    USE SIGNAL ;
    PORT
      LAYER M5 ;
        RECT  35.568 23.676 35.592 23.76 ;
    END
  END o[351]
  PIN o[352]
    DIRECTION OUTPUT ;
    USE SIGNAL ;
    PORT
      LAYER M5 ;
        RECT  35.664 23.676 35.688 23.76 ;
    END
  END o[352]
  PIN o[353]
    DIRECTION OUTPUT ;
    USE SIGNAL ;
    PORT
      LAYER M5 ;
        RECT  35.76 23.676 35.784 23.76 ;
    END
  END o[353]
  PIN o[354]
    DIRECTION OUTPUT ;
    USE SIGNAL ;
    PORT
      LAYER M5 ;
        RECT  35.856 23.676 35.88 23.76 ;
    END
  END o[354]
  PIN o[355]
    DIRECTION OUTPUT ;
    USE SIGNAL ;
    PORT
      LAYER M5 ;
        RECT  35.952 23.676 35.976 23.76 ;
    END
  END o[355]
  PIN o[356]
    DIRECTION OUTPUT ;
    USE SIGNAL ;
    PORT
      LAYER M5 ;
        RECT  36.048 23.676 36.072 23.76 ;
    END
  END o[356]
  PIN o[357]
    DIRECTION OUTPUT ;
    USE SIGNAL ;
    PORT
      LAYER M5 ;
        RECT  36.144 23.676 36.168 23.76 ;
    END
  END o[357]
  PIN o[358]
    DIRECTION OUTPUT ;
    USE SIGNAL ;
    PORT
      LAYER M5 ;
        RECT  36.24 23.676 36.264 23.76 ;
    END
  END o[358]
  PIN o[359]
    DIRECTION OUTPUT ;
    USE SIGNAL ;
    PORT
      LAYER M5 ;
        RECT  36.336 23.676 36.36 23.76 ;
    END
  END o[359]
  PIN o[35]
    DIRECTION OUTPUT ;
    USE SIGNAL ;
    PORT
      LAYER M5 ;
        RECT  13.68 23.676 13.704 23.76 ;
    END
  END o[35]
  PIN o[360]
    DIRECTION OUTPUT ;
    USE SIGNAL ;
    PORT
      LAYER M5 ;
        RECT  36.432 23.676 36.456 23.76 ;
    END
  END o[360]
  PIN o[361]
    DIRECTION OUTPUT ;
    USE SIGNAL ;
    PORT
      LAYER M5 ;
        RECT  36.528 23.676 36.552 23.76 ;
    END
  END o[361]
  PIN o[362]
    DIRECTION OUTPUT ;
    USE SIGNAL ;
    PORT
      LAYER M5 ;
        RECT  36.624 23.676 36.648 23.76 ;
    END
  END o[362]
  PIN o[363]
    DIRECTION OUTPUT ;
    USE SIGNAL ;
    PORT
      LAYER M5 ;
        RECT  36.72 23.676 36.744 23.76 ;
    END
  END o[363]
  PIN o[364]
    DIRECTION OUTPUT ;
    USE SIGNAL ;
    PORT
      LAYER M5 ;
        RECT  36.816 23.676 36.84 23.76 ;
    END
  END o[364]
  PIN o[365]
    DIRECTION OUTPUT ;
    USE SIGNAL ;
    PORT
      LAYER M5 ;
        RECT  36.912 23.676 36.936 23.76 ;
    END
  END o[365]
  PIN o[366]
    DIRECTION OUTPUT ;
    USE SIGNAL ;
    PORT
      LAYER M5 ;
        RECT  37.008 23.676 37.032 23.76 ;
    END
  END o[366]
  PIN o[367]
    DIRECTION OUTPUT ;
    USE SIGNAL ;
    PORT
      LAYER M5 ;
        RECT  37.104 23.676 37.128 23.76 ;
    END
  END o[367]
  PIN o[368]
    DIRECTION OUTPUT ;
    USE SIGNAL ;
    PORT
      LAYER M5 ;
        RECT  37.2 23.676 37.224 23.76 ;
    END
  END o[368]
  PIN o[369]
    DIRECTION OUTPUT ;
    USE SIGNAL ;
    PORT
      LAYER M5 ;
        RECT  37.296 23.676 37.32 23.76 ;
    END
  END o[369]
  PIN o[36]
    DIRECTION OUTPUT ;
    USE SIGNAL ;
    PORT
      LAYER M5 ;
        RECT  13.776 23.676 13.8 23.76 ;
    END
  END o[36]
  PIN o[370]
    DIRECTION OUTPUT ;
    USE SIGNAL ;
    PORT
      LAYER M5 ;
        RECT  37.392 23.676 37.416 23.76 ;
    END
  END o[370]
  PIN o[371]
    DIRECTION OUTPUT ;
    USE SIGNAL ;
    PORT
      LAYER M5 ;
        RECT  37.488 23.676 37.512 23.76 ;
    END
  END o[371]
  PIN o[372]
    DIRECTION OUTPUT ;
    USE SIGNAL ;
    PORT
      LAYER M5 ;
        RECT  37.584 23.676 37.608 23.76 ;
    END
  END o[372]
  PIN o[373]
    DIRECTION OUTPUT ;
    USE SIGNAL ;
    PORT
      LAYER M5 ;
        RECT  37.68 23.676 37.704 23.76 ;
    END
  END o[373]
  PIN o[374]
    DIRECTION OUTPUT ;
    USE SIGNAL ;
    PORT
      LAYER M5 ;
        RECT  37.776 23.676 37.8 23.76 ;
    END
  END o[374]
  PIN o[375]
    DIRECTION OUTPUT ;
    USE SIGNAL ;
    PORT
      LAYER M5 ;
        RECT  37.872 23.676 37.896 23.76 ;
    END
  END o[375]
  PIN o[376]
    DIRECTION OUTPUT ;
    USE SIGNAL ;
    PORT
      LAYER M5 ;
        RECT  37.968 23.676 37.992 23.76 ;
    END
  END o[376]
  PIN o[377]
    DIRECTION OUTPUT ;
    USE SIGNAL ;
    PORT
      LAYER M5 ;
        RECT  38.064 23.676 38.088 23.76 ;
    END
  END o[377]
  PIN o[378]
    DIRECTION OUTPUT ;
    USE SIGNAL ;
    PORT
      LAYER M5 ;
        RECT  38.16 23.676 38.184 23.76 ;
    END
  END o[378]
  PIN o[379]
    DIRECTION OUTPUT ;
    USE SIGNAL ;
    PORT
      LAYER M5 ;
        RECT  38.256 23.676 38.28 23.76 ;
    END
  END o[379]
  PIN o[37]
    DIRECTION OUTPUT ;
    USE SIGNAL ;
    PORT
      LAYER M5 ;
        RECT  13.872 23.676 13.896 23.76 ;
    END
  END o[37]
  PIN o[380]
    DIRECTION OUTPUT ;
    USE SIGNAL ;
    PORT
      LAYER M5 ;
        RECT  38.352 23.676 38.376 23.76 ;
    END
  END o[380]
  PIN o[381]
    DIRECTION OUTPUT ;
    USE SIGNAL ;
    PORT
      LAYER M5 ;
        RECT  38.448 23.676 38.472 23.76 ;
    END
  END o[381]
  PIN o[382]
    DIRECTION OUTPUT ;
    USE SIGNAL ;
    PORT
      LAYER M5 ;
        RECT  38.544 23.676 38.568 23.76 ;
    END
  END o[382]
  PIN o[383]
    DIRECTION OUTPUT ;
    USE SIGNAL ;
    PORT
      LAYER M5 ;
        RECT  38.64 23.676 38.664 23.76 ;
    END
  END o[383]
  PIN o[384]
    DIRECTION OUTPUT ;
    USE SIGNAL ;
    PORT
      LAYER M5 ;
        RECT  54.864 23.676 54.888 23.76 ;
    END
  END o[384]
  PIN o[385]
    DIRECTION OUTPUT ;
    USE SIGNAL ;
    PORT
      LAYER M5 ;
        RECT  54.96 23.676 54.984 23.76 ;
    END
  END o[385]
  PIN o[386]
    DIRECTION OUTPUT ;
    USE SIGNAL ;
    PORT
      LAYER M5 ;
        RECT  55.056 23.676 55.08 23.76 ;
    END
  END o[386]
  PIN o[387]
    DIRECTION OUTPUT ;
    USE SIGNAL ;
    PORT
      LAYER M5 ;
        RECT  55.152 23.676 55.176 23.76 ;
    END
  END o[387]
  PIN o[388]
    DIRECTION OUTPUT ;
    USE SIGNAL ;
    PORT
      LAYER M5 ;
        RECT  55.248 23.676 55.272 23.76 ;
    END
  END o[388]
  PIN o[389]
    DIRECTION OUTPUT ;
    USE SIGNAL ;
    PORT
      LAYER M5 ;
        RECT  55.344 23.676 55.368 23.76 ;
    END
  END o[389]
  PIN o[38]
    DIRECTION OUTPUT ;
    USE SIGNAL ;
    PORT
      LAYER M5 ;
        RECT  13.968 23.676 13.992 23.76 ;
    END
  END o[38]
  PIN o[390]
    DIRECTION OUTPUT ;
    USE SIGNAL ;
    PORT
      LAYER M5 ;
        RECT  55.44 23.676 55.464 23.76 ;
    END
  END o[390]
  PIN o[391]
    DIRECTION OUTPUT ;
    USE SIGNAL ;
    PORT
      LAYER M5 ;
        RECT  55.536 23.676 55.56 23.76 ;
    END
  END o[391]
  PIN o[392]
    DIRECTION OUTPUT ;
    USE SIGNAL ;
    PORT
      LAYER M5 ;
        RECT  55.632 23.676 55.656 23.76 ;
    END
  END o[392]
  PIN o[393]
    DIRECTION OUTPUT ;
    USE SIGNAL ;
    PORT
      LAYER M5 ;
        RECT  55.728 23.676 55.752 23.76 ;
    END
  END o[393]
  PIN o[394]
    DIRECTION OUTPUT ;
    USE SIGNAL ;
    PORT
      LAYER M5 ;
        RECT  55.824 23.676 55.848 23.76 ;
    END
  END o[394]
  PIN o[395]
    DIRECTION OUTPUT ;
    USE SIGNAL ;
    PORT
      LAYER M5 ;
        RECT  55.92 23.676 55.944 23.76 ;
    END
  END o[395]
  PIN o[396]
    DIRECTION OUTPUT ;
    USE SIGNAL ;
    PORT
      LAYER M5 ;
        RECT  56.016 23.676 56.04 23.76 ;
    END
  END o[396]
  PIN o[397]
    DIRECTION OUTPUT ;
    USE SIGNAL ;
    PORT
      LAYER M5 ;
        RECT  56.112 23.676 56.136 23.76 ;
    END
  END o[397]
  PIN o[398]
    DIRECTION OUTPUT ;
    USE SIGNAL ;
    PORT
      LAYER M5 ;
        RECT  56.208 23.676 56.232 23.76 ;
    END
  END o[398]
  PIN o[399]
    DIRECTION OUTPUT ;
    USE SIGNAL ;
    PORT
      LAYER M5 ;
        RECT  56.304 23.676 56.328 23.76 ;
    END
  END o[399]
  PIN o[39]
    DIRECTION OUTPUT ;
    USE SIGNAL ;
    PORT
      LAYER M5 ;
        RECT  14.064 23.676 14.088 23.76 ;
    END
  END o[39]
  PIN o[3]
    DIRECTION OUTPUT ;
    USE SIGNAL ;
    PORT
      LAYER M5 ;
        RECT  16.752 23.676 16.776 23.76 ;
    END
  END o[3]
  PIN o[400]
    DIRECTION OUTPUT ;
    USE SIGNAL ;
    PORT
      LAYER M5 ;
        RECT  56.4 23.676 56.424 23.76 ;
    END
  END o[400]
  PIN o[401]
    DIRECTION OUTPUT ;
    USE SIGNAL ;
    PORT
      LAYER M5 ;
        RECT  56.496 23.676 56.52 23.76 ;
    END
  END o[401]
  PIN o[402]
    DIRECTION OUTPUT ;
    USE SIGNAL ;
    PORT
      LAYER M5 ;
        RECT  56.592 23.676 56.616 23.76 ;
    END
  END o[402]
  PIN o[403]
    DIRECTION OUTPUT ;
    USE SIGNAL ;
    PORT
      LAYER M5 ;
        RECT  56.688 23.676 56.712 23.76 ;
    END
  END o[403]
  PIN o[404]
    DIRECTION OUTPUT ;
    USE SIGNAL ;
    PORT
      LAYER M5 ;
        RECT  56.784 23.676 56.808 23.76 ;
    END
  END o[404]
  PIN o[405]
    DIRECTION OUTPUT ;
    USE SIGNAL ;
    PORT
      LAYER M5 ;
        RECT  56.88 23.676 56.904 23.76 ;
    END
  END o[405]
  PIN o[406]
    DIRECTION OUTPUT ;
    USE SIGNAL ;
    PORT
      LAYER M5 ;
        RECT  56.976 23.676 57 23.76 ;
    END
  END o[406]
  PIN o[407]
    DIRECTION OUTPUT ;
    USE SIGNAL ;
    PORT
      LAYER M5 ;
        RECT  57.072 23.676 57.096 23.76 ;
    END
  END o[407]
  PIN o[408]
    DIRECTION OUTPUT ;
    USE SIGNAL ;
    PORT
      LAYER M5 ;
        RECT  57.168 23.676 57.192 23.76 ;
    END
  END o[408]
  PIN o[409]
    DIRECTION OUTPUT ;
    USE SIGNAL ;
    PORT
      LAYER M5 ;
        RECT  57.264 23.676 57.288 23.76 ;
    END
  END o[409]
  PIN o[40]
    DIRECTION OUTPUT ;
    USE SIGNAL ;
    PORT
      LAYER M5 ;
        RECT  14.16 23.676 14.184 23.76 ;
    END
  END o[40]
  PIN o[410]
    DIRECTION OUTPUT ;
    USE SIGNAL ;
    PORT
      LAYER M5 ;
        RECT  57.36 23.676 57.384 23.76 ;
    END
  END o[410]
  PIN o[411]
    DIRECTION OUTPUT ;
    USE SIGNAL ;
    PORT
      LAYER M5 ;
        RECT  57.456 23.676 57.48 23.76 ;
    END
  END o[411]
  PIN o[412]
    DIRECTION OUTPUT ;
    USE SIGNAL ;
    PORT
      LAYER M5 ;
        RECT  57.552 23.676 57.576 23.76 ;
    END
  END o[412]
  PIN o[413]
    DIRECTION OUTPUT ;
    USE SIGNAL ;
    PORT
      LAYER M5 ;
        RECT  57.648 23.676 57.672 23.76 ;
    END
  END o[413]
  PIN o[414]
    DIRECTION OUTPUT ;
    USE SIGNAL ;
    PORT
      LAYER M5 ;
        RECT  57.744 23.676 57.768 23.76 ;
    END
  END o[414]
  PIN o[415]
    DIRECTION OUTPUT ;
    USE SIGNAL ;
    PORT
      LAYER M5 ;
        RECT  57.84 23.676 57.864 23.76 ;
    END
  END o[415]
  PIN o[416]
    DIRECTION OUTPUT ;
    USE SIGNAL ;
    PORT
      LAYER M5 ;
        RECT  51.792 23.676 51.816 23.76 ;
    END
  END o[416]
  PIN o[417]
    DIRECTION OUTPUT ;
    USE SIGNAL ;
    PORT
      LAYER M5 ;
        RECT  51.888 23.676 51.912 23.76 ;
    END
  END o[417]
  PIN o[418]
    DIRECTION OUTPUT ;
    USE SIGNAL ;
    PORT
      LAYER M5 ;
        RECT  51.984 23.676 52.008 23.76 ;
    END
  END o[418]
  PIN o[419]
    DIRECTION OUTPUT ;
    USE SIGNAL ;
    PORT
      LAYER M5 ;
        RECT  52.08 23.676 52.104 23.76 ;
    END
  END o[419]
  PIN o[41]
    DIRECTION OUTPUT ;
    USE SIGNAL ;
    PORT
      LAYER M5 ;
        RECT  14.256 23.676 14.28 23.76 ;
    END
  END o[41]
  PIN o[420]
    DIRECTION OUTPUT ;
    USE SIGNAL ;
    PORT
      LAYER M5 ;
        RECT  52.176 23.676 52.2 23.76 ;
    END
  END o[420]
  PIN o[421]
    DIRECTION OUTPUT ;
    USE SIGNAL ;
    PORT
      LAYER M5 ;
        RECT  52.272 23.676 52.296 23.76 ;
    END
  END o[421]
  PIN o[422]
    DIRECTION OUTPUT ;
    USE SIGNAL ;
    PORT
      LAYER M5 ;
        RECT  52.368 23.676 52.392 23.76 ;
    END
  END o[422]
  PIN o[423]
    DIRECTION OUTPUT ;
    USE SIGNAL ;
    PORT
      LAYER M5 ;
        RECT  52.464 23.676 52.488 23.76 ;
    END
  END o[423]
  PIN o[424]
    DIRECTION OUTPUT ;
    USE SIGNAL ;
    PORT
      LAYER M5 ;
        RECT  52.56 23.676 52.584 23.76 ;
    END
  END o[424]
  PIN o[425]
    DIRECTION OUTPUT ;
    USE SIGNAL ;
    PORT
      LAYER M5 ;
        RECT  52.656 23.676 52.68 23.76 ;
    END
  END o[425]
  PIN o[426]
    DIRECTION OUTPUT ;
    USE SIGNAL ;
    PORT
      LAYER M5 ;
        RECT  52.752 23.676 52.776 23.76 ;
    END
  END o[426]
  PIN o[427]
    DIRECTION OUTPUT ;
    USE SIGNAL ;
    PORT
      LAYER M5 ;
        RECT  52.848 23.676 52.872 23.76 ;
    END
  END o[427]
  PIN o[428]
    DIRECTION OUTPUT ;
    USE SIGNAL ;
    PORT
      LAYER M5 ;
        RECT  52.944 23.676 52.968 23.76 ;
    END
  END o[428]
  PIN o[429]
    DIRECTION OUTPUT ;
    USE SIGNAL ;
    PORT
      LAYER M5 ;
        RECT  53.04 23.676 53.064 23.76 ;
    END
  END o[429]
  PIN o[42]
    DIRECTION OUTPUT ;
    USE SIGNAL ;
    PORT
      LAYER M5 ;
        RECT  14.352 23.676 14.376 23.76 ;
    END
  END o[42]
  PIN o[430]
    DIRECTION OUTPUT ;
    USE SIGNAL ;
    PORT
      LAYER M5 ;
        RECT  53.136 23.676 53.16 23.76 ;
    END
  END o[430]
  PIN o[431]
    DIRECTION OUTPUT ;
    USE SIGNAL ;
    PORT
      LAYER M5 ;
        RECT  53.232 23.676 53.256 23.76 ;
    END
  END o[431]
  PIN o[432]
    DIRECTION OUTPUT ;
    USE SIGNAL ;
    PORT
      LAYER M5 ;
        RECT  53.328 23.676 53.352 23.76 ;
    END
  END o[432]
  PIN o[433]
    DIRECTION OUTPUT ;
    USE SIGNAL ;
    PORT
      LAYER M5 ;
        RECT  53.424 23.676 53.448 23.76 ;
    END
  END o[433]
  PIN o[434]
    DIRECTION OUTPUT ;
    USE SIGNAL ;
    PORT
      LAYER M5 ;
        RECT  53.52 23.676 53.544 23.76 ;
    END
  END o[434]
  PIN o[435]
    DIRECTION OUTPUT ;
    USE SIGNAL ;
    PORT
      LAYER M5 ;
        RECT  53.616 23.676 53.64 23.76 ;
    END
  END o[435]
  PIN o[436]
    DIRECTION OUTPUT ;
    USE SIGNAL ;
    PORT
      LAYER M5 ;
        RECT  53.712 23.676 53.736 23.76 ;
    END
  END o[436]
  PIN o[437]
    DIRECTION OUTPUT ;
    USE SIGNAL ;
    PORT
      LAYER M5 ;
        RECT  53.808 23.676 53.832 23.76 ;
    END
  END o[437]
  PIN o[438]
    DIRECTION OUTPUT ;
    USE SIGNAL ;
    PORT
      LAYER M5 ;
        RECT  53.904 23.676 53.928 23.76 ;
    END
  END o[438]
  PIN o[439]
    DIRECTION OUTPUT ;
    USE SIGNAL ;
    PORT
      LAYER M5 ;
        RECT  54 23.676 54.024 23.76 ;
    END
  END o[439]
  PIN o[43]
    DIRECTION OUTPUT ;
    USE SIGNAL ;
    PORT
      LAYER M5 ;
        RECT  14.448 23.676 14.472 23.76 ;
    END
  END o[43]
  PIN o[440]
    DIRECTION OUTPUT ;
    USE SIGNAL ;
    PORT
      LAYER M5 ;
        RECT  54.096 23.676 54.12 23.76 ;
    END
  END o[440]
  PIN o[441]
    DIRECTION OUTPUT ;
    USE SIGNAL ;
    PORT
      LAYER M5 ;
        RECT  54.192 23.676 54.216 23.76 ;
    END
  END o[441]
  PIN o[442]
    DIRECTION OUTPUT ;
    USE SIGNAL ;
    PORT
      LAYER M5 ;
        RECT  54.288 23.676 54.312 23.76 ;
    END
  END o[442]
  PIN o[443]
    DIRECTION OUTPUT ;
    USE SIGNAL ;
    PORT
      LAYER M5 ;
        RECT  54.384 23.676 54.408 23.76 ;
    END
  END o[443]
  PIN o[444]
    DIRECTION OUTPUT ;
    USE SIGNAL ;
    PORT
      LAYER M5 ;
        RECT  54.48 23.676 54.504 23.76 ;
    END
  END o[444]
  PIN o[445]
    DIRECTION OUTPUT ;
    USE SIGNAL ;
    PORT
      LAYER M5 ;
        RECT  54.576 23.676 54.6 23.76 ;
    END
  END o[445]
  PIN o[446]
    DIRECTION OUTPUT ;
    USE SIGNAL ;
    PORT
      LAYER M5 ;
        RECT  54.672 23.676 54.696 23.76 ;
    END
  END o[446]
  PIN o[447]
    DIRECTION OUTPUT ;
    USE SIGNAL ;
    PORT
      LAYER M5 ;
        RECT  54.768 23.676 54.792 23.76 ;
    END
  END o[447]
  PIN o[448]
    DIRECTION OUTPUT ;
    USE SIGNAL ;
    PORT
      LAYER M5 ;
        RECT  45.648 23.676 45.672 23.76 ;
    END
  END o[448]
  PIN o[449]
    DIRECTION OUTPUT ;
    USE SIGNAL ;
    PORT
      LAYER M5 ;
        RECT  45.744 23.676 45.768 23.76 ;
    END
  END o[449]
  PIN o[44]
    DIRECTION OUTPUT ;
    USE SIGNAL ;
    PORT
      LAYER M5 ;
        RECT  14.544 23.676 14.568 23.76 ;
    END
  END o[44]
  PIN o[450]
    DIRECTION OUTPUT ;
    USE SIGNAL ;
    PORT
      LAYER M5 ;
        RECT  45.84 23.676 45.864 23.76 ;
    END
  END o[450]
  PIN o[451]
    DIRECTION OUTPUT ;
    USE SIGNAL ;
    PORT
      LAYER M5 ;
        RECT  45.936 23.676 45.96 23.76 ;
    END
  END o[451]
  PIN o[452]
    DIRECTION OUTPUT ;
    USE SIGNAL ;
    PORT
      LAYER M5 ;
        RECT  46.032 23.676 46.056 23.76 ;
    END
  END o[452]
  PIN o[453]
    DIRECTION OUTPUT ;
    USE SIGNAL ;
    PORT
      LAYER M5 ;
        RECT  46.128 23.676 46.152 23.76 ;
    END
  END o[453]
  PIN o[454]
    DIRECTION OUTPUT ;
    USE SIGNAL ;
    PORT
      LAYER M5 ;
        RECT  46.224 23.676 46.248 23.76 ;
    END
  END o[454]
  PIN o[455]
    DIRECTION OUTPUT ;
    USE SIGNAL ;
    PORT
      LAYER M5 ;
        RECT  46.32 23.676 46.344 23.76 ;
    END
  END o[455]
  PIN o[456]
    DIRECTION OUTPUT ;
    USE SIGNAL ;
    PORT
      LAYER M5 ;
        RECT  46.416 23.676 46.44 23.76 ;
    END
  END o[456]
  PIN o[457]
    DIRECTION OUTPUT ;
    USE SIGNAL ;
    PORT
      LAYER M5 ;
        RECT  46.512 23.676 46.536 23.76 ;
    END
  END o[457]
  PIN o[458]
    DIRECTION OUTPUT ;
    USE SIGNAL ;
    PORT
      LAYER M5 ;
        RECT  46.608 23.676 46.632 23.76 ;
    END
  END o[458]
  PIN o[459]
    DIRECTION OUTPUT ;
    USE SIGNAL ;
    PORT
      LAYER M5 ;
        RECT  46.704 23.676 46.728 23.76 ;
    END
  END o[459]
  PIN o[45]
    DIRECTION OUTPUT ;
    USE SIGNAL ;
    PORT
      LAYER M5 ;
        RECT  14.64 23.676 14.664 23.76 ;
    END
  END o[45]
  PIN o[460]
    DIRECTION OUTPUT ;
    USE SIGNAL ;
    PORT
      LAYER M5 ;
        RECT  46.8 23.676 46.824 23.76 ;
    END
  END o[460]
  PIN o[461]
    DIRECTION OUTPUT ;
    USE SIGNAL ;
    PORT
      LAYER M5 ;
        RECT  46.896 23.676 46.92 23.76 ;
    END
  END o[461]
  PIN o[462]
    DIRECTION OUTPUT ;
    USE SIGNAL ;
    PORT
      LAYER M5 ;
        RECT  46.992 23.676 47.016 23.76 ;
    END
  END o[462]
  PIN o[463]
    DIRECTION OUTPUT ;
    USE SIGNAL ;
    PORT
      LAYER M5 ;
        RECT  47.088 23.676 47.112 23.76 ;
    END
  END o[463]
  PIN o[464]
    DIRECTION OUTPUT ;
    USE SIGNAL ;
    PORT
      LAYER M5 ;
        RECT  47.184 23.676 47.208 23.76 ;
    END
  END o[464]
  PIN o[465]
    DIRECTION OUTPUT ;
    USE SIGNAL ;
    PORT
      LAYER M5 ;
        RECT  47.28 23.676 47.304 23.76 ;
    END
  END o[465]
  PIN o[466]
    DIRECTION OUTPUT ;
    USE SIGNAL ;
    PORT
      LAYER M5 ;
        RECT  47.376 23.676 47.4 23.76 ;
    END
  END o[466]
  PIN o[467]
    DIRECTION OUTPUT ;
    USE SIGNAL ;
    PORT
      LAYER M5 ;
        RECT  47.472 23.676 47.496 23.76 ;
    END
  END o[467]
  PIN o[468]
    DIRECTION OUTPUT ;
    USE SIGNAL ;
    PORT
      LAYER M5 ;
        RECT  47.568 23.676 47.592 23.76 ;
    END
  END o[468]
  PIN o[469]
    DIRECTION OUTPUT ;
    USE SIGNAL ;
    PORT
      LAYER M5 ;
        RECT  47.664 23.676 47.688 23.76 ;
    END
  END o[469]
  PIN o[46]
    DIRECTION OUTPUT ;
    USE SIGNAL ;
    PORT
      LAYER M5 ;
        RECT  14.736 23.676 14.76 23.76 ;
    END
  END o[46]
  PIN o[470]
    DIRECTION OUTPUT ;
    USE SIGNAL ;
    PORT
      LAYER M5 ;
        RECT  47.76 23.676 47.784 23.76 ;
    END
  END o[470]
  PIN o[471]
    DIRECTION OUTPUT ;
    USE SIGNAL ;
    PORT
      LAYER M5 ;
        RECT  47.856 23.676 47.88 23.76 ;
    END
  END o[471]
  PIN o[472]
    DIRECTION OUTPUT ;
    USE SIGNAL ;
    PORT
      LAYER M5 ;
        RECT  47.952 23.676 47.976 23.76 ;
    END
  END o[472]
  PIN o[473]
    DIRECTION OUTPUT ;
    USE SIGNAL ;
    PORT
      LAYER M5 ;
        RECT  48.048 23.676 48.072 23.76 ;
    END
  END o[473]
  PIN o[474]
    DIRECTION OUTPUT ;
    USE SIGNAL ;
    PORT
      LAYER M5 ;
        RECT  48.144 23.676 48.168 23.76 ;
    END
  END o[474]
  PIN o[475]
    DIRECTION OUTPUT ;
    USE SIGNAL ;
    PORT
      LAYER M5 ;
        RECT  48.24 23.676 48.264 23.76 ;
    END
  END o[475]
  PIN o[476]
    DIRECTION OUTPUT ;
    USE SIGNAL ;
    PORT
      LAYER M5 ;
        RECT  48.336 23.676 48.36 23.76 ;
    END
  END o[476]
  PIN o[477]
    DIRECTION OUTPUT ;
    USE SIGNAL ;
    PORT
      LAYER M5 ;
        RECT  48.432 23.676 48.456 23.76 ;
    END
  END o[477]
  PIN o[478]
    DIRECTION OUTPUT ;
    USE SIGNAL ;
    PORT
      LAYER M5 ;
        RECT  48.528 23.676 48.552 23.76 ;
    END
  END o[478]
  PIN o[479]
    DIRECTION OUTPUT ;
    USE SIGNAL ;
    PORT
      LAYER M5 ;
        RECT  48.624 23.676 48.648 23.76 ;
    END
  END o[479]
  PIN o[47]
    DIRECTION OUTPUT ;
    USE SIGNAL ;
    PORT
      LAYER M5 ;
        RECT  14.832 23.676 14.856 23.76 ;
    END
  END o[47]
  PIN o[480]
    DIRECTION OUTPUT ;
    USE SIGNAL ;
    PORT
      LAYER M5 ;
        RECT  48.72 23.676 48.744 23.76 ;
    END
  END o[480]
  PIN o[481]
    DIRECTION OUTPUT ;
    USE SIGNAL ;
    PORT
      LAYER M5 ;
        RECT  48.816 23.676 48.84 23.76 ;
    END
  END o[481]
  PIN o[482]
    DIRECTION OUTPUT ;
    USE SIGNAL ;
    PORT
      LAYER M5 ;
        RECT  48.912 23.676 48.936 23.76 ;
    END
  END o[482]
  PIN o[483]
    DIRECTION OUTPUT ;
    USE SIGNAL ;
    PORT
      LAYER M5 ;
        RECT  49.008 23.676 49.032 23.76 ;
    END
  END o[483]
  PIN o[484]
    DIRECTION OUTPUT ;
    USE SIGNAL ;
    PORT
      LAYER M5 ;
        RECT  49.104 23.676 49.128 23.76 ;
    END
  END o[484]
  PIN o[485]
    DIRECTION OUTPUT ;
    USE SIGNAL ;
    PORT
      LAYER M5 ;
        RECT  49.2 23.676 49.224 23.76 ;
    END
  END o[485]
  PIN o[486]
    DIRECTION OUTPUT ;
    USE SIGNAL ;
    PORT
      LAYER M5 ;
        RECT  49.296 23.676 49.32 23.76 ;
    END
  END o[486]
  PIN o[487]
    DIRECTION OUTPUT ;
    USE SIGNAL ;
    PORT
      LAYER M5 ;
        RECT  49.392 23.676 49.416 23.76 ;
    END
  END o[487]
  PIN o[488]
    DIRECTION OUTPUT ;
    USE SIGNAL ;
    PORT
      LAYER M5 ;
        RECT  49.488 23.676 49.512 23.76 ;
    END
  END o[488]
  PIN o[489]
    DIRECTION OUTPUT ;
    USE SIGNAL ;
    PORT
      LAYER M5 ;
        RECT  49.584 23.676 49.608 23.76 ;
    END
  END o[489]
  PIN o[48]
    DIRECTION OUTPUT ;
    USE SIGNAL ;
    PORT
      LAYER M5 ;
        RECT  14.928 23.676 14.952 23.76 ;
    END
  END o[48]
  PIN o[490]
    DIRECTION OUTPUT ;
    USE SIGNAL ;
    PORT
      LAYER M5 ;
        RECT  49.68 23.676 49.704 23.76 ;
    END
  END o[490]
  PIN o[491]
    DIRECTION OUTPUT ;
    USE SIGNAL ;
    PORT
      LAYER M5 ;
        RECT  49.776 23.676 49.8 23.76 ;
    END
  END o[491]
  PIN o[492]
    DIRECTION OUTPUT ;
    USE SIGNAL ;
    PORT
      LAYER M5 ;
        RECT  49.872 23.676 49.896 23.76 ;
    END
  END o[492]
  PIN o[493]
    DIRECTION OUTPUT ;
    USE SIGNAL ;
    PORT
      LAYER M5 ;
        RECT  49.968 23.676 49.992 23.76 ;
    END
  END o[493]
  PIN o[494]
    DIRECTION OUTPUT ;
    USE SIGNAL ;
    PORT
      LAYER M5 ;
        RECT  50.064 23.676 50.088 23.76 ;
    END
  END o[494]
  PIN o[495]
    DIRECTION OUTPUT ;
    USE SIGNAL ;
    PORT
      LAYER M5 ;
        RECT  50.16 23.676 50.184 23.76 ;
    END
  END o[495]
  PIN o[496]
    DIRECTION OUTPUT ;
    USE SIGNAL ;
    PORT
      LAYER M5 ;
        RECT  50.256 23.676 50.28 23.76 ;
    END
  END o[496]
  PIN o[497]
    DIRECTION OUTPUT ;
    USE SIGNAL ;
    PORT
      LAYER M5 ;
        RECT  50.352 23.676 50.376 23.76 ;
    END
  END o[497]
  PIN o[498]
    DIRECTION OUTPUT ;
    USE SIGNAL ;
    PORT
      LAYER M5 ;
        RECT  50.448 23.676 50.472 23.76 ;
    END
  END o[498]
  PIN o[499]
    DIRECTION OUTPUT ;
    USE SIGNAL ;
    PORT
      LAYER M5 ;
        RECT  50.544 23.676 50.568 23.76 ;
    END
  END o[499]
  PIN o[49]
    DIRECTION OUTPUT ;
    USE SIGNAL ;
    PORT
      LAYER M5 ;
        RECT  15.024 23.676 15.048 23.76 ;
    END
  END o[49]
  PIN o[4]
    DIRECTION OUTPUT ;
    USE SIGNAL ;
    PORT
      LAYER M5 ;
        RECT  16.848 23.676 16.872 23.76 ;
    END
  END o[4]
  PIN o[500]
    DIRECTION OUTPUT ;
    USE SIGNAL ;
    PORT
      LAYER M5 ;
        RECT  50.64 23.676 50.664 23.76 ;
    END
  END o[500]
  PIN o[501]
    DIRECTION OUTPUT ;
    USE SIGNAL ;
    PORT
      LAYER M5 ;
        RECT  50.736 23.676 50.76 23.76 ;
    END
  END o[501]
  PIN o[502]
    DIRECTION OUTPUT ;
    USE SIGNAL ;
    PORT
      LAYER M5 ;
        RECT  50.832 23.676 50.856 23.76 ;
    END
  END o[502]
  PIN o[503]
    DIRECTION OUTPUT ;
    USE SIGNAL ;
    PORT
      LAYER M5 ;
        RECT  50.928 23.676 50.952 23.76 ;
    END
  END o[503]
  PIN o[504]
    DIRECTION OUTPUT ;
    USE SIGNAL ;
    PORT
      LAYER M5 ;
        RECT  51.024 23.676 51.048 23.76 ;
    END
  END o[504]
  PIN o[505]
    DIRECTION OUTPUT ;
    USE SIGNAL ;
    PORT
      LAYER M5 ;
        RECT  51.12 23.676 51.144 23.76 ;
    END
  END o[505]
  PIN o[506]
    DIRECTION OUTPUT ;
    USE SIGNAL ;
    PORT
      LAYER M5 ;
        RECT  51.216 23.676 51.24 23.76 ;
    END
  END o[506]
  PIN o[507]
    DIRECTION OUTPUT ;
    USE SIGNAL ;
    PORT
      LAYER M5 ;
        RECT  51.312 23.676 51.336 23.76 ;
    END
  END o[507]
  PIN o[508]
    DIRECTION OUTPUT ;
    USE SIGNAL ;
    PORT
      LAYER M5 ;
        RECT  51.408 23.676 51.432 23.76 ;
    END
  END o[508]
  PIN o[509]
    DIRECTION OUTPUT ;
    USE SIGNAL ;
    PORT
      LAYER M5 ;
        RECT  51.504 23.676 51.528 23.76 ;
    END
  END o[509]
  PIN o[50]
    DIRECTION OUTPUT ;
    USE SIGNAL ;
    PORT
      LAYER M5 ;
        RECT  15.12 23.676 15.144 23.76 ;
    END
  END o[50]
  PIN o[510]
    DIRECTION OUTPUT ;
    USE SIGNAL ;
    PORT
      LAYER M5 ;
        RECT  51.6 23.676 51.624 23.76 ;
    END
  END o[510]
  PIN o[511]
    DIRECTION OUTPUT ;
    USE SIGNAL ;
    PORT
      LAYER M5 ;
        RECT  51.696 23.676 51.72 23.76 ;
    END
  END o[511]
  PIN o[512]
    DIRECTION OUTPUT ;
    USE SIGNAL ;
    PORT
      LAYER M5 ;
        RECT  61.008 23.676 61.032 23.76 ;
    END
  END o[512]
  PIN o[513]
    DIRECTION OUTPUT ;
    USE SIGNAL ;
    PORT
      LAYER M5 ;
        RECT  61.104 23.676 61.128 23.76 ;
    END
  END o[513]
  PIN o[514]
    DIRECTION OUTPUT ;
    USE SIGNAL ;
    PORT
      LAYER M5 ;
        RECT  61.2 23.676 61.224 23.76 ;
    END
  END o[514]
  PIN o[515]
    DIRECTION OUTPUT ;
    USE SIGNAL ;
    PORT
      LAYER M5 ;
        RECT  61.296 23.676 61.32 23.76 ;
    END
  END o[515]
  PIN o[516]
    DIRECTION OUTPUT ;
    USE SIGNAL ;
    PORT
      LAYER M5 ;
        RECT  61.392 23.676 61.416 23.76 ;
    END
  END o[516]
  PIN o[517]
    DIRECTION OUTPUT ;
    USE SIGNAL ;
    PORT
      LAYER M5 ;
        RECT  61.488 23.676 61.512 23.76 ;
    END
  END o[517]
  PIN o[518]
    DIRECTION OUTPUT ;
    USE SIGNAL ;
    PORT
      LAYER M5 ;
        RECT  61.584 23.676 61.608 23.76 ;
    END
  END o[518]
  PIN o[519]
    DIRECTION OUTPUT ;
    USE SIGNAL ;
    PORT
      LAYER M5 ;
        RECT  61.68 23.676 61.704 23.76 ;
    END
  END o[519]
  PIN o[51]
    DIRECTION OUTPUT ;
    USE SIGNAL ;
    PORT
      LAYER M5 ;
        RECT  15.216 23.676 15.24 23.76 ;
    END
  END o[51]
  PIN o[520]
    DIRECTION OUTPUT ;
    USE SIGNAL ;
    PORT
      LAYER M5 ;
        RECT  61.776 23.676 61.8 23.76 ;
    END
  END o[520]
  PIN o[521]
    DIRECTION OUTPUT ;
    USE SIGNAL ;
    PORT
      LAYER M5 ;
        RECT  61.872 23.676 61.896 23.76 ;
    END
  END o[521]
  PIN o[522]
    DIRECTION OUTPUT ;
    USE SIGNAL ;
    PORT
      LAYER M5 ;
        RECT  61.968 23.676 61.992 23.76 ;
    END
  END o[522]
  PIN o[523]
    DIRECTION OUTPUT ;
    USE SIGNAL ;
    PORT
      LAYER M5 ;
        RECT  62.064 23.676 62.088 23.76 ;
    END
  END o[523]
  PIN o[524]
    DIRECTION OUTPUT ;
    USE SIGNAL ;
    PORT
      LAYER M5 ;
        RECT  62.16 23.676 62.184 23.76 ;
    END
  END o[524]
  PIN o[525]
    DIRECTION OUTPUT ;
    USE SIGNAL ;
    PORT
      LAYER M5 ;
        RECT  62.256 23.676 62.28 23.76 ;
    END
  END o[525]
  PIN o[526]
    DIRECTION OUTPUT ;
    USE SIGNAL ;
    PORT
      LAYER M5 ;
        RECT  62.352 23.676 62.376 23.76 ;
    END
  END o[526]
  PIN o[527]
    DIRECTION OUTPUT ;
    USE SIGNAL ;
    PORT
      LAYER M5 ;
        RECT  62.448 23.676 62.472 23.76 ;
    END
  END o[527]
  PIN o[528]
    DIRECTION OUTPUT ;
    USE SIGNAL ;
    PORT
      LAYER M5 ;
        RECT  62.544 23.676 62.568 23.76 ;
    END
  END o[528]
  PIN o[529]
    DIRECTION OUTPUT ;
    USE SIGNAL ;
    PORT
      LAYER M5 ;
        RECT  62.64 23.676 62.664 23.76 ;
    END
  END o[529]
  PIN o[52]
    DIRECTION OUTPUT ;
    USE SIGNAL ;
    PORT
      LAYER M5 ;
        RECT  15.312 23.676 15.336 23.76 ;
    END
  END o[52]
  PIN o[530]
    DIRECTION OUTPUT ;
    USE SIGNAL ;
    PORT
      LAYER M5 ;
        RECT  62.736 23.676 62.76 23.76 ;
    END
  END o[530]
  PIN o[531]
    DIRECTION OUTPUT ;
    USE SIGNAL ;
    PORT
      LAYER M5 ;
        RECT  62.832 23.676 62.856 23.76 ;
    END
  END o[531]
  PIN o[532]
    DIRECTION OUTPUT ;
    USE SIGNAL ;
    PORT
      LAYER M5 ;
        RECT  62.928 23.676 62.952 23.76 ;
    END
  END o[532]
  PIN o[533]
    DIRECTION OUTPUT ;
    USE SIGNAL ;
    PORT
      LAYER M5 ;
        RECT  63.024 23.676 63.048 23.76 ;
    END
  END o[533]
  PIN o[534]
    DIRECTION OUTPUT ;
    USE SIGNAL ;
    PORT
      LAYER M5 ;
        RECT  63.12 23.676 63.144 23.76 ;
    END
  END o[534]
  PIN o[535]
    DIRECTION OUTPUT ;
    USE SIGNAL ;
    PORT
      LAYER M5 ;
        RECT  63.216 23.676 63.24 23.76 ;
    END
  END o[535]
  PIN o[536]
    DIRECTION OUTPUT ;
    USE SIGNAL ;
    PORT
      LAYER M5 ;
        RECT  63.312 23.676 63.336 23.76 ;
    END
  END o[536]
  PIN o[537]
    DIRECTION OUTPUT ;
    USE SIGNAL ;
    PORT
      LAYER M5 ;
        RECT  63.408 23.676 63.432 23.76 ;
    END
  END o[537]
  PIN o[538]
    DIRECTION OUTPUT ;
    USE SIGNAL ;
    PORT
      LAYER M5 ;
        RECT  63.504 23.676 63.528 23.76 ;
    END
  END o[538]
  PIN o[539]
    DIRECTION OUTPUT ;
    USE SIGNAL ;
    PORT
      LAYER M5 ;
        RECT  63.6 23.676 63.624 23.76 ;
    END
  END o[539]
  PIN o[53]
    DIRECTION OUTPUT ;
    USE SIGNAL ;
    PORT
      LAYER M5 ;
        RECT  15.408 23.676 15.432 23.76 ;
    END
  END o[53]
  PIN o[540]
    DIRECTION OUTPUT ;
    USE SIGNAL ;
    PORT
      LAYER M5 ;
        RECT  63.696 23.676 63.72 23.76 ;
    END
  END o[540]
  PIN o[541]
    DIRECTION OUTPUT ;
    USE SIGNAL ;
    PORT
      LAYER M5 ;
        RECT  63.792 23.676 63.816 23.76 ;
    END
  END o[541]
  PIN o[542]
    DIRECTION OUTPUT ;
    USE SIGNAL ;
    PORT
      LAYER M5 ;
        RECT  63.888 23.676 63.912 23.76 ;
    END
  END o[542]
  PIN o[543]
    DIRECTION OUTPUT ;
    USE SIGNAL ;
    PORT
      LAYER M5 ;
        RECT  63.984 23.676 64.008 23.76 ;
    END
  END o[543]
  PIN o[544]
    DIRECTION OUTPUT ;
    USE SIGNAL ;
    PORT
      LAYER M5 ;
        RECT  57.936 23.676 57.96 23.76 ;
    END
  END o[544]
  PIN o[545]
    DIRECTION OUTPUT ;
    USE SIGNAL ;
    PORT
      LAYER M5 ;
        RECT  58.032 23.676 58.056 23.76 ;
    END
  END o[545]
  PIN o[546]
    DIRECTION OUTPUT ;
    USE SIGNAL ;
    PORT
      LAYER M5 ;
        RECT  58.128 23.676 58.152 23.76 ;
    END
  END o[546]
  PIN o[547]
    DIRECTION OUTPUT ;
    USE SIGNAL ;
    PORT
      LAYER M5 ;
        RECT  58.224 23.676 58.248 23.76 ;
    END
  END o[547]
  PIN o[548]
    DIRECTION OUTPUT ;
    USE SIGNAL ;
    PORT
      LAYER M5 ;
        RECT  58.32 23.676 58.344 23.76 ;
    END
  END o[548]
  PIN o[549]
    DIRECTION OUTPUT ;
    USE SIGNAL ;
    PORT
      LAYER M5 ;
        RECT  58.416 23.676 58.44 23.76 ;
    END
  END o[549]
  PIN o[54]
    DIRECTION OUTPUT ;
    USE SIGNAL ;
    PORT
      LAYER M5 ;
        RECT  15.504 23.676 15.528 23.76 ;
    END
  END o[54]
  PIN o[550]
    DIRECTION OUTPUT ;
    USE SIGNAL ;
    PORT
      LAYER M5 ;
        RECT  58.512 23.676 58.536 23.76 ;
    END
  END o[550]
  PIN o[551]
    DIRECTION OUTPUT ;
    USE SIGNAL ;
    PORT
      LAYER M5 ;
        RECT  58.608 23.676 58.632 23.76 ;
    END
  END o[551]
  PIN o[552]
    DIRECTION OUTPUT ;
    USE SIGNAL ;
    PORT
      LAYER M5 ;
        RECT  58.704 23.676 58.728 23.76 ;
    END
  END o[552]
  PIN o[553]
    DIRECTION OUTPUT ;
    USE SIGNAL ;
    PORT
      LAYER M5 ;
        RECT  58.8 23.676 58.824 23.76 ;
    END
  END o[553]
  PIN o[554]
    DIRECTION OUTPUT ;
    USE SIGNAL ;
    PORT
      LAYER M5 ;
        RECT  58.896 23.676 58.92 23.76 ;
    END
  END o[554]
  PIN o[555]
    DIRECTION OUTPUT ;
    USE SIGNAL ;
    PORT
      LAYER M5 ;
        RECT  58.992 23.676 59.016 23.76 ;
    END
  END o[555]
  PIN o[556]
    DIRECTION OUTPUT ;
    USE SIGNAL ;
    PORT
      LAYER M5 ;
        RECT  59.088 23.676 59.112 23.76 ;
    END
  END o[556]
  PIN o[557]
    DIRECTION OUTPUT ;
    USE SIGNAL ;
    PORT
      LAYER M5 ;
        RECT  59.184 23.676 59.208 23.76 ;
    END
  END o[557]
  PIN o[558]
    DIRECTION OUTPUT ;
    USE SIGNAL ;
    PORT
      LAYER M5 ;
        RECT  59.28 23.676 59.304 23.76 ;
    END
  END o[558]
  PIN o[559]
    DIRECTION OUTPUT ;
    USE SIGNAL ;
    PORT
      LAYER M5 ;
        RECT  59.376 23.676 59.4 23.76 ;
    END
  END o[559]
  PIN o[55]
    DIRECTION OUTPUT ;
    USE SIGNAL ;
    PORT
      LAYER M5 ;
        RECT  15.6 23.676 15.624 23.76 ;
    END
  END o[55]
  PIN o[560]
    DIRECTION OUTPUT ;
    USE SIGNAL ;
    PORT
      LAYER M5 ;
        RECT  59.472 23.676 59.496 23.76 ;
    END
  END o[560]
  PIN o[561]
    DIRECTION OUTPUT ;
    USE SIGNAL ;
    PORT
      LAYER M5 ;
        RECT  59.568 23.676 59.592 23.76 ;
    END
  END o[561]
  PIN o[562]
    DIRECTION OUTPUT ;
    USE SIGNAL ;
    PORT
      LAYER M5 ;
        RECT  59.664 23.676 59.688 23.76 ;
    END
  END o[562]
  PIN o[563]
    DIRECTION OUTPUT ;
    USE SIGNAL ;
    PORT
      LAYER M5 ;
        RECT  59.76 23.676 59.784 23.76 ;
    END
  END o[563]
  PIN o[564]
    DIRECTION OUTPUT ;
    USE SIGNAL ;
    PORT
      LAYER M5 ;
        RECT  59.856 23.676 59.88 23.76 ;
    END
  END o[564]
  PIN o[565]
    DIRECTION OUTPUT ;
    USE SIGNAL ;
    PORT
      LAYER M5 ;
        RECT  59.952 23.676 59.976 23.76 ;
    END
  END o[565]
  PIN o[566]
    DIRECTION OUTPUT ;
    USE SIGNAL ;
    PORT
      LAYER M5 ;
        RECT  60.048 23.676 60.072 23.76 ;
    END
  END o[566]
  PIN o[567]
    DIRECTION OUTPUT ;
    USE SIGNAL ;
    PORT
      LAYER M5 ;
        RECT  60.144 23.676 60.168 23.76 ;
    END
  END o[567]
  PIN o[568]
    DIRECTION OUTPUT ;
    USE SIGNAL ;
    PORT
      LAYER M5 ;
        RECT  60.24 23.676 60.264 23.76 ;
    END
  END o[568]
  PIN o[569]
    DIRECTION OUTPUT ;
    USE SIGNAL ;
    PORT
      LAYER M5 ;
        RECT  60.336 23.676 60.36 23.76 ;
    END
  END o[569]
  PIN o[56]
    DIRECTION OUTPUT ;
    USE SIGNAL ;
    PORT
      LAYER M5 ;
        RECT  15.696 23.676 15.72 23.76 ;
    END
  END o[56]
  PIN o[570]
    DIRECTION OUTPUT ;
    USE SIGNAL ;
    PORT
      LAYER M5 ;
        RECT  60.432 23.676 60.456 23.76 ;
    END
  END o[570]
  PIN o[571]
    DIRECTION OUTPUT ;
    USE SIGNAL ;
    PORT
      LAYER M5 ;
        RECT  60.528 23.676 60.552 23.76 ;
    END
  END o[571]
  PIN o[572]
    DIRECTION OUTPUT ;
    USE SIGNAL ;
    PORT
      LAYER M5 ;
        RECT  60.624 23.676 60.648 23.76 ;
    END
  END o[572]
  PIN o[573]
    DIRECTION OUTPUT ;
    USE SIGNAL ;
    PORT
      LAYER M5 ;
        RECT  60.72 23.676 60.744 23.76 ;
    END
  END o[573]
  PIN o[574]
    DIRECTION OUTPUT ;
    USE SIGNAL ;
    PORT
      LAYER M5 ;
        RECT  60.816 23.676 60.84 23.76 ;
    END
  END o[574]
  PIN o[575]
    DIRECTION OUTPUT ;
    USE SIGNAL ;
    PORT
      LAYER M5 ;
        RECT  60.912 23.676 60.936 23.76 ;
    END
  END o[575]
  PIN o[576]
    DIRECTION OUTPUT ;
    USE SIGNAL ;
    PORT
      LAYER M5 ;
        RECT  3.408 23.676 3.432 23.76 ;
    END
  END o[576]
  PIN o[577]
    DIRECTION OUTPUT ;
    USE SIGNAL ;
    PORT
      LAYER M5 ;
        RECT  3.504 23.676 3.528 23.76 ;
    END
  END o[577]
  PIN o[578]
    DIRECTION OUTPUT ;
    USE SIGNAL ;
    PORT
      LAYER M5 ;
        RECT  3.6 23.676 3.624 23.76 ;
    END
  END o[578]
  PIN o[579]
    DIRECTION OUTPUT ;
    USE SIGNAL ;
    PORT
      LAYER M5 ;
        RECT  3.696 23.676 3.72 23.76 ;
    END
  END o[579]
  PIN o[57]
    DIRECTION OUTPUT ;
    USE SIGNAL ;
    PORT
      LAYER M5 ;
        RECT  15.792 23.676 15.816 23.76 ;
    END
  END o[57]
  PIN o[580]
    DIRECTION OUTPUT ;
    USE SIGNAL ;
    PORT
      LAYER M5 ;
        RECT  3.792 23.676 3.816 23.76 ;
    END
  END o[580]
  PIN o[581]
    DIRECTION OUTPUT ;
    USE SIGNAL ;
    PORT
      LAYER M5 ;
        RECT  3.888 23.676 3.912 23.76 ;
    END
  END o[581]
  PIN o[582]
    DIRECTION OUTPUT ;
    USE SIGNAL ;
    PORT
      LAYER M5 ;
        RECT  3.984 23.676 4.008 23.76 ;
    END
  END o[582]
  PIN o[583]
    DIRECTION OUTPUT ;
    USE SIGNAL ;
    PORT
      LAYER M5 ;
        RECT  4.08 23.676 4.104 23.76 ;
    END
  END o[583]
  PIN o[584]
    DIRECTION OUTPUT ;
    USE SIGNAL ;
    PORT
      LAYER M5 ;
        RECT  4.176 23.676 4.2 23.76 ;
    END
  END o[584]
  PIN o[585]
    DIRECTION OUTPUT ;
    USE SIGNAL ;
    PORT
      LAYER M5 ;
        RECT  4.272 23.676 4.296 23.76 ;
    END
  END o[585]
  PIN o[586]
    DIRECTION OUTPUT ;
    USE SIGNAL ;
    PORT
      LAYER M5 ;
        RECT  4.368 23.676 4.392 23.76 ;
    END
  END o[586]
  PIN o[587]
    DIRECTION OUTPUT ;
    USE SIGNAL ;
    PORT
      LAYER M5 ;
        RECT  4.464 23.676 4.488 23.76 ;
    END
  END o[587]
  PIN o[588]
    DIRECTION OUTPUT ;
    USE SIGNAL ;
    PORT
      LAYER M5 ;
        RECT  4.56 23.676 4.584 23.76 ;
    END
  END o[588]
  PIN o[589]
    DIRECTION OUTPUT ;
    USE SIGNAL ;
    PORT
      LAYER M5 ;
        RECT  4.656 23.676 4.68 23.76 ;
    END
  END o[589]
  PIN o[58]
    DIRECTION OUTPUT ;
    USE SIGNAL ;
    PORT
      LAYER M5 ;
        RECT  15.888 23.676 15.912 23.76 ;
    END
  END o[58]
  PIN o[590]
    DIRECTION OUTPUT ;
    USE SIGNAL ;
    PORT
      LAYER M5 ;
        RECT  4.752 23.676 4.776 23.76 ;
    END
  END o[590]
  PIN o[591]
    DIRECTION OUTPUT ;
    USE SIGNAL ;
    PORT
      LAYER M5 ;
        RECT  4.848 23.676 4.872 23.76 ;
    END
  END o[591]
  PIN o[592]
    DIRECTION OUTPUT ;
    USE SIGNAL ;
    PORT
      LAYER M5 ;
        RECT  4.944 23.676 4.968 23.76 ;
    END
  END o[592]
  PIN o[593]
    DIRECTION OUTPUT ;
    USE SIGNAL ;
    PORT
      LAYER M5 ;
        RECT  5.04 23.676 5.064 23.76 ;
    END
  END o[593]
  PIN o[594]
    DIRECTION OUTPUT ;
    USE SIGNAL ;
    PORT
      LAYER M5 ;
        RECT  5.136 23.676 5.16 23.76 ;
    END
  END o[594]
  PIN o[595]
    DIRECTION OUTPUT ;
    USE SIGNAL ;
    PORT
      LAYER M5 ;
        RECT  5.232 23.676 5.256 23.76 ;
    END
  END o[595]
  PIN o[596]
    DIRECTION OUTPUT ;
    USE SIGNAL ;
    PORT
      LAYER M5 ;
        RECT  5.328 23.676 5.352 23.76 ;
    END
  END o[596]
  PIN o[597]
    DIRECTION OUTPUT ;
    USE SIGNAL ;
    PORT
      LAYER M5 ;
        RECT  5.424 23.676 5.448 23.76 ;
    END
  END o[597]
  PIN o[598]
    DIRECTION OUTPUT ;
    USE SIGNAL ;
    PORT
      LAYER M5 ;
        RECT  5.52 23.676 5.544 23.76 ;
    END
  END o[598]
  PIN o[599]
    DIRECTION OUTPUT ;
    USE SIGNAL ;
    PORT
      LAYER M5 ;
        RECT  5.616 23.676 5.64 23.76 ;
    END
  END o[599]
  PIN o[59]
    DIRECTION OUTPUT ;
    USE SIGNAL ;
    PORT
      LAYER M5 ;
        RECT  15.984 23.676 16.008 23.76 ;
    END
  END o[59]
  PIN o[5]
    DIRECTION OUTPUT ;
    USE SIGNAL ;
    PORT
      LAYER M5 ;
        RECT  16.944 23.676 16.968 23.76 ;
    END
  END o[5]
  PIN o[600]
    DIRECTION OUTPUT ;
    USE SIGNAL ;
    PORT
      LAYER M5 ;
        RECT  5.712 23.676 5.736 23.76 ;
    END
  END o[600]
  PIN o[601]
    DIRECTION OUTPUT ;
    USE SIGNAL ;
    PORT
      LAYER M5 ;
        RECT  5.808 23.676 5.832 23.76 ;
    END
  END o[601]
  PIN o[602]
    DIRECTION OUTPUT ;
    USE SIGNAL ;
    PORT
      LAYER M5 ;
        RECT  5.904 23.676 5.928 23.76 ;
    END
  END o[602]
  PIN o[603]
    DIRECTION OUTPUT ;
    USE SIGNAL ;
    PORT
      LAYER M5 ;
        RECT  6 23.676 6.024 23.76 ;
    END
  END o[603]
  PIN o[604]
    DIRECTION OUTPUT ;
    USE SIGNAL ;
    PORT
      LAYER M5 ;
        RECT  6.096 23.676 6.12 23.76 ;
    END
  END o[604]
  PIN o[605]
    DIRECTION OUTPUT ;
    USE SIGNAL ;
    PORT
      LAYER M5 ;
        RECT  6.192 23.676 6.216 23.76 ;
    END
  END o[605]
  PIN o[606]
    DIRECTION OUTPUT ;
    USE SIGNAL ;
    PORT
      LAYER M5 ;
        RECT  6.288 23.676 6.312 23.76 ;
    END
  END o[606]
  PIN o[607]
    DIRECTION OUTPUT ;
    USE SIGNAL ;
    PORT
      LAYER M5 ;
        RECT  6.384 23.676 6.408 23.76 ;
    END
  END o[607]
  PIN o[608]
    DIRECTION OUTPUT ;
    USE SIGNAL ;
    PORT
      LAYER M5 ;
        RECT  1.872 23.676 1.896 23.76 ;
    END
  END o[608]
  PIN o[609]
    DIRECTION OUTPUT ;
    USE SIGNAL ;
    PORT
      LAYER M5 ;
        RECT  1.968 23.676 1.992 23.76 ;
    END
  END o[609]
  PIN o[60]
    DIRECTION OUTPUT ;
    USE SIGNAL ;
    PORT
      LAYER M5 ;
        RECT  16.08 23.676 16.104 23.76 ;
    END
  END o[60]
  PIN o[610]
    DIRECTION OUTPUT ;
    USE SIGNAL ;
    PORT
      LAYER M5 ;
        RECT  2.064 23.676 2.088 23.76 ;
    END
  END o[610]
  PIN o[611]
    DIRECTION OUTPUT ;
    USE SIGNAL ;
    PORT
      LAYER M5 ;
        RECT  2.16 23.676 2.184 23.76 ;
    END
  END o[611]
  PIN o[612]
    DIRECTION OUTPUT ;
    USE SIGNAL ;
    PORT
      LAYER M5 ;
        RECT  2.256 23.676 2.28 23.76 ;
    END
  END o[612]
  PIN o[613]
    DIRECTION OUTPUT ;
    USE SIGNAL ;
    PORT
      LAYER M5 ;
        RECT  2.352 23.676 2.376 23.76 ;
    END
  END o[613]
  PIN o[614]
    DIRECTION OUTPUT ;
    USE SIGNAL ;
    PORT
      LAYER M5 ;
        RECT  2.448 23.676 2.472 23.76 ;
    END
  END o[614]
  PIN o[615]
    DIRECTION OUTPUT ;
    USE SIGNAL ;
    PORT
      LAYER M5 ;
        RECT  2.544 23.676 2.568 23.76 ;
    END
  END o[615]
  PIN o[616]
    DIRECTION OUTPUT ;
    USE SIGNAL ;
    PORT
      LAYER M5 ;
        RECT  2.64 23.676 2.664 23.76 ;
    END
  END o[616]
  PIN o[617]
    DIRECTION OUTPUT ;
    USE SIGNAL ;
    PORT
      LAYER M5 ;
        RECT  2.736 23.676 2.76 23.76 ;
    END
  END o[617]
  PIN o[618]
    DIRECTION OUTPUT ;
    USE SIGNAL ;
    PORT
      LAYER M5 ;
        RECT  2.832 23.676 2.856 23.76 ;
    END
  END o[618]
  PIN o[619]
    DIRECTION OUTPUT ;
    USE SIGNAL ;
    PORT
      LAYER M5 ;
        RECT  2.928 23.676 2.952 23.76 ;
    END
  END o[619]
  PIN o[61]
    DIRECTION OUTPUT ;
    USE SIGNAL ;
    PORT
      LAYER M5 ;
        RECT  16.176 23.676 16.2 23.76 ;
    END
  END o[61]
  PIN o[620]
    DIRECTION OUTPUT ;
    USE SIGNAL ;
    PORT
      LAYER M5 ;
        RECT  3.024 23.676 3.048 23.76 ;
    END
  END o[620]
  PIN o[621]
    DIRECTION OUTPUT ;
    USE SIGNAL ;
    PORT
      LAYER M5 ;
        RECT  3.12 23.676 3.144 23.76 ;
    END
  END o[621]
  PIN o[622]
    DIRECTION OUTPUT ;
    USE SIGNAL ;
    PORT
      LAYER M5 ;
        RECT  3.216 23.676 3.24 23.76 ;
    END
  END o[622]
  PIN o[623]
    DIRECTION OUTPUT ;
    USE SIGNAL ;
    PORT
      LAYER M5 ;
        RECT  3.312 23.676 3.336 23.76 ;
    END
  END o[623]
  PIN o[62]
    DIRECTION OUTPUT ;
    USE SIGNAL ;
    PORT
      LAYER M5 ;
        RECT  16.272 23.676 16.296 23.76 ;
    END
  END o[62]
  PIN o[63]
    DIRECTION OUTPUT ;
    USE SIGNAL ;
    PORT
      LAYER M5 ;
        RECT  16.368 23.676 16.392 23.76 ;
    END
  END o[63]
  PIN o[64]
    DIRECTION OUTPUT ;
    USE SIGNAL ;
    PORT
      LAYER M5 ;
        RECT  22.608 23.676 22.632 23.76 ;
    END
  END o[64]
  PIN o[65]
    DIRECTION OUTPUT ;
    USE SIGNAL ;
    PORT
      LAYER M5 ;
        RECT  22.704 23.676 22.728 23.76 ;
    END
  END o[65]
  PIN o[66]
    DIRECTION OUTPUT ;
    USE SIGNAL ;
    PORT
      LAYER M5 ;
        RECT  22.8 23.676 22.824 23.76 ;
    END
  END o[66]
  PIN o[67]
    DIRECTION OUTPUT ;
    USE SIGNAL ;
    PORT
      LAYER M5 ;
        RECT  22.896 23.676 22.92 23.76 ;
    END
  END o[67]
  PIN o[68]
    DIRECTION OUTPUT ;
    USE SIGNAL ;
    PORT
      LAYER M5 ;
        RECT  22.992 23.676 23.016 23.76 ;
    END
  END o[68]
  PIN o[69]
    DIRECTION OUTPUT ;
    USE SIGNAL ;
    PORT
      LAYER M5 ;
        RECT  23.088 23.676 23.112 23.76 ;
    END
  END o[69]
  PIN o[6]
    DIRECTION OUTPUT ;
    USE SIGNAL ;
    PORT
      LAYER M5 ;
        RECT  17.04 23.676 17.064 23.76 ;
    END
  END o[6]
  PIN o[70]
    DIRECTION OUTPUT ;
    USE SIGNAL ;
    PORT
      LAYER M5 ;
        RECT  23.184 23.676 23.208 23.76 ;
    END
  END o[70]
  PIN o[71]
    DIRECTION OUTPUT ;
    USE SIGNAL ;
    PORT
      LAYER M5 ;
        RECT  23.28 23.676 23.304 23.76 ;
    END
  END o[71]
  PIN o[72]
    DIRECTION OUTPUT ;
    USE SIGNAL ;
    PORT
      LAYER M5 ;
        RECT  23.376 23.676 23.4 23.76 ;
    END
  END o[72]
  PIN o[73]
    DIRECTION OUTPUT ;
    USE SIGNAL ;
    PORT
      LAYER M5 ;
        RECT  23.472 23.676 23.496 23.76 ;
    END
  END o[73]
  PIN o[74]
    DIRECTION OUTPUT ;
    USE SIGNAL ;
    PORT
      LAYER M5 ;
        RECT  23.568 23.676 23.592 23.76 ;
    END
  END o[74]
  PIN o[75]
    DIRECTION OUTPUT ;
    USE SIGNAL ;
    PORT
      LAYER M5 ;
        RECT  23.664 23.676 23.688 23.76 ;
    END
  END o[75]
  PIN o[76]
    DIRECTION OUTPUT ;
    USE SIGNAL ;
    PORT
      LAYER M5 ;
        RECT  23.76 23.676 23.784 23.76 ;
    END
  END o[76]
  PIN o[77]
    DIRECTION OUTPUT ;
    USE SIGNAL ;
    PORT
      LAYER M5 ;
        RECT  23.856 23.676 23.88 23.76 ;
    END
  END o[77]
  PIN o[78]
    DIRECTION OUTPUT ;
    USE SIGNAL ;
    PORT
      LAYER M5 ;
        RECT  23.952 23.676 23.976 23.76 ;
    END
  END o[78]
  PIN o[79]
    DIRECTION OUTPUT ;
    USE SIGNAL ;
    PORT
      LAYER M5 ;
        RECT  24.048 23.676 24.072 23.76 ;
    END
  END o[79]
  PIN o[7]
    DIRECTION OUTPUT ;
    USE SIGNAL ;
    PORT
      LAYER M5 ;
        RECT  17.136 23.676 17.16 23.76 ;
    END
  END o[7]
  PIN o[80]
    DIRECTION OUTPUT ;
    USE SIGNAL ;
    PORT
      LAYER M5 ;
        RECT  24.144 23.676 24.168 23.76 ;
    END
  END o[80]
  PIN o[81]
    DIRECTION OUTPUT ;
    USE SIGNAL ;
    PORT
      LAYER M5 ;
        RECT  24.24 23.676 24.264 23.76 ;
    END
  END o[81]
  PIN o[82]
    DIRECTION OUTPUT ;
    USE SIGNAL ;
    PORT
      LAYER M5 ;
        RECT  24.336 23.676 24.36 23.76 ;
    END
  END o[82]
  PIN o[83]
    DIRECTION OUTPUT ;
    USE SIGNAL ;
    PORT
      LAYER M5 ;
        RECT  24.432 23.676 24.456 23.76 ;
    END
  END o[83]
  PIN o[84]
    DIRECTION OUTPUT ;
    USE SIGNAL ;
    PORT
      LAYER M5 ;
        RECT  24.528 23.676 24.552 23.76 ;
    END
  END o[84]
  PIN o[85]
    DIRECTION OUTPUT ;
    USE SIGNAL ;
    PORT
      LAYER M5 ;
        RECT  24.624 23.676 24.648 23.76 ;
    END
  END o[85]
  PIN o[86]
    DIRECTION OUTPUT ;
    USE SIGNAL ;
    PORT
      LAYER M5 ;
        RECT  24.72 23.676 24.744 23.76 ;
    END
  END o[86]
  PIN o[87]
    DIRECTION OUTPUT ;
    USE SIGNAL ;
    PORT
      LAYER M5 ;
        RECT  24.816 23.676 24.84 23.76 ;
    END
  END o[87]
  PIN o[88]
    DIRECTION OUTPUT ;
    USE SIGNAL ;
    PORT
      LAYER M5 ;
        RECT  24.912 23.676 24.936 23.76 ;
    END
  END o[88]
  PIN o[89]
    DIRECTION OUTPUT ;
    USE SIGNAL ;
    PORT
      LAYER M5 ;
        RECT  25.008 23.676 25.032 23.76 ;
    END
  END o[89]
  PIN o[8]
    DIRECTION OUTPUT ;
    USE SIGNAL ;
    PORT
      LAYER M5 ;
        RECT  17.232 23.676 17.256 23.76 ;
    END
  END o[8]
  PIN o[90]
    DIRECTION OUTPUT ;
    USE SIGNAL ;
    PORT
      LAYER M5 ;
        RECT  25.104 23.676 25.128 23.76 ;
    END
  END o[90]
  PIN o[91]
    DIRECTION OUTPUT ;
    USE SIGNAL ;
    PORT
      LAYER M5 ;
        RECT  25.2 23.676 25.224 23.76 ;
    END
  END o[91]
  PIN o[92]
    DIRECTION OUTPUT ;
    USE SIGNAL ;
    PORT
      LAYER M5 ;
        RECT  25.296 23.676 25.32 23.76 ;
    END
  END o[92]
  PIN o[93]
    DIRECTION OUTPUT ;
    USE SIGNAL ;
    PORT
      LAYER M5 ;
        RECT  25.392 23.676 25.416 23.76 ;
    END
  END o[93]
  PIN o[94]
    DIRECTION OUTPUT ;
    USE SIGNAL ;
    PORT
      LAYER M5 ;
        RECT  25.488 23.676 25.512 23.76 ;
    END
  END o[94]
  PIN o[95]
    DIRECTION OUTPUT ;
    USE SIGNAL ;
    PORT
      LAYER M5 ;
        RECT  25.584 23.676 25.608 23.76 ;
    END
  END o[95]
  PIN o[96]
    DIRECTION OUTPUT ;
    USE SIGNAL ;
    PORT
      LAYER M5 ;
        RECT  10.32 23.676 10.344 23.76 ;
    END
  END o[96]
  PIN o[97]
    DIRECTION OUTPUT ;
    USE SIGNAL ;
    PORT
      LAYER M5 ;
        RECT  10.416 23.676 10.44 23.76 ;
    END
  END o[97]
  PIN o[98]
    DIRECTION OUTPUT ;
    USE SIGNAL ;
    PORT
      LAYER M5 ;
        RECT  10.512 23.676 10.536 23.76 ;
    END
  END o[98]
  PIN o[99]
    DIRECTION OUTPUT ;
    USE SIGNAL ;
    PORT
      LAYER M5 ;
        RECT  10.608 23.676 10.632 23.76 ;
    END
  END o[99]
  PIN o[9]
    DIRECTION OUTPUT ;
    USE SIGNAL ;
    PORT
      LAYER M5 ;
        RECT  17.328 23.676 17.352 23.76 ;
    END
  END o[9]
  PIN rs
    DIRECTION INPUT ;
    USE SIGNAL ;
    PORT
      LAYER M4 ;
        RECT  0 11.088 0.084 11.112 ;
    END
  END rs
  PIN VDD
    DIRECTION INOUT ;
    USE POWER ;
    PORT
      LAYER M5 ;
        RECT  61.992 2.151 62.112 21.609 ;
        RECT  59.292 2.151 59.412 21.609 ;
        RECT  56.592 2.151 56.712 21.609 ;
        RECT  53.892 2.151 54.012 21.609 ;
        RECT  51.192 2.151 51.312 21.609 ;
        RECT  48.492 2.151 48.612 21.609 ;
        RECT  45.792 2.151 45.912 21.609 ;
        RECT  43.092 2.151 43.212 21.609 ;
        RECT  40.392 2.151 40.512 21.609 ;
        RECT  37.692 2.151 37.812 21.609 ;
        RECT  34.992 2.151 35.112 21.609 ;
        RECT  32.292 2.151 32.412 21.609 ;
        RECT  29.592 2.151 29.712 21.609 ;
        RECT  26.892 2.151 27.012 21.609 ;
        RECT  24.192 2.151 24.312 21.609 ;
        RECT  21.492 2.151 21.612 21.609 ;
        RECT  18.792 2.151 18.912 21.609 ;
        RECT  16.092 2.151 16.212 21.609 ;
        RECT  13.392 2.151 13.512 21.609 ;
        RECT  10.692 2.151 10.812 21.609 ;
        RECT  7.992 2.151 8.112 21.609 ;
        RECT  5.292 2.151 5.412 21.609 ;
        RECT  2.592 2.151 2.712 21.609 ;
    END
  END VDD
  PIN VSS
    DIRECTION INOUT ;
    USE GROUND ;
    PORT
      LAYER M5 ;
        RECT  61.8 2.137 61.92 21.623 ;
        RECT  59.1 2.137 59.22 21.623 ;
        RECT  56.4 2.137 56.52 21.623 ;
        RECT  53.7 2.137 53.82 21.623 ;
        RECT  51 2.137 51.12 21.623 ;
        RECT  48.3 2.137 48.42 21.623 ;
        RECT  45.6 2.137 45.72 21.623 ;
        RECT  42.9 2.137 43.02 21.623 ;
        RECT  40.2 2.137 40.32 21.623 ;
        RECT  37.5 2.137 37.62 21.623 ;
        RECT  34.8 2.137 34.92 21.623 ;
        RECT  32.1 2.137 32.22 21.623 ;
        RECT  29.4 2.137 29.52 21.623 ;
        RECT  26.7 2.137 26.82 21.623 ;
        RECT  24 2.137 24.12 21.623 ;
        RECT  21.3 2.137 21.42 21.623 ;
        RECT  18.6 2.137 18.72 21.623 ;
        RECT  15.9 2.137 16.02 21.623 ;
        RECT  13.2 2.137 13.32 21.623 ;
        RECT  10.5 2.137 10.62 21.623 ;
        RECT  7.8 2.137 7.92 21.623 ;
        RECT  5.1 2.137 5.22 21.623 ;
        RECT  2.4 2.137 2.52 21.623 ;
    END
  END VSS
  # OT_OBS_CLOSED layer=M5 d_um=1.536 added=137
  OBS
    LAYER RVTN ;
     RECT  2.16 2.16 62.64 2.295 ;
     RECT  2.16 2.565 62.64 2.835 ;
     RECT  2.16 3.105 62.64 3.375 ;
     RECT  2.16 3.645 62.64 3.915 ;
     RECT  2.16 4.185 62.64 4.455 ;
     RECT  2.16 4.725 62.64 4.995 ;
     RECT  2.16 5.265 62.64 5.535 ;
     RECT  2.16 5.805 62.64 6.075 ;
     RECT  2.16 6.345 62.64 6.615 ;
     RECT  2.16 6.885 62.64 7.155 ;
     RECT  2.16 7.425 62.64 7.695 ;
     RECT  2.16 7.965 62.64 8.235 ;
     RECT  2.16 8.505 62.64 8.775 ;
     RECT  2.16 9.045 62.64 9.315 ;
     RECT  2.16 9.585 62.64 9.855 ;
     RECT  2.16 10.125 62.64 10.395 ;
     RECT  2.16 10.665 62.64 10.935 ;
     RECT  2.16 11.205 62.64 11.475 ;
     RECT  2.16 11.745 62.64 12.015 ;
     RECT  2.16 12.285 62.64 12.555 ;
     RECT  2.16 12.825 62.64 13.095 ;
     RECT  2.16 13.365 62.64 13.635 ;
     RECT  2.16 13.905 62.64 14.175 ;
     RECT  2.16 14.445 62.64 14.715 ;
     RECT  2.16 14.985 62.64 15.255 ;
     RECT  2.16 15.525 62.64 15.795 ;
     RECT  2.16 16.065 62.64 16.335 ;
     RECT  2.16 16.605 62.64 16.875 ;
     RECT  2.16 17.145 62.64 17.415 ;
     RECT  2.16 17.685 62.64 17.955 ;
     RECT  2.16 18.225 62.64 18.495 ;
     RECT  2.16 18.765 62.64 19.035 ;
     RECT  2.16 19.305 62.64 19.575 ;
     RECT  2.16 19.845 62.64 20.115 ;
     RECT  2.16 20.385 62.64 20.655 ;
     RECT  2.16 20.925 62.64 21.195 ;
     RECT  2.16 21.465 62.64 21.6 ;
    LAYER RVTP ;
     RECT  2.16 2.295 62.64 2.565 ;
     RECT  2.16 2.835 62.64 3.105 ;
     RECT  2.16 3.375 62.64 3.645 ;
     RECT  2.16 3.915 62.64 4.185 ;
     RECT  2.16 4.455 62.64 4.725 ;
     RECT  2.16 4.995 62.64 5.265 ;
     RECT  2.16 5.535 62.64 5.805 ;
     RECT  2.16 6.075 62.64 6.345 ;
     RECT  2.16 6.615 62.64 6.885 ;
     RECT  2.16 7.155 62.64 7.425 ;
     RECT  2.16 7.695 62.64 7.965 ;
     RECT  2.16 8.235 62.64 8.505 ;
     RECT  2.16 8.775 62.64 9.045 ;
     RECT  2.16 9.315 62.64 9.585 ;
     RECT  2.16 9.855 62.64 10.125 ;
     RECT  2.16 10.395 62.64 10.665 ;
     RECT  2.16 10.935 62.64 11.205 ;
     RECT  2.16 11.475 62.64 11.745 ;
     RECT  2.16 12.015 62.64 12.285 ;
     RECT  2.16 12.555 62.64 12.825 ;
     RECT  2.16 13.095 62.64 13.365 ;
     RECT  2.16 13.635 62.64 13.905 ;
     RECT  2.16 14.175 62.64 14.445 ;
     RECT  2.16 14.715 62.64 14.985 ;
     RECT  2.16 15.255 62.64 15.525 ;
     RECT  2.16 15.795 62.64 16.065 ;
     RECT  2.16 16.335 62.64 16.605 ;
     RECT  2.16 16.875 62.64 17.145 ;
     RECT  2.16 17.415 62.64 17.685 ;
     RECT  2.16 17.955 62.64 18.225 ;
     RECT  2.16 18.495 62.64 18.765 ;
     RECT  2.16 19.035 62.64 19.305 ;
     RECT  2.16 19.575 62.64 19.845 ;
     RECT  2.16 20.115 62.64 20.385 ;
     RECT  2.16 20.655 62.64 20.925 ;
     RECT  2.16 21.195 62.64 21.465 ;
    LAYER M1 ;
     RECT  2.16 2.151 62.64 21.609 ;
    LAYER M2 ;
     RECT  1.219 3.15 1.795 3.168 ;
     RECT  1.723 4.392 1.903 4.41 ;
     RECT  0.823 6.822 1.903 6.84 ;
     RECT  1.903 3.924 2.083 4.41 ;
     RECT  1.795 2.502 2.155 3.168 ;
     RECT  2.083 3.924 2.155 4.95 ;
     RECT  1.975 20.736 2.155 20.754 ;
     RECT  2.155 2.502 2.16 4.95 ;
     RECT  1.903 6.822 2.16 7.218 ;
     RECT  2.155 10.746 2.16 11.304 ;
     RECT  2.155 20.124 2.16 20.754 ;
     RECT  2.16 2.151 18.427 21.609 ;
     RECT  18.427 2.151 19.399 21.654 ;
     RECT  19.399 2.106 20.867 21.654 ;
     RECT  20.695 22.788 21.011 22.806 ;
     RECT  20.867 2.151 21.199 21.654 ;
     RECT  21.703 1.152 21.803 1.17 ;
     RECT  21.199 2.151 21.875 21.69 ;
     RECT  21.875 2.151 25.843 21.654 ;
     RECT  25.843 2.106 26.447 21.654 ;
     RECT  26.447 2.151 27.599 21.654 ;
     RECT  27.599 2.151 27.751 21.609 ;
     RECT  28.075 22.788 28.283 22.806 ;
     RECT  28.291 22.716 28.391 22.734 ;
     RECT  27.751 2.106 28.427 21.609 ;
     RECT  28.427 2.151 29.839 21.609 ;
     RECT  29.839 2.106 30.479 21.609 ;
     RECT  31.999 1.152 32.495 1.17 ;
     RECT  30.479 2.151 36.679 21.609 ;
     RECT  36.679 2.106 37.391 21.609 ;
     RECT  42.187 1.152 42.287 1.17 ;
     RECT  37.391 2.151 42.763 21.609 ;
     RECT  42.763 2.151 42.943 21.654 ;
     RECT  42.943 2.151 43.043 21.798 ;
     RECT  43.043 2.151 45.967 21.654 ;
     RECT  45.967 2.106 47.543 21.654 ;
     RECT  47.543 2.151 48.199 21.654 ;
     RECT  48.199 2.151 48.335 21.798 ;
     RECT  48.335 2.151 50.755 21.654 ;
     RECT  50.755 2.151 50.855 21.798 ;
     RECT  50.855 2.151 52.115 21.654 ;
     RECT  52.115 2.151 58.567 21.609 ;
     RECT  58.567 2.106 58.991 21.609 ;
     RECT  58.991 2.151 61.987 21.609 ;
     RECT  61.987 2.151 62.64 21.654 ;
     RECT  62.64 2.268 62.663 2.664 ;
     RECT  62.64 9.756 62.663 9.774 ;
     RECT  62.64 17.658 62.663 18.054 ;
     RECT  62.663 2.268 62.735 2.286 ;
     RECT  62.663 18.036 62.735 18.054 ;
     RECT  62.64 4.158 62.807 4.176 ;
     RECT  62.64 19.35 63.311 21.654 ;
     RECT  63.311 19.35 63.347 19.368 ;
     RECT  63.311 20.664 63.347 20.682 ;
     RECT  62.64 14.616 63.887 14.634 ;
    LAYER M3 ;
     RECT  16.38 0.091 16.83 0.221 ;
     RECT  59.652 0.091 59.67 0.365 ;
     RECT  47.448 0.475 47.466 0.523 ;
     RECT  14.256 0.091 14.274 0.571 ;
     RECT  24.66 0.091 24.678 0.571 ;
     RECT  35.928 0.475 35.946 0.571 ;
     RECT  42.192 0.523 42.21 0.571 ;
     RECT  50.112 0.523 50.13 0.571 ;
     RECT  54.18 0.091 54.198 0.571 ;
     RECT  57.06 0.523 57.078 0.571 ;
     RECT  26.424 0.571 26.442 0.619 ;
     RECT  22.32 0.091 22.338 1.051 ;
     RECT  7.128 0.523 7.146 1.099 ;
     RECT  9.756 0.091 9.774 1.099 ;
     RECT  14.256 0.571 14.85 1.099 ;
     RECT  23.796 0.523 23.814 1.099 ;
     RECT  24.66 0.571 25.11 1.099 ;
     RECT  26.352 0.619 26.442 1.099 ;
     RECT  31.392 0.571 31.41 1.099 ;
     RECT  40.644 0.571 40.662 1.099 ;
     RECT  41.616 0.571 42.39 1.099 ;
     RECT  43.38 0.091 43.398 1.099 ;
     RECT  44.316 1.051 44.334 1.099 ;
     RECT  45.504 0.523 45.522 1.099 ;
     RECT  47.376 0.523 47.466 1.099 ;
     RECT  56.304 0.523 56.322 1.099 ;
     RECT  57.06 0.571 57.186 1.099 ;
     RECT  62.244 0.091 62.73 1.099 ;
     RECT  5.94 0.571 5.958 1.147 ;
     RECT  16.812 0.221 16.83 1.147 ;
     RECT  21.708 1.051 22.338 1.147 ;
     RECT  29.772 0.091 30.474 1.147 ;
     RECT  31.356 1.099 31.41 1.147 ;
     RECT  32.472 0.091 32.49 1.147 ;
     RECT  39.924 1.099 42.39 1.147 ;
     RECT  53.604 0.571 54.198 1.147 ;
     RECT  56.304 1.099 57.186 1.147 ;
     RECT  58.32 0.571 58.698 1.147 ;
     RECT  60.48 0.571 60.498 1.627 ;
     RECT  23.4 1.099 25.11 1.675 ;
     RECT  33.66 1.147 33.678 1.675 ;
     RECT  62.244 1.099 62.802 1.675 ;
     RECT  2.304 0.571 2.322 1.723 ;
     RECT  4.896 0.091 4.914 1.723 ;
     RECT  5.94 1.147 6.39 1.723 ;
     RECT  7.128 1.099 7.47 1.723 ;
     RECT  8.532 1.099 8.55 1.723 ;
     RECT  9.684 1.099 9.774 1.723 ;
     RECT  10.872 0.571 10.89 1.723 ;
     RECT  12.132 0.571 12.15 1.723 ;
     RECT  13.176 1.147 13.194 1.723 ;
     RECT  14.256 1.099 15.21 1.723 ;
     RECT  16.524 1.147 16.83 1.723 ;
     RECT  18.288 0.091 18.306 1.723 ;
     RECT  20.304 0.571 20.682 1.723 ;
     RECT  21.672 1.147 22.338 1.723 ;
     RECT  23.4 1.675 25.614 1.723 ;
     RECT  26.352 1.099 26.55 1.723 ;
     RECT  27.288 0.523 27.306 1.723 ;
     RECT  28.548 0.571 28.566 1.723 ;
     RECT  29.772 1.147 32.49 1.723 ;
     RECT  33.66 1.675 34.038 1.723 ;
     RECT  35.928 0.571 36.522 1.723 ;
     RECT  37.368 0.571 37.674 1.723 ;
     RECT  39.348 1.147 42.39 1.723 ;
     RECT  43.38 1.099 44.334 1.723 ;
     RECT  45.072 1.099 48.186 1.723 ;
     RECT  49.032 0.091 49.05 1.723 ;
     RECT  49.86 0.571 50.13 1.723 ;
     RECT  51.3 0.571 51.318 1.723 ;
     RECT  52.452 1.147 54.198 1.723 ;
     RECT  55.908 1.147 57.186 1.723 ;
     RECT  58.32 1.147 58.734 1.723 ;
     RECT  60.156 1.627 60.498 1.723 ;
     RECT  61.272 1.099 61.29 1.723 ;
     RECT  58.32 1.723 61.398 1.771 ;
     RECT  62.136 1.675 62.802 1.771 ;
     RECT  1.8 1.723 38.178 2.191 ;
     RECT  39.024 1.723 57.366 2.191 ;
     RECT  58.32 1.771 62.802 2.191 ;
     RECT  1.8 2.191 62.802 2.923 ;
     RECT  1.224 2.923 62.802 3.173 ;
     RECT  1.908 3.173 62.802 3.979 ;
     RECT  1.728 3.979 62.802 4.181 ;
     RECT  1.728 4.181 62.658 4.415 ;
     RECT  2.088 4.415 62.658 4.955 ;
     RECT  0.828 5.755 0.846 6.845 ;
     RECT  2.16 4.955 62.658 6.859 ;
     RECT  1.908 6.859 62.658 7.223 ;
     RECT  2.16 7.223 62.658 9.779 ;
     RECT  2.16 9.779 62.622 12.281 ;
     RECT  2.16 12.281 62.586 12.317 ;
     RECT  42.66 12.317 62.586 12.389 ;
     RECT  42.768 12.389 62.586 12.479 ;
     RECT  2.16 12.317 41.922 13.261 ;
     RECT  42.804 12.479 62.586 13.261 ;
     RECT  2.16 13.261 62.586 16.529 ;
     RECT  7.815 16.529 62.586 17.077 ;
     RECT  2.16 16.529 6.822 17.371 ;
     RECT  7.815 17.077 62.622 17.371 ;
     RECT  2.16 17.371 62.622 17.653 ;
     RECT  2.16 17.653 62.658 18.031 ;
     RECT  2.16 18.031 62.73 19.345 ;
     RECT  63.864 14.611 63.882 19.345 ;
     RECT  2.16 19.345 63.882 20.731 ;
     RECT  1.98 20.731 63.882 21.149 ;
     RECT  1.98 21.149 63.342 21.245 ;
     RECT  1.98 21.245 63.306 21.533 ;
     RECT  1.98 21.533 25.578 21.581 ;
     RECT  1.98 21.581 6.462 21.677 ;
     RECT  7.272 21.581 25.578 21.677 ;
     RECT  26.424 21.533 63.306 21.677 ;
     RECT  26.424 21.677 53.046 21.725 ;
     RECT  26.424 21.725 29.106 21.773 ;
     RECT  30.168 21.725 53.046 21.821 ;
     RECT  30.168 21.821 50.742 21.869 ;
     RECT  51.48 21.821 53.046 21.869 ;
     RECT  30.168 21.869 48.294 22.157 ;
     RECT  26.424 21.773 28.782 22.205 ;
     RECT  30.168 22.157 34.398 22.205 ;
     RECT  35.172 22.157 48.294 22.205 ;
     RECT  49.104 21.869 50.742 22.205 ;
     RECT  58.464 21.677 63.306 22.205 ;
     RECT  7.272 21.677 20.034 22.253 ;
     RECT  27.828 22.205 28.782 22.253 ;
     RECT  35.172 22.205 35.442 22.253 ;
     RECT  37.188 22.205 48.294 22.253 ;
     RECT  51.48 21.869 52.938 22.253 ;
     RECT  58.896 22.205 63.306 22.253 ;
     RECT  30.492 22.205 33.966 22.301 ;
     RECT  13.788 22.253 17.298 22.349 ;
     RECT  51.48 22.253 52.902 22.349 ;
     RECT  13.788 22.349 16.902 22.685 ;
     RECT  32.616 22.301 33.966 22.733 ;
     RECT  58.896 22.253 62.658 22.733 ;
     RECT  2.7 21.677 6.462 22.781 ;
     RECT  7.272 22.253 12.978 22.781 ;
     RECT  13.824 22.685 16.902 22.781 ;
     RECT  20.988 21.677 25.578 22.781 ;
     RECT  26.424 22.205 26.622 22.781 ;
     RECT  28.08 22.253 28.782 22.781 ;
     RECT  30.492 22.301 31.698 22.781 ;
     RECT  32.616 22.733 32.634 22.781 ;
     RECT  33.408 22.733 33.966 22.781 ;
     RECT  37.188 22.253 39.294 22.781 ;
     RECT  40.14 22.253 44.766 22.781 ;
     RECT  45.936 22.253 48.186 22.781 ;
     RECT  51.48 22.349 52.362 22.781 ;
     RECT  53.856 21.677 57.402 22.781 ;
     RECT  58.896 22.733 58.914 22.781 ;
     RECT  59.652 22.733 62.658 22.781 ;
     RECT  18.576 22.253 20.034 22.783 ;
     RECT  20.988 22.781 21.834 22.783 ;
     RECT  3.528 22.781 4.374 22.829 ;
     RECT  7.416 22.781 9.486 22.829 ;
     RECT  12.6 22.781 12.978 22.829 ;
     RECT  15.012 22.781 16.254 22.829 ;
     RECT  18.576 22.783 21.834 22.829 ;
     RECT  22.752 22.781 22.806 22.829 ;
     RECT  28.08 22.781 28.674 22.829 ;
     RECT  37.188 22.781 37.314 22.829 ;
     RECT  42.012 22.781 44.766 22.829 ;
     RECT  49.284 22.205 50.742 22.829 ;
     RECT  54.036 22.781 55.638 22.829 ;
     RECT  60.336 22.781 62.658 22.829 ;
     RECT  7.416 22.829 7.434 22.877 ;
     RECT  8.244 22.829 9.486 22.877 ;
     RECT  28.296 22.829 28.674 22.877 ;
     RECT  60.912 22.829 62.658 22.925 ;
     RECT  62.172 22.925 62.658 23.021 ;
     RECT  26.604 22.781 26.622 23.371 ;
     RECT  30.492 22.781 31.266 23.371 ;
     RECT  30.024 23.371 31.266 23.467 ;
     RECT  2.7 22.781 2.754 23.549 ;
     RECT  35.172 22.253 35.226 23.549 ;
     RECT  15.552 22.829 16.254 23.597 ;
     RECT  18.576 22.829 19.314 23.597 ;
     RECT  23.688 22.781 24.966 23.597 ;
     RECT  28.296 22.877 28.458 23.597 ;
     RECT  29.88 23.467 31.266 23.597 ;
     RECT  33.804 22.781 33.966 23.597 ;
     RECT  50.364 22.829 50.706 23.597 ;
     RECT  51.516 22.781 51.606 23.597 ;
     RECT  54.252 22.829 55.062 23.597 ;
     RECT  56.772 22.781 56.79 23.597 ;
     RECT  2.7 23.549 2.718 23.645 ;
     RECT  3.528 22.829 3.546 23.645 ;
     RECT  6.444 22.781 6.462 23.645 ;
     RECT  8.244 22.877 9.018 23.645 ;
     RECT  11.052 22.781 11.07 23.645 ;
     RECT  12.96 22.829 12.978 23.645 ;
     RECT  15.804 23.597 16.254 23.645 ;
     RECT  18.576 23.597 19.242 23.645 ;
     RECT  21.276 22.829 21.834 23.645 ;
     RECT  22.752 22.829 22.77 23.645 ;
     RECT  23.688 23.597 23.706 23.645 ;
     RECT  24.48 23.597 24.966 23.645 ;
     RECT  26.604 23.371 27.306 23.645 ;
     RECT  28.44 23.597 28.458 23.645 ;
     RECT  29.88 23.597 30.906 23.645 ;
     RECT  33.804 23.597 33.822 23.645 ;
     RECT  35.208 23.549 35.226 23.645 ;
     RECT  39.996 23.515 40.014 23.645 ;
     RECT  42.012 22.829 42.03 23.645 ;
     RECT  43.236 22.829 43.758 23.645 ;
     RECT  44.748 22.829 44.766 23.645 ;
     RECT  45.936 22.781 47.79 23.645 ;
     RECT  48.744 23.323 49.05 23.645 ;
     RECT  50.616 23.597 50.634 23.645 ;
     RECT  51.516 23.597 51.534 23.645 ;
     RECT  54.648 23.597 55.062 23.645 ;
     RECT  60.912 22.925 60.93 23.645 ;
     RECT  62.316 23.021 62.658 23.645 ;
    LAYER M4 ;
     RECT  0.06 10.992 0.227 11.112 ;
     RECT  0.709 5.712 0.773 5.736 ;
     RECT  0.773 5.712 0.901 5.784 ;
     RECT  0.181 7.68 0.997 7.704 ;
     RECT  1.093 2.88 1.169 2.904 ;
     RECT  1.169 2.88 1.253 2.952 ;
     RECT  1.285 4.56 1.573 4.584 ;
     RECT  0.901 5.712 1.669 5.832 ;
     RECT  0.997 6.912 1.853 7.704 ;
     RECT  1.861 21.12 1.925 21.144 ;
     RECT  1.745 1.728 1.957 1.752 ;
     RECT  1.957 1.728 2.213 1.8 ;
     RECT  2.053 19.92 2.245 19.944 ;
     RECT  2.245 19.344 2.293 19.944 ;
     RECT  1.925 21.12 2.293 21.672 ;
     RECT  0.227 11.088 2.329 11.112 ;
     RECT  1.381 0.576 2.333 0.6 ;
     RECT  2.293 22.752 2.341 22.776 ;
     RECT  2.213 1.728 2.365 1.848 ;
     RECT  1.669 5.712 2.365 5.88 ;
     RECT  1.853 6.864 2.365 7.704 ;
     RECT  2.365 1.728 2.408 1.896 ;
     RECT  1.253 2.88 2.408 2.904 ;
     RECT  1.573 3.984 2.408 4.584 ;
     RECT  2.365 5.712 2.408 7.704 ;
     RECT  2.293 9.072 2.408 9.096 ;
     RECT  2.329 10.368 2.408 11.544 ;
     RECT  2.293 19.344 2.408 21.672 ;
     RECT  2.408 1.728 2.629 21.672 ;
     RECT  2.629 1.728 2.704 21.72 ;
     RECT  2.704 21.552 2.725 21.72 ;
     RECT  2.341 22.752 2.725 23.64 ;
     RECT  2.341 0.144 2.819 0.168 ;
     RECT  2.704 9.024 2.819 9.144 ;
     RECT  2.704 3.312 2.837 7.704 ;
     RECT  2.837 3.408 2.881 7.704 ;
     RECT  2.704 10.368 2.915 11.832 ;
     RECT  2.704 19.392 3.125 20.568 ;
     RECT  2.725 21.552 3.557 23.64 ;
     RECT  2.704 14.832 3.629 14.856 ;
     RECT  3.125 19.392 3.683 20.04 ;
     RECT  2.819 9.12 3.769 9.144 ;
     RECT  2.704 16.56 3.973 17.64 ;
     RECT  2.881 3.696 4.025 7.704 ;
     RECT  4.025 5.136 4.057 7.704 ;
     RECT  3.557 21.552 4.069 22.824 ;
     RECT  3.769 9.12 4.129 9.528 ;
     RECT  2.915 10.704 4.129 11.832 ;
     RECT  4.057 5.136 4.201 7.992 ;
     RECT  4.129 9.12 4.201 11.832 ;
     RECT  4.025 3.696 4.561 4.152 ;
     RECT  2.704 1.728 4.777 1.896 ;
     RECT  3.683 19.392 4.777 19.848 ;
     RECT  4.777 1.728 5.108 1.944 ;
     RECT  4.561 3.408 5.108 4.152 ;
     RECT  4.201 5.136 5.108 11.832 ;
     RECT  4.633 13.104 5.108 13.128 ;
     RECT  4.885 15.408 5.108 15.432 ;
     RECT  3.973 16.56 5.108 17.688 ;
     RECT  4.777 19.392 5.108 19.992 ;
     RECT  4.069 21.12 5.108 22.824 ;
     RECT  4.885 0.096 5.171 0.12 ;
     RECT  5.108 1.728 5.317 22.824 ;
     RECT  5.317 1.728 5.404 23.4 ;
     RECT  5.404 16.032 5.509 23.4 ;
     RECT  5.509 16.032 5.681 23.544 ;
     RECT  5.681 16.032 5.717 19.368 ;
     RECT  5.404 9.504 5.825 11.736 ;
     RECT  5.681 20.496 6.113 23.544 ;
     RECT  5.929 0.576 6.131 0.6 ;
     RECT  6.113 22.752 6.185 23.544 ;
     RECT  6.113 20.496 6.268 21.576 ;
     RECT  5.717 18.144 6.293 19.368 ;
     RECT  5.404 1.728 6.361 1.848 ;
     RECT  5.404 2.88 6.397 6.36 ;
     RECT  5.404 7.344 6.397 7.704 ;
     RECT  6.361 1.152 6.445 1.848 ;
     RECT  6.373 23.616 6.473 23.64 ;
     RECT  6.293 18.768 6.581 19.368 ;
     RECT  6.445 1.728 6.613 1.848 ;
     RECT  5.404 13.872 6.685 13.896 ;
     RECT  6.613 1.728 6.721 1.896 ;
     RECT  6.397 2.88 6.721 7.704 ;
     RECT  6.685 13.872 6.757 14.376 ;
     RECT  5.717 16.032 6.757 16.68 ;
     RECT  6.268 21.552 6.833 21.576 ;
     RECT  5.825 9.6 6.901 11.736 ;
     RECT  6.581 19.056 7.081 19.368 ;
     RECT  6.268 20.496 7.081 20.52 ;
     RECT  6.901 9.264 7.117 11.736 ;
     RECT  6.721 1.728 7.369 7.704 ;
     RECT  7.117 9.024 7.369 11.976 ;
     RECT  6.757 13.872 7.369 14.664 ;
     RECT  6.757 16.032 7.369 17.208 ;
     RECT  7.325 21.648 7.429 21.672 ;
     RECT  7.217 22.752 7.429 22.872 ;
     RECT  7.117 0.528 7.441 0.552 ;
     RECT  7.369 1.728 7.441 8.04 ;
     RECT  7.441 0.528 7.573 8.04 ;
     RECT  7.429 21.648 7.589 22.872 ;
     RECT  7.369 13.872 7.765 14.952 ;
     RECT  7.369 16.032 7.765 17.4 ;
     RECT  7.573 0.144 7.808 8.04 ;
     RECT  7.369 9.024 7.808 12.312 ;
     RECT  7.765 13.872 7.808 17.4 ;
     RECT  7.081 19.056 7.808 20.52 ;
     RECT  7.589 21.648 7.808 21.768 ;
     RECT  7.808 0.144 7.859 21.768 ;
     RECT  7.589 22.752 8.005 22.872 ;
     RECT  7.859 0.144 8.104 21.672 ;
     RECT  8.104 0.144 8.291 1.8 ;
     RECT  8.291 0.192 8.387 1.8 ;
     RECT  8.104 2.88 8.525 12.312 ;
     RECT  8.525 2.88 8.849 3.72 ;
     RECT  8.104 13.872 8.869 21.672 ;
     RECT  8.005 22.752 8.869 23.64 ;
     RECT  8.869 13.872 9.029 23.64 ;
     RECT  8.525 5.088 9.107 12.312 ;
     RECT  9.029 13.872 9.461 22.872 ;
     RECT  8.849 3.072 9.637 3.72 ;
     RECT  9.107 5.088 9.637 5.208 ;
     RECT  9.461 13.872 9.817 21.672 ;
     RECT  9.745 0.096 10.067 0.12 ;
     RECT  9.637 3.072 10.213 5.208 ;
     RECT  9.107 6.24 10.213 12.312 ;
     RECT  8.387 1.104 10.261 1.8 ;
     RECT  9.461 22.752 10.261 22.872 ;
     RECT  10.261 0.144 10.285 1.8 ;
     RECT  10.285 0.144 10.309 1.848 ;
     RECT  10.309 0.144 10.357 1.896 ;
     RECT  10.261 22.752 10.357 23.544 ;
     RECT  10.357 0.144 10.499 2.04 ;
     RECT  10.357 22.752 10.501 23.592 ;
     RECT  10.499 1.728 10.508 2.04 ;
     RECT  10.213 3.072 10.508 12.312 ;
     RECT  9.817 13.632 10.508 21.672 ;
     RECT  10.499 0.144 10.643 0.6 ;
     RECT  10.643 0.192 10.739 0.6 ;
     RECT  10.508 1.728 10.789 21.672 ;
     RECT  10.789 1.728 10.804 21.72 ;
     RECT  10.804 1.728 10.835 1.896 ;
     RECT  10.501 22.704 10.885 23.592 ;
     RECT  10.804 4.944 10.897 21.72 ;
     RECT  10.885 22.704 10.897 23.64 ;
     RECT  10.739 0.576 10.945 0.6 ;
     RECT  10.897 4.944 11.081 23.64 ;
     RECT  10.835 1.728 11.825 1.848 ;
     RECT  10.804 3.12 11.905 3.72 ;
     RECT  11.081 4.944 11.905 22.776 ;
     RECT  11.825 1.728 11.909 1.896 ;
     RECT  12.121 0.576 12.205 0.6 ;
     RECT  11.905 3.12 12.509 22.776 ;
     RECT  12.509 2.88 12.517 22.776 ;
     RECT  12.517 2.88 12.659 23.64 ;
     RECT  12.659 23.28 12.989 23.64 ;
     RECT  11.909 1.728 13.165 1.848 ;
     RECT  13.165 1.152 13.208 1.848 ;
     RECT  12.659 2.88 13.208 22.248 ;
     RECT  13.208 1.152 13.249 22.248 ;
     RECT  13.249 1.728 13.504 22.248 ;
     RECT  13.504 1.728 13.565 2.04 ;
     RECT  12.989 23.28 13.619 23.592 ;
     RECT  13.619 23.28 13.667 23.4 ;
     RECT  13.504 3.072 13.669 22.248 ;
     RECT  13.565 1.728 14.099 1.896 ;
     RECT  13.381 0.144 14.245 0.168 ;
     RECT  14.245 0.096 14.317 0.168 ;
     RECT  14.317 0.096 14.329 0.6 ;
     RECT  13.669 3.072 14.579 22.776 ;
     RECT  14.329 0.576 14.905 0.6 ;
     RECT  14.579 13.584 14.972 22.776 ;
     RECT  14.972 13.584 15.059 22.824 ;
     RECT  14.099 1.728 15.164 1.8 ;
     RECT  15.164 1.104 15.251 1.8 ;
     RECT  14.579 3.072 15.757 12.264 ;
     RECT  15.059 13.584 15.761 22.2 ;
     RECT  15.251 1.728 15.908 1.8 ;
     RECT  15.757 3.072 15.908 12.312 ;
     RECT  15.761 13.584 15.908 21.768 ;
     RECT  15.908 1.728 15.949 21.768 ;
     RECT  15.949 1.728 16.204 21.672 ;
     RECT  16.165 0.24 16.325 0.264 ;
     RECT  15.397 23.328 16.403 23.64 ;
     RECT  16.325 0.096 16.451 0.264 ;
     RECT  16.204 1.728 16.513 1.848 ;
     RECT  16.403 23.328 16.541 23.448 ;
     RECT  16.541 22.752 16.547 23.448 ;
     RECT  16.451 0.096 16.841 0.12 ;
     RECT  16.513 1.152 16.883 1.848 ;
     RECT  16.547 22.752 16.913 22.776 ;
     RECT  16.204 3.072 17.125 21.672 ;
     RECT  17.125 3.072 17.309 22.344 ;
     RECT  16.883 1.728 17.341 1.848 ;
     RECT  17.309 3.072 17.341 22.248 ;
     RECT  17.341 1.728 18.277 22.248 ;
     RECT  18.229 23.52 18.277 23.544 ;
     RECT  18.277 0.096 18.361 0.12 ;
     RECT  18.277 1.728 18.515 23.64 ;
     RECT  18.515 23.328 18.803 23.64 ;
     RECT  18.515 1.728 18.904 22.248 ;
     RECT  18.853 0.144 18.949 0.168 ;
     RECT  18.949 0.144 19.043 0.264 ;
     RECT  18.904 3.024 19.043 22.248 ;
     RECT  19.043 0.24 19.139 0.264 ;
     RECT  18.803 23.472 19.253 23.64 ;
     RECT  19.043 3.12 19.577 22.248 ;
     RECT  19.253 23.472 19.964 23.592 ;
     RECT  18.904 1.728 20.069 1.752 ;
     RECT  20.293 0.576 20.329 0.6 ;
     RECT  20.069 1.728 20.329 1.8 ;
     RECT  20.329 0.576 20.389 1.8 ;
     RECT  20.389 0.576 20.401 1.848 ;
     RECT  19.577 3.12 20.401 21.672 ;
     RECT  20.401 0.576 20.557 21.672 ;
     RECT  20.557 0.576 20.627 21.624 ;
     RECT  20.627 0.576 20.737 0.6 ;
     RECT  19.964 22.8 21.221 23.592 ;
     RECT  21.221 22.8 21.637 23.64 ;
     RECT  20.627 1.728 21.661 21.624 ;
     RECT  21.661 1.056 21.733 21.624 ;
     RECT  21.733 1.056 21.923 21.768 ;
     RECT  21.923 2.832 22.021 21.768 ;
     RECT  21.637 22.752 22.021 23.64 ;
     RECT  21.923 1.056 22.163 1.848 ;
     RECT  22.021 2.832 22.259 23.64 ;
     RECT  22.309 0.096 22.393 0.12 ;
     RECT  22.259 3.072 23.149 23.64 ;
     RECT  22.163 1.728 23.353 1.848 ;
     RECT  23.353 1.728 23.389 1.896 ;
     RECT  23.389 1.104 23.533 1.896 ;
     RECT  23.533 1.104 23.785 1.944 ;
     RECT  23.785 0.528 23.893 1.944 ;
     RECT  23.149 3.072 23.893 21.768 ;
     RECT  23.893 0.528 24.133 21.768 ;
     RECT  24.133 0.144 24.229 21.768 ;
     RECT  23.149 22.752 24.229 23.64 ;
     RECT  24.229 0.144 24.605 23.64 ;
     RECT  24.605 0.096 24.689 23.64 ;
     RECT  24.689 0.576 24.755 23.64 ;
     RECT  24.755 1.68 24.977 23.64 ;
     RECT  24.755 0.576 25.165 0.6 ;
     RECT  24.977 1.68 25.193 22.776 ;
     RECT  25.193 1.68 25.237 21.768 ;
     RECT  25.237 2.88 25.697 21.768 ;
     RECT  26.341 0.624 26.413 0.648 ;
     RECT  25.193 22.752 26.497 22.776 ;
     RECT  26.413 0.576 26.521 0.648 ;
     RECT  25.237 1.68 26.521 1.8 ;
     RECT  26.521 0.576 26.708 1.8 ;
     RECT  25.697 3.072 26.708 21.768 ;
     RECT  26.708 0.576 26.773 21.768 ;
     RECT  26.773 0.576 27.004 22.2 ;
     RECT  27.004 0.576 27.059 1.896 ;
     RECT  27.004 2.88 27.181 22.2 ;
     RECT  27.277 0.528 27.539 0.552 ;
     RECT  27.181 3.072 27.685 22.2 ;
     RECT  27.685 3.072 28.028 22.248 ;
     RECT  26.533 23.28 28.028 23.64 ;
     RECT  28.028 3.072 28.469 23.64 ;
     RECT  28.537 0.576 28.621 0.6 ;
     RECT  27.059 1.728 28.753 1.896 ;
     RECT  28.469 3.072 28.753 23.592 ;
     RECT  28.753 1.728 28.793 23.592 ;
     RECT  29.269 0.144 29.459 0.168 ;
     RECT  28.793 1.728 29.704 22.2 ;
     RECT  28.793 23.424 29.842 23.592 ;
     RECT  29.842 23.424 29.869 23.64 ;
     RECT  29.704 1.728 30.229 1.8 ;
     RECT  29.704 3.072 30.277 22.2 ;
     RECT  29.869 23.376 30.277 23.64 ;
     RECT  29.701 0.096 30.529 0.12 ;
     RECT  30.229 1.632 30.733 1.8 ;
     RECT  30.733 1.152 30.757 1.8 ;
     RECT  30.277 3.072 30.917 23.64 ;
     RECT  30.757 0.24 30.949 1.8 ;
     RECT  30.949 0.24 31.097 1.848 ;
     RECT  30.917 3.072 31.277 23.592 ;
     RECT  31.097 0.24 31.957 1.8 ;
     RECT  31.957 0.192 31.961 1.8 ;
     RECT  31.961 0.192 32.005 0.216 ;
     RECT  31.961 1.728 32.108 1.8 ;
     RECT  31.277 3.072 32.108 22.776 ;
     RECT  32.005 0.096 32.339 0.216 ;
     RECT  32.339 0.096 32.501 0.12 ;
     RECT  32.108 1.728 33.587 22.776 ;
     RECT  33.587 1.728 33.605 1.848 ;
     RECT  33.587 2.832 33.637 22.776 ;
     RECT  33.605 1.152 33.689 1.848 ;
     RECT  33.637 2.832 33.797 23.64 ;
     RECT  33.797 23.568 33.833 23.64 ;
     RECT  33.833 23.568 33.977 23.592 ;
     RECT  33.689 1.68 34.067 1.848 ;
     RECT  33.797 2.832 34.409 22.2 ;
     RECT  34.067 1.728 34.652 1.848 ;
     RECT  34.409 2.832 34.652 22.152 ;
     RECT  34.789 23.376 34.885 23.4 ;
     RECT  34.885 23.28 35.077 23.4 ;
     RECT  35.077 23.28 35.219 23.64 ;
     RECT  35.219 23.376 35.237 23.64 ;
     RECT  35.237 23.376 35.245 23.544 ;
     RECT  35.245 23.376 35.267 23.4 ;
     RECT  34.652 1.728 35.413 22.152 ;
     RECT  35.413 1.728 35.507 22.248 ;
     RECT  35.909 0.576 35.917 0.6 ;
     RECT  35.917 0.48 36.083 0.6 ;
     RECT  36.083 0.576 36.277 0.6 ;
     RECT  35.507 1.728 36.277 22.2 ;
     RECT  36.613 23.424 36.709 23.448 ;
     RECT  36.277 0.576 36.851 22.2 ;
     RECT  36.851 1.68 37.093 22.2 ;
     RECT  36.709 23.424 37.093 23.544 ;
     RECT  37.093 1.68 37.333 23.544 ;
     RECT  36.851 0.576 37.729 0.6 ;
     RECT  37.333 1.68 38.099 23.592 ;
     RECT  38.099 2.88 38.147 23.592 ;
     RECT  38.099 1.68 38.291 1.848 ;
     RECT  38.291 1.728 39.337 1.848 ;
     RECT  38.147 2.88 39.877 22.776 ;
     RECT  39.337 1.152 39.913 1.848 ;
     RECT  39.877 2.88 39.941 23.592 ;
     RECT  39.913 1.104 39.949 1.848 ;
     RECT  39.941 2.88 39.949 23.64 ;
     RECT  39.949 1.104 40.021 23.64 ;
     RECT  40.021 0.144 40.025 23.64 ;
     RECT  40.025 0.144 40.163 23.592 ;
     RECT  40.163 0.144 40.307 22.776 ;
     RECT  40.307 0.576 40.504 22.776 ;
     RECT  40.504 0.576 41.075 1.848 ;
     RECT  40.504 2.88 41.429 22.776 ;
     RECT  41.075 1.728 41.66 1.848 ;
     RECT  41.429 2.88 41.66 10.344 ;
     RECT  41.66 1.728 41.747 10.344 ;
     RECT  41.429 11.664 41.893 22.776 ;
     RECT  41.893 11.664 42.041 23.64 ;
     RECT  41.075 0.576 42.14 0.6 ;
     RECT  42.14 0.528 42.445 0.6 ;
     RECT  41.747 1.728 42.757 1.848 ;
     RECT  41.747 2.88 42.757 10.344 ;
     RECT  42.041 11.664 42.757 22.824 ;
     RECT  42.757 1.728 43.01 22.824 ;
     RECT  43.01 22.752 43.141 22.824 ;
     RECT  42.949 0.144 43.33 0.168 ;
     RECT  43.33 0.096 43.331 0.168 ;
     RECT  43.01 1.728 43.337 21.768 ;
     RECT  43.337 1.728 43.763 1.896 ;
     RECT  43.763 1.728 43.945 1.848 ;
     RECT  43.331 0.096 44.051 0.12 ;
     RECT  43.337 2.88 44.101 21.768 ;
     RECT  43.141 22.752 44.101 23.64 ;
     RECT  44.101 2.88 44.273 23.64 ;
     RECT  43.945 1.104 44.305 1.848 ;
     RECT  44.305 1.056 44.531 1.848 ;
     RECT  44.273 22.8 44.723 23.64 ;
     RECT  44.531 1.104 45.125 1.848 ;
     RECT  45.125 1.104 45.145 1.896 ;
     RECT  44.273 2.88 45.457 21.768 ;
     RECT  45.145 1.728 45.608 1.896 ;
     RECT  45.457 2.88 45.608 22.248 ;
     RECT  45.493 0.528 45.683 0.552 ;
     RECT  45.608 1.728 45.683 22.248 ;
     RECT  45.683 1.728 45.904 21.768 ;
     RECT  44.723 23.616 45.925 23.64 ;
     RECT  45.904 1.728 45.965 2.04 ;
     RECT  45.965 1.728 46.037 1.992 ;
     RECT  46.037 1.728 46.172 1.8 ;
     RECT  45.925 23.568 46.565 23.64 ;
     RECT  46.565 23.472 46.652 23.64 ;
     RECT  46.652 22.8 46.789 23.64 ;
     RECT  46.172 1.104 47.027 1.8 ;
     RECT  47.027 1.728 47.141 1.8 ;
     RECT  45.904 3.072 47.189 21.768 ;
     RECT  47.324 0.528 47.41 0.552 ;
     RECT  47.41 0.48 47.507 0.552 ;
     RECT  47.189 12.768 47.557 21.768 ;
     RECT  46.789 22.752 47.557 23.64 ;
     RECT  47.141 1.728 47.689 1.848 ;
     RECT  47.689 1.728 48.085 1.896 ;
     RECT  48.085 1.728 48.157 1.992 ;
     RECT  48.157 1.104 48.308 1.992 ;
     RECT  47.189 3.072 48.308 11.688 ;
     RECT  47.557 12.768 48.308 23.64 ;
     RECT  48.308 1.104 48.563 23.64 ;
     RECT  48.563 1.728 48.604 23.64 ;
     RECT  48.604 1.728 48.947 1.896 ;
     RECT  48.957 0.096 49.061 0.12 ;
     RECT  48.604 13.632 49.139 23.64 ;
     RECT  48.604 3.072 49.621 11.688 ;
     RECT  49.849 0.576 49.933 0.6 ;
     RECT  48.947 1.728 50.065 1.848 ;
     RECT  49.621 2.832 50.065 11.688 ;
     RECT  49.139 13.632 50.149 23.592 ;
     RECT  50.101 0.528 50.195 0.552 ;
     RECT  50.065 1.728 51.008 11.688 ;
     RECT  50.149 13.632 51.008 23.64 ;
     RECT  50.869 0.144 51.155 0.168 ;
     RECT  51.008 1.728 51.304 23.64 ;
     RECT  51.289 0.576 51.373 0.6 ;
     RECT  51.304 13.104 51.545 23.64 ;
     RECT  51.545 13.104 52.211 23.592 ;
     RECT  52.211 13.632 52.373 23.592 ;
     RECT  51.304 1.728 52.441 11.688 ;
     RECT  52.441 1.152 52.589 11.688 ;
     RECT  52.589 1.152 53.593 10.872 ;
     RECT  52.373 13.632 53.605 22.344 ;
     RECT  52.373 23.568 53.605 23.592 ;
     RECT  53.593 0.576 53.677 10.872 ;
     RECT  53.677 1.104 53.708 10.872 ;
     RECT  53.605 13.632 53.708 23.592 ;
     RECT  53.708 1.104 53.939 23.592 ;
     RECT  53.939 1.728 54.004 23.592 ;
     RECT  54.004 13.392 54.065 23.592 ;
     RECT  54.065 23.424 54.131 23.592 ;
     RECT  54.169 0.096 54.253 0.12 ;
     RECT  54.131 23.568 54.469 23.592 ;
     RECT  54.004 1.728 54.611 10.68 ;
     RECT  54.469 23.568 55.073 23.64 ;
     RECT  54.611 2.832 55.217 10.68 ;
     RECT  54.065 13.392 55.333 21.864 ;
     RECT  54.004 11.664 55.573 11.688 ;
     RECT  55.333 13.392 55.58 22.2 ;
     RECT  54.611 1.728 55.897 1.848 ;
     RECT  55.897 1.152 56.005 1.848 ;
     RECT  55.217 2.832 56.005 10.632 ;
     RECT  55.58 13.392 56.245 22.824 ;
     RECT  56.005 1.152 56.257 10.632 ;
     RECT  56.257 1.152 56.293 10.68 ;
     RECT  56.293 0.528 56.408 10.68 ;
     RECT  55.573 11.664 56.408 11.976 ;
     RECT  56.245 13.392 56.408 23.592 ;
     RECT  56.408 0.528 56.627 23.592 ;
     RECT  56.627 1.728 56.704 23.592 ;
     RECT  56.704 13.632 56.845 23.592 ;
     RECT  56.845 13.632 56.963 23.544 ;
     RECT  56.704 2.832 57.089 11.688 ;
     RECT  56.627 0.528 57.107 0.6 ;
     RECT  57.107 0.576 57.241 0.6 ;
     RECT  56.704 1.728 57.377 1.8 ;
     RECT  57.089 2.832 57.377 9.384 ;
     RECT  57.377 1.776 57.395 1.8 ;
     RECT  57.089 10.416 57.449 11.688 ;
     RECT  57.449 10.416 57.485 10.632 ;
     RECT  57.485 10.416 57.521 10.44 ;
     RECT  56.963 13.632 57.635 23.112 ;
     RECT  57.449 11.664 57.692 11.688 ;
     RECT  57.692 11.664 57.779 11.88 ;
     RECT  57.635 13.632 57.923 22.2 ;
     RECT  57.377 2.832 58.201 5.928 ;
     RECT  58.201 2.256 58.381 5.928 ;
     RECT  57.377 7.2 58.381 9.384 ;
     RECT  58.381 2.256 58.453 9.384 ;
     RECT  58.453 1.728 58.597 9.384 ;
     RECT  57.923 16.272 58.637 22.2 ;
     RECT  58.309 0.576 58.693 0.6 ;
     RECT  58.597 1.728 58.693 9.576 ;
     RECT  58.693 0.576 58.78 9.576 ;
     RECT  58.637 16.272 58.781 21.624 ;
     RECT  58.693 22.704 58.837 22.776 ;
     RECT  58.78 0.576 58.931 0.6 ;
     RECT  58.78 1.728 59.108 9.576 ;
     RECT  57.779 11.664 59.108 11.688 ;
     RECT  57.923 13.632 59.108 15.288 ;
     RECT  58.781 16.272 59.108 21.612 ;
     RECT  59.108 1.728 59.404 21.612 ;
     RECT  59.365 0.384 59.557 0.504 ;
     RECT  59.557 0.192 59.612 0.504 ;
     RECT  59.404 6.816 59.681 9.624 ;
     RECT  59.612 0.096 59.699 0.504 ;
     RECT  59.699 0.192 59.747 0.504 ;
     RECT  59.404 13.632 59.933 20.664 ;
     RECT  58.837 22.704 59.941 23.592 ;
     RECT  59.404 1.728 60.145 5.784 ;
     RECT  59.941 21.648 60.421 23.592 ;
     RECT  60.145 1.632 60.433 5.784 ;
     RECT  59.681 6.816 60.433 9.288 ;
     RECT  59.933 13.632 60.473 15.288 ;
     RECT  59.404 11.664 60.509 11.688 ;
     RECT  59.933 20.304 60.581 20.664 ;
     RECT  60.433 1.632 60.757 9.288 ;
     RECT  59.933 16.56 60.761 18.984 ;
     RECT  60.421 21.648 60.761 23.64 ;
     RECT  60.473 14.784 60.901 15.288 ;
     RECT  60.761 16.56 60.901 17.112 ;
     RECT  60.761 22.656 60.941 23.64 ;
     RECT  60.757 1.632 61.189 9.912 ;
     RECT  61.189 1.632 61.225 10.248 ;
     RECT  60.469 0.576 61.261 0.6 ;
     RECT  61.225 1.632 61.261 10.68 ;
     RECT  60.761 18.528 61.573 18.984 ;
     RECT  60.581 20.496 61.585 20.664 ;
     RECT  60.761 21.648 61.585 21.672 ;
     RECT  61.261 0.576 61.621 10.68 ;
     RECT  61.621 0.144 61.765 10.68 ;
     RECT  61.765 0.144 61.808 10.728 ;
     RECT  60.473 13.632 61.808 13.656 ;
     RECT  60.901 14.784 61.808 17.112 ;
     RECT  61.573 18.528 61.808 19.128 ;
     RECT  61.585 20.496 61.808 21.672 ;
     RECT  61.808 0.144 61.945 21.672 ;
     RECT  60.941 22.656 61.945 22.92 ;
     RECT  61.945 0.144 62.099 22.92 ;
     RECT  62.099 1.104 62.104 22.92 ;
     RECT  62.104 19.056 62.129 22.92 ;
     RECT  62.129 19.392 62.161 22.92 ;
     RECT  62.104 6.864 62.237 10.728 ;
     RECT  62.104 1.104 62.243 4.44 ;
     RECT  62.104 5.76 62.243 5.784 ;
     RECT  62.161 19.392 62.245 23.016 ;
     RECT  62.243 1.104 62.309 3.096 ;
     RECT  62.237 6.864 62.345 9.096 ;
     RECT  62.345 6.864 62.381 8.568 ;
     RECT  62.104 16.608 62.381 17.112 ;
     RECT  62.237 10.704 62.417 10.728 ;
     RECT  62.381 16.608 62.453 16.824 ;
     RECT  62.243 4.416 62.525 4.44 ;
     RECT  62.381 6.864 62.525 7.752 ;
     RECT  62.309 2.112 62.531 3.096 ;
     RECT  62.525 6.864 62.569 6.888 ;
     RECT  62.245 19.392 62.579 23.64 ;
     RECT  62.453 16.8 62.597 16.824 ;
     RECT  62.531 2.112 62.675 2.136 ;
     RECT  62.233 0.096 62.785 0.12 ;
     RECT  62.309 1.104 62.867 1.128 ;
     RECT  62.579 19.872 62.963 23.64 ;
     RECT  62.963 21.12 63.059 23.64 ;
     RECT  63.059 23.616 63.155 23.64 ;
     RECT  63.059 21.12 63.347 22.248 ;
     RECT  63.347 21.12 63.443 21.336 ;
     RECT  62.963 19.872 63.635 19.992 ;
     RECT  63.635 19.92 63.731 19.992 ;
     RECT  63.731 19.968 63.827 19.992 ;
     RECT  63.443 21.12 63.923 21.24 ;
     RECT  63.923 21.12 64.019 21.144 ;
    LAYER M5 ;
     RECT  0.72 0.016 62.856 1.139 ;
     RECT  0.72 1.139 62.664 1.763 ;
     RECT  20.112 1.763 38.088 1.811 ;
     RECT  0.72 1.763 19.128 1.859 ;
     RECT  20.4 1.811 30.984 1.859 ;
     RECT  39.216 1.763 62.664 1.859 ;
     RECT  0.72 1.859 10.824 1.907 ;
     RECT  11.856 1.859 19.128 1.907 ;
     RECT  39.936 1.859 43.752 1.907 ;
     RECT  45.168 1.859 62.664 1.907 ;
     RECT  4.944 1.907 10.812 1.955 ;
     RECT  50.736 1.907 62.664 2.147 ;
     RECT  20.496 1.859 30.216 2.243 ;
     RECT  31.968 1.811 38.088 2.291 ;
     RECT  39.936 1.907 43.368 2.291 ;
     RECT  50.736 2.147 62.52 2.291 ;
     RECT  14.64 1.907 19.128 2.339 ;
     RECT  36.624 2.291 38.088 2.339 ;
     RECT  20.88 2.243 30.216 2.867 ;
     RECT  42.576 2.291 43.368 3.109 ;
     RECT  42.576 3.109 44.184 3.301 ;
     RECT  45.6 1.907 49.656 3.301 ;
     RECT  36.624 2.339 37.812 3.397 ;
     RECT  50.736 2.291 54.012 3.397 ;
     RECT  55.152 2.291 62.52 3.397 ;
     RECT  0.72 1.907 3.144 3.685 ;
     RECT  5.1 1.955 10.812 3.733 ;
     RECT  18.384 2.339 19.128 3.733 ;
     RECT  50.736 3.397 62.52 3.923 ;
     RECT  31.968 2.291 35.112 3.925 ;
     RECT  36.624 3.397 37.944 3.971 ;
     RECT  20.88 2.867 21.912 3.973 ;
     RECT  22.992 2.867 30.216 3.973 ;
     RECT  14.64 2.339 17.256 4.019 ;
     RECT  20.88 3.973 30.216 4.019 ;
     RECT  18.384 3.733 19.752 4.549 ;
     RECT  20.88 4.019 29.928 4.549 ;
     RECT  11.952 1.907 13.656 4.595 ;
     RECT  31.92 3.925 35.112 4.595 ;
     RECT  39.936 2.291 40.968 4.787 ;
     RECT  58.512 3.923 62.52 4.787 ;
     RECT  42.576 3.301 49.656 4.835 ;
     RECT  18.384 4.549 29.928 4.933 ;
     RECT  58.512 4.787 60.648 4.981 ;
     RECT  17.664 4.933 29.928 5.077 ;
     RECT  14.64 4.019 16.44 5.123 ;
     RECT  31.92 4.595 33.384 5.125 ;
     RECT  15.552 5.123 16.44 5.171 ;
     RECT  38.928 5.125 38.952 5.173 ;
     RECT  39.936 4.787 40.512 5.173 ;
     RECT  50.736 3.923 57.48 5.267 ;
     RECT  58.464 4.981 60.648 5.267 ;
     RECT  0.72 3.685 3.384 5.413 ;
     RECT  4.896 3.733 10.812 5.413 ;
     RECT  38.928 5.173 40.512 5.651 ;
     RECT  50.784 5.267 57.48 5.651 ;
     RECT  0.72 5.413 10.812 5.747 ;
     RECT  17.664 5.077 30.216 5.747 ;
     RECT  36.624 3.971 37.812 5.747 ;
     RECT  0.816 5.747 10.812 5.795 ;
     RECT  12.624 4.595 13.656 5.795 ;
     RECT  58.512 5.267 60.648 5.795 ;
     RECT  0.912 5.795 10.812 5.843 ;
     RECT  51 5.651 57.48 5.843 ;
     RECT  15.9 5.171 16.44 5.941 ;
     RECT  17.664 5.747 22.344 5.941 ;
     RECT  31.872 5.125 33.384 6.227 ;
     RECT  34.464 4.595 35.112 6.229 ;
     RECT  42.768 4.835 49.656 6.229 ;
     RECT  1.008 5.843 10.812 6.275 ;
     RECT  51 5.843 56.712 6.323 ;
     RECT  60.624 5.795 60.648 6.323 ;
     RECT  53.232 6.323 56.712 6.371 ;
     RECT  15.9 5.941 22.344 6.419 ;
     RECT  31.872 6.227 32.616 6.563 ;
     RECT  12.624 5.795 13.512 6.611 ;
     RECT  17.664 6.419 22.344 6.611 ;
     RECT  1.008 6.275 8.712 6.707 ;
     RECT  17.808 6.611 22.344 6.803 ;
     RECT  4.896 6.707 8.712 6.851 ;
     RECT  34.464 6.229 35.352 6.853 ;
     RECT  36.768 5.747 37.812 6.853 ;
     RECT  61.8 4.787 62.52 6.899 ;
     RECT  1.008 6.707 3.384 6.947 ;
     RECT  17.808 6.803 21.816 6.947 ;
     RECT  15.9 6.419 16.584 6.949 ;
     RECT  42.48 6.229 49.656 6.995 ;
     RECT  53.7 6.371 56.712 7.093 ;
     RECT  18.288 6.947 21.816 7.139 ;
     RECT  31.872 6.563 32.52 7.187 ;
     RECT  4.896 6.851 8.52 7.379 ;
     RECT  20.736 7.139 21.816 7.427 ;
     RECT  34.464 6.853 37.812 7.427 ;
     RECT  47.04 6.995 49.656 7.429 ;
     RECT  51 6.323 51.528 7.429 ;
     RECT  1.488 6.947 3.384 7.475 ;
     RECT  14.976 6.949 16.584 7.477 ;
     RECT  23.568 5.747 30.216 7.571 ;
     RECT  31.968 7.187 32.52 7.571 ;
     RECT  14.928 7.477 16.584 7.573 ;
     RECT  47.04 7.429 51.912 7.573 ;
     RECT  34.56 7.427 37.812 7.621 ;
     RECT  39.36 5.651 40.512 7.621 ;
     RECT  47.04 7.573 52.296 7.667 ;
     RECT  14.832 7.573 16.584 7.715 ;
     RECT  24 7.571 30.216 7.715 ;
     RECT  14.976 7.715 16.584 7.811 ;
     RECT  42.576 6.995 46.056 7.859 ;
     RECT  2.4 7.475 3.384 8.053 ;
     RECT  4.896 7.379 8.112 8.053 ;
     RECT  18.288 7.139 19.752 8.101 ;
     RECT  53.7 7.093 57 8.339 ;
     RECT  18.24 8.101 19.752 8.579 ;
     RECT  31.968 7.571 32.412 8.579 ;
     RECT  42.9 7.859 46.056 8.579 ;
     RECT  55.2 8.339 57 8.579 ;
     RECT  58.512 5.795 59.412 8.579 ;
     RECT  21.12 7.427 21.816 8.581 ;
     RECT  47.04 7.667 49.656 8.675 ;
     RECT  18.6 8.579 19.752 8.677 ;
     RECT  20.736 8.581 21.816 8.677 ;
     RECT  22.992 7.813 23.016 8.723 ;
     RECT  55.2 8.579 56.712 8.819 ;
     RECT  41.616 8.533 41.64 8.915 ;
     RECT  13.2 6.611 13.512 8.965 ;
     RECT  18.6 8.677 21.816 9.059 ;
     RECT  2.4 8.053 8.112 9.155 ;
     RECT  24 7.715 28.2 9.157 ;
     RECT  29.4 7.715 30.216 9.253 ;
     RECT  4.464 9.155 8.112 9.299 ;
     RECT  21.072 9.059 21.816 9.299 ;
     RECT  21.072 9.299 21.768 9.347 ;
     RECT  32.1 8.579 32.412 9.349 ;
     RECT  29.4 9.253 30.84 9.395 ;
     RECT  32.1 9.349 33.096 9.491 ;
     RECT  13.2 8.965 13.608 9.541 ;
     RECT  21.12 9.347 21.768 9.683 ;
     RECT  4.464 9.299 6.552 9.731 ;
     RECT  9.216 8.965 9.24 9.731 ;
     RECT  23.904 9.157 28.2 9.733 ;
     RECT  34.56 7.621 40.512 9.781 ;
     RECT  55.728 8.819 56.712 9.827 ;
     RECT  23.424 9.733 28.2 9.923 ;
     RECT  34.56 9.781 40.872 9.923 ;
     RECT  4.896 9.731 6.552 10.019 ;
     RECT  24 9.923 28.2 10.021 ;
     RECT  29.4 9.395 30.216 10.021 ;
     RECT  34.56 9.923 40.632 10.067 ;
     RECT  21.12 9.683 21.72 10.115 ;
     RECT  18.6 9.059 19.752 10.117 ;
     RECT  24 10.021 30.216 10.163 ;
     RECT  21.3 10.115 21.72 10.259 ;
     RECT  15.9 7.811 16.584 10.307 ;
     RECT  34.56 10.067 40.512 10.307 ;
     RECT  34.56 10.307 38.808 10.355 ;
     RECT  51 7.667 52.296 10.403 ;
     RECT  56.304 9.827 56.712 10.403 ;
     RECT  12.864 9.541 13.608 10.451 ;
     RECT  13.2 10.451 13.608 10.597 ;
     RECT  18.6 10.117 19.944 10.643 ;
     RECT  13.2 10.597 14.088 10.739 ;
     RECT  34.56 10.355 38.472 10.837 ;
     RECT  0.192 7.669 0.216 11.027 ;
     RECT  18.6 10.643 19.752 11.029 ;
     RECT  47.04 8.675 48.612 11.125 ;
     RECT  49.632 8.675 49.656 11.125 ;
     RECT  47.04 11.125 49.656 11.221 ;
     RECT  51 10.403 52.152 11.221 ;
     RECT  2.4 9.155 3.384 11.365 ;
     RECT  47.04 11.221 52.152 11.413 ;
     RECT  4.896 10.019 6.312 11.555 ;
     RECT  53.7 8.339 54.012 11.653 ;
     RECT  17.808 11.029 19.752 11.699 ;
     RECT  21.3 10.259 21.612 11.749 ;
     RECT  24 10.163 28.2 11.941 ;
     RECT  29.4 10.163 30.216 11.941 ;
     RECT  56.4 10.403 56.712 11.941 ;
     RECT  40.2 10.307 40.512 11.989 ;
     RECT  21.3 11.749 21.912 12.037 ;
     RECT  10.5 6.275 10.812 12.229 ;
     RECT  34.08 10.837 38.472 12.275 ;
     RECT  24 11.941 30.216 12.277 ;
     RECT  40.2 11.989 41.304 12.277 ;
     RECT  34.08 12.275 37.944 12.517 ;
     RECT  42.9 8.579 45.912 12.517 ;
     RECT  46.944 11.413 52.152 12.517 ;
     RECT  14.592 10.885 14.616 13.045 ;
     RECT  21.3 12.037 21.96 13.045 ;
     RECT  23.088 12.277 30.216 13.045 ;
     RECT  4.896 11.555 5.412 13.093 ;
     RECT  42.9 12.517 52.152 13.093 ;
     RECT  38.928 12.853 38.952 13.187 ;
     RECT  33.888 12.517 37.944 13.285 ;
     RECT  21.3 13.045 30.216 13.573 ;
     RECT  53.7 11.653 54.456 13.621 ;
     RECT  55.584 11.941 56.712 13.621 ;
     RECT  42.9 13.093 52.2 13.715 ;
     RECT  57.744 11.845 57.768 13.813 ;
     RECT  10.5 12.229 11.112 13.909 ;
     RECT  21.3 13.573 30.648 13.909 ;
     RECT  9.936 13.909 11.112 14.101 ;
     RECT  15.9 10.307 16.212 14.197 ;
     RECT  18.6 11.699 19.752 14.197 ;
     RECT  20.784 13.909 30.744 14.197 ;
     RECT  33.888 13.285 38.712 14.437 ;
     RECT  33.888 14.437 38.808 14.485 ;
     RECT  61.8 6.899 62.112 14.773 ;
     RECT  33.456 14.485 38.808 14.819 ;
     RECT  14.544 13.045 14.616 15.013 ;
     RECT  15.6 14.197 16.212 15.013 ;
     RECT  40.2 12.277 41.4 15.301 ;
     RECT  42.9 13.715 46.968 15.301 ;
     RECT  48.3 13.715 49.272 15.349 ;
     RECT  50.4 13.715 52.2 15.349 ;
     RECT  14.544 15.013 16.212 15.637 ;
     RECT  33.648 14.819 38.808 15.637 ;
     RECT  61.008 14.773 62.112 15.637 ;
     RECT  59.1 8.579 59.412 15.925 ;
     RECT  40.2 15.301 46.968 15.973 ;
     RECT  48.3 15.349 52.2 16.261 ;
     RECT  18.6 14.197 30.744 16.357 ;
     RECT  60.912 15.637 62.112 16.549 ;
     RECT  53.7 13.621 56.712 16.837 ;
     RECT  57.744 13.813 57.96 16.837 ;
     RECT  17.904 16.357 30.744 16.933 ;
     RECT  4.8 13.093 5.412 16.981 ;
     RECT  2.4 11.365 3.528 17.029 ;
     RECT  4.512 16.981 5.412 17.029 ;
     RECT  40.2 15.973 47.016 17.029 ;
     RECT  53.7 16.837 57.96 17.029 ;
     RECT  59.1 15.925 59.784 17.029 ;
     RECT  60.816 16.549 62.112 17.029 ;
     RECT  13.2 10.739 13.512 17.077 ;
     RECT  14.496 15.637 16.212 17.077 ;
     RECT  32.1 9.491 32.412 17.077 ;
     RECT  33.648 15.637 38.952 17.077 ;
     RECT  48.3 16.261 52.632 17.077 ;
     RECT  53.7 17.029 62.112 17.077 ;
     RECT  13.2 17.077 16.212 17.221 ;
     RECT  17.904 16.933 30.888 17.221 ;
     RECT  32.1 17.077 38.952 17.221 ;
     RECT  17.904 17.221 38.952 17.317 ;
     RECT  40.2 17.029 47.064 17.317 ;
     RECT  17.904 17.317 47.064 17.365 ;
     RECT  2.4 17.029 5.412 17.509 ;
     RECT  9.936 14.101 11.832 17.605 ;
     RECT  13.2 17.221 16.44 17.605 ;
     RECT  17.904 17.365 47.112 17.605 ;
     RECT  13.008 17.605 47.112 17.653 ;
     RECT  48.3 17.077 62.112 17.653 ;
     RECT  9.936 17.605 11.976 17.797 ;
     RECT  13.008 17.653 62.112 17.797 ;
     RECT  2.4 17.509 5.544 18.037 ;
     RECT  2.4 18.037 5.64 18.133 ;
     RECT  7.8 9.299 8.112 18.229 ;
     RECT  9.936 17.797 62.112 18.229 ;
     RECT  2.4 18.133 5.688 18.757 ;
     RECT  7.8 18.229 62.112 18.851 ;
     RECT  2.4 18.757 6.024 19.333 ;
     RECT  10.224 18.851 62.112 19.381 ;
     RECT  2.256 19.333 6.12 19.909 ;
     RECT  7.8 18.851 9.096 19.909 ;
     RECT  10.224 19.381 62.568 19.909 ;
     RECT  63.6 19.861 63.624 19.909 ;
     RECT  63.6 19.909 63.72 19.957 ;
     RECT  7.8 19.909 62.568 20.533 ;
     RECT  63.6 19.957 63.816 20.533 ;
     RECT  2.064 19.909 6.12 21.109 ;
     RECT  7.8 20.533 63.816 21.109 ;
     RECT  1.872 21.109 6.12 21.301 ;
     RECT  1.872 21.301 6.216 21.541 ;
     RECT  7.8 21.109 64.008 21.637 ;
     RECT  1.872 21.541 6.312 22.741 ;
     RECT  7.344 21.637 64.008 22.741 ;
     RECT  1.872 22.741 64.008 23.696 ;
     RECT  19.128 1.763 20.112 1.811 ;
     RECT  38.088 1.763 39.216 1.859 ;
     RECT  19.128 1.811 20.4 1.859 ;
     RECT  30.984 1.811 31.968 1.859 ;
     RECT  10.824 1.859 11.856 1.907 ;
     RECT  19.128 1.859 20.496 2.243 ;
     RECT  43.752 1.859 45.168 1.907 ;
     RECT  10.812 1.907 11.952 4.595 ;
     RECT  13.656 1.907 14.64 5.123 ;
     RECT  43.368 1.907 45.6 3.109 ;
     RECT  49.656 1.907 50.736 5.267 ;
     RECT  19.128 2.243 20.88 3.733 ;
     RECT  35.112 2.291 36.624 5.747 ;
     RECT  54.012 2.291 55.152 3.397 ;
     RECT  17.256 2.339 18.384 4.019 ;
     RECT  37.812 2.339 37.944 3.397 ;
     RECT  21.912 2.867 22.992 3.973 ;
     RECT  44.184 3.109 45.6 3.301 ;
     RECT  3.384 3.733 4.896 5.413 ;
     RECT  19.752 3.733 20.88 4.549 ;
     RECT  57.48 3.923 58.512 4.981 ;
     RECT  37.812 3.971 37.944 5.125 ;
     RECT  16.44 4.019 18.384 4.933 ;
     RECT  29.928 4.019 30.216 5.077 ;
     RECT  33.384 4.595 34.464 6.227 ;
     RECT  60.648 4.787 61.8 6.323 ;
     RECT  42.576 4.835 42.768 6.229 ;
     RECT  16.44 4.933 17.664 5.941 ;
     RECT  57.48 4.981 58.464 5.267 ;
     RECT  37.812 5.125 38.928 5.651 ;
     RECT  38.952 5.125 39.936 5.173 ;
     RECT  49.656 5.267 50.784 5.651 ;
     RECT  57.48 5.267 58.512 5.843 ;
     RECT  49.656 5.651 51 7.429 ;
     RECT  22.344 5.747 23.568 6.803 ;
     RECT  35.112 5.747 36.768 6.229 ;
     RECT  13.512 5.795 13.656 6.949 ;
     RECT  59.412 5.795 60.624 6.323 ;
     RECT  56.712 5.843 58.512 7.093 ;
     RECT  35.352 6.229 36.768 6.853 ;
     RECT  51.528 6.323 53.232 6.371 ;
     RECT  51.528 6.371 53.7 7.429 ;
     RECT  16.584 6.419 17.664 6.611 ;
     RECT  16.584 6.611 17.808 6.947 ;
     RECT  3.384 6.707 4.896 8.053 ;
     RECT  21.816 6.803 23.568 7.571 ;
     RECT  18.24 6.947 18.288 8.101 ;
     RECT  13.512 6.949 14.976 7.477 ;
     RECT  46.056 6.995 47.04 8.579 ;
     RECT  57 7.093 58.512 8.579 ;
     RECT  19.752 7.139 20.736 7.427 ;
     RECT  19.752 7.427 21.12 8.581 ;
     RECT  51.912 7.429 53.7 7.573 ;
     RECT  13.512 7.477 14.928 7.573 ;
     RECT  21.816 7.571 24 7.813 ;
     RECT  13.512 7.573 14.832 7.715 ;
     RECT  52.296 7.573 53.7 10.403 ;
     RECT  49.656 7.667 51 11.221 ;
     RECT  13.512 7.715 14.976 7.811 ;
     RECT  28.2 7.715 29.4 10.021 ;
     RECT  13.512 7.811 13.608 8.965 ;
     RECT  21.816 7.813 22.992 8.723 ;
     RECT  23.016 7.813 24 8.723 ;
     RECT  42.576 7.859 42.9 8.533 ;
     RECT  54.012 8.339 55.2 8.819 ;
     RECT  40.512 8.533 41.616 8.915 ;
     RECT  41.64 8.533 42.9 8.915 ;
     RECT  31.968 8.579 32.1 9.253 ;
     RECT  45.912 8.579 47.04 11.413 ;
     RECT  19.752 8.581 20.736 8.677 ;
     RECT  48.612 8.675 49.632 11.125 ;
     RECT  23.424 8.723 24 9.157 ;
     RECT  40.512 8.915 40.872 9.781 ;
     RECT  8.112 8.965 9.216 9.731 ;
     RECT  9.24 8.965 10.5 9.731 ;
     RECT  19.752 9.059 21.072 9.347 ;
     RECT  3.384 9.155 4.464 9.731 ;
     RECT  23.424 9.157 23.904 9.733 ;
     RECT  30.84 9.253 32.1 9.395 ;
     RECT  6.552 9.299 7.8 10.019 ;
     RECT  19.752 9.347 21.12 10.115 ;
     RECT  33.096 9.349 34.56 9.491 ;
     RECT  34.08 9.491 34.56 10.837 ;
     RECT  3.384 9.731 4.896 11.365 ;
     RECT  6.312 10.019 7.8 11.555 ;
     RECT  19.752 10.115 21.3 10.117 ;
     RECT  19.944 10.117 21.3 10.643 ;
     RECT  28.2 10.163 29.4 11.941 ;
     RECT  21.612 10.259 21.72 11.749 ;
     RECT  38.808 10.307 40.2 10.355 ;
     RECT  13.512 10.739 14.088 10.885 ;
     RECT  13.512 10.885 14.592 13.045 ;
     RECT  14.616 10.885 15.9 14.197 ;
     RECT  3.528 11.365 4.896 13.093 ;
     RECT  45.912 11.413 46.944 12.517 ;
     RECT  56.712 11.845 57.744 16.837 ;
     RECT  57.768 11.845 59.1 13.813 ;
     RECT  54.456 11.941 55.584 13.621 ;
     RECT  37.944 12.275 38.472 12.853 ;
     RECT  21.96 12.277 23.088 13.045 ;
     RECT  41.4 12.277 42.9 15.301 ;
     RECT  32.412 12.517 33.888 14.485 ;
     RECT  37.944 12.853 38.928 13.187 ;
     RECT  38.952 12.853 40.2 13.187 ;
     RECT  13.512 13.045 14.544 15.637 ;
     RECT  3.528 13.093 4.8 16.981 ;
     RECT  52.2 13.093 53.7 16.261 ;
     RECT  37.944 13.187 40.2 13.285 ;
     RECT  38.712 13.285 40.2 14.437 ;
     RECT  30.648 13.573 32.1 13.909 ;
     RECT  46.968 13.715 48.3 15.973 ;
     RECT  49.272 13.715 50.4 15.349 ;
     RECT  57.96 13.813 59.1 17.029 ;
     RECT  19.752 13.909 20.784 14.197 ;
     RECT  30.744 13.909 32.1 16.933 ;
     RECT  11.832 14.101 13.2 17.605 ;
     RECT  14.616 14.197 15.6 15.013 ;
     RECT  38.808 14.437 40.2 15.637 ;
     RECT  32.412 14.485 33.456 14.819 ;
     RECT  32.412 14.819 33.648 17.077 ;
     RECT  13.512 15.637 14.496 17.077 ;
     RECT  38.952 15.637 40.2 17.317 ;
     RECT  59.412 15.637 60.912 15.925 ;
     RECT  59.784 15.925 60.912 16.549 ;
     RECT  47.016 15.973 48.3 17.029 ;
     RECT  52.632 16.261 53.7 17.077 ;
     RECT  59.784 16.549 60.816 17.029 ;
     RECT  30.888 16.933 32.1 17.221 ;
     RECT  3.528 16.981 4.512 17.029 ;
     RECT  47.064 17.029 48.3 17.365 ;
     RECT  16.44 17.221 17.904 17.605 ;
     RECT  47.112 17.365 48.3 17.653 ;
     RECT  11.976 17.605 13.008 17.797 ;
     RECT  9.096 18.851 10.224 19.909 ;
     RECT  62.568 19.861 63.6 20.533 ;
     RECT  6.312 21.541 7.8 21.637 ;
     RECT  6.312 21.637 7.344 22.741 ;
  END
END hbfd_rly_624_SN
END LIBRARY
